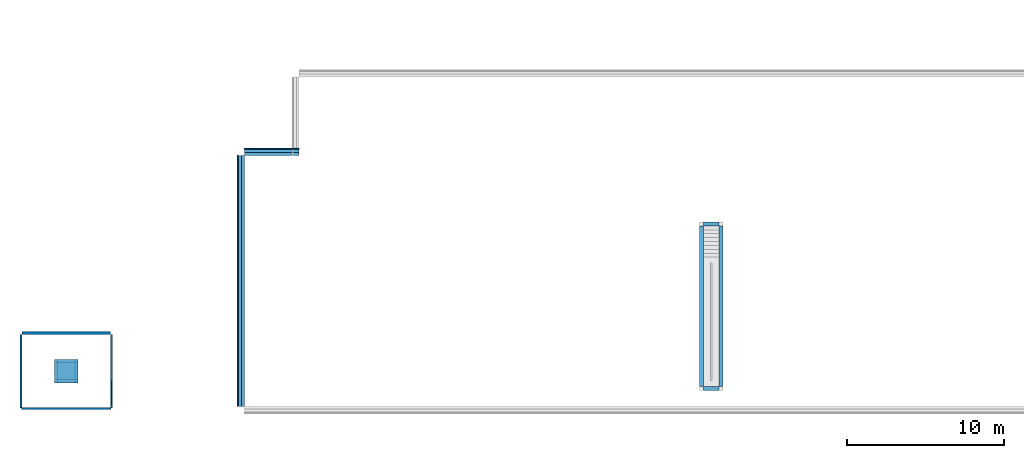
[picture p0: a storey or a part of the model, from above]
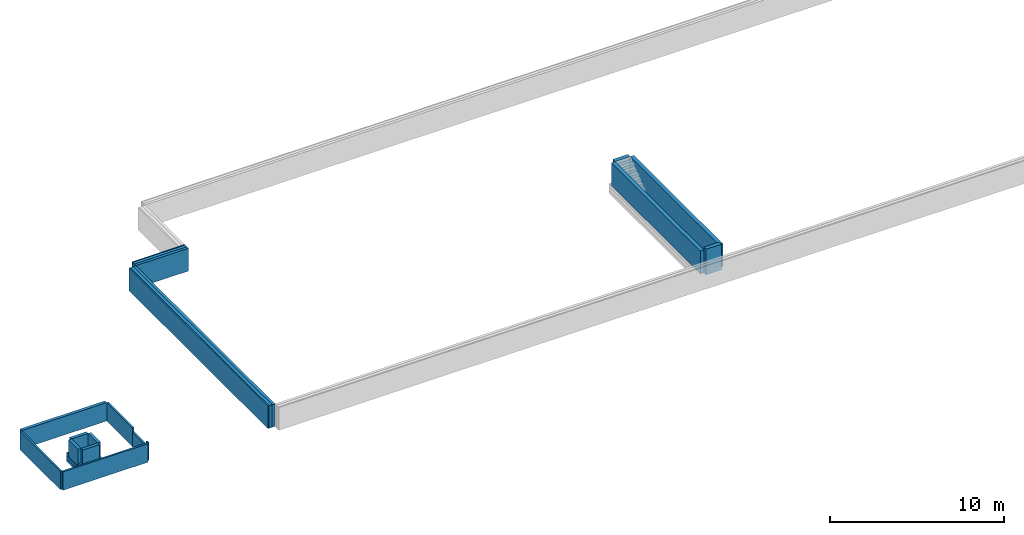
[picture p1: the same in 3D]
Properties of the parts of a building model (IFC2X3), part 1 of 4

# File
Description: ViewDefinition [CoordinationView_V2.0, SpaceBoundary2ndLevelAddOnView], Option [Drawing Scale: 100.000000], Option [Elements to export: Visible elements (on all stories)], Option [Partial Structure Display: Entire Model], Option [IFC Domain: All], Option [Structural Function: All Elements], Option [Convert Grid elements: On], Option [Convert IFC Annotations and ARCHICAD 2D elements: Off], Option [Convert 2D symbols of Doors and Windows: Off], Option [Export geometries that Participates in Collision Detection only: Off], Option [Split complex elements: On], Option [IFC Domain For Space Containment: Custom], Option [Elements in Solid Element Operations: Extruded/revolved], Option [Elements with junctions: Extruded/revolved without junctions], Option [Slabs with slanted edge(s): Extruded], Option [IFC Site Location: At Project Origin], Option [Curtain Wall export mode: Container Element], Option [Railing export mode: Container Element], Option [Stair export mode: Container Element], Option [Properties To Export: All properties], Option [Space containment: Off], Option [Bounding Box: Off], Option [Geometry to type objects: Off], Option [Element Properties: Visible Only], Option [Building Material Properties: Off], Option [Element Parameters: Off], Option [Component Parameters: Off], Option [IFC Base Quantities: Off], Option [Door Window Parameters: On], Option [IFC Space boundaries: On], Option [ARCHICAD Zone Categories as IFC Space classification data: Off], Option [Element Classifications: On]
File name: K:\09-Projektid\3_PÕHIPROJEKT\01-Arhitektuur\IFC\283_PP_ARH_IFC_19.05.2021.ifc
Time: 2021-05-19T14:48:47
Author: Kontakti Täisnimi
Organization: Building Designer Office
Written by: The EXPRESS Data Manager Version 5.02.0100.09 : 26 Sep 2013
Made in: IFC file generated by GRAPHISOFT ARCHICAD 23.0.0 INT FULL Windows version (IFC add-on version: 4006 INT FULL).
Authorization: Kontakti Täisnimi

# IfcSite, Politse- ja Piirivalveameti ning Päästeameti ühishoone
Description: Kinnistu Kirjeldus; RefLatitude: 59, 26, 0, 0; RefLongitude: 24, 45, 0, 0; RefElevation: 0 mm; Classification: 1.0.1 IfcSite (kinnistu) (RKAS BIM + ARCHICAD Classification 23 + v 2.0)
AR_Kinnistu - 020_Pindala: 15638 m2; 025_Max_kõrgus: 18000 mm; 015_Ehitatav_pindala: 5500 m2; 010_Katastritunnus: 32213:001:0035 ja 32213:001:0036

# IfcBuilding, Politse- ja Piirivalveameti ning Päästeameti ühishoone
Classification: 1.0.2 IfcBuilding (hoone) (RKAS BIM + ARCHICAD Classification 23 + v 2.0)
AR_Hoone - 035_Sprinkler: no; 030_Hoone_aadress: Kohtla-Järve Järveküla tee 40 ja 40c; 040_Kõrgus: 8800 mm; 050_Neto_pindala: 2293.7 m2; 055_Neto_ruumala: 13540.2 m3; ?: 1820.8 m2; 001_Nimetus: Politse- ja Piirivalveameti ning Päästeameti ühishoone

# IfcBuildingStorey (5)
In: Politse- ja Piirivalveameti ning Päästeameti ühishoone
Name | Elevation (mm) | 060_Korruse_nimi | 065_Korruse_number | 070_Maapealne | Classification
Vundament | -4000 | Vundament | -1 | no
Esimene korrus | 0 | Esimene korrus | 1 | yes | 1.0.3 IfcBuildingStorey (korrus) (RKAS BIM + ARCHICAD Classification 23 + v 2.0)
Teine korrus | 3800 | Teine korrus | 2 | no | 1.0.3 IfcBuildingStorey (korrus) (RKAS BIM + ARCHICAD Classification 23 + v 2.0)
Katusekorrus | 7600 | Katusekorrus | 3 | no | 1.0.3 IfcBuildingStorey (korrus) (RKAS BIM + ARCHICAD Classification 23 + v 2.0)
Korrus +9.900 | 10600 | 3. Korrus | 4 | no | 1.0.3 IfcBuildingStorey (korrus) (RKAS BIM + ARCHICAD Classification 23 + v 2.0)

# IfcSpace: Üldine (103)
InteriorOrExteriorSpace: INTERNAL; Classification: 1.21 IfcSpaceType (ruum) (RKAS BIM + ARCHICAD Classification)
Pset_SpaceCommon - Reference: Korruse avatud netopind; Category: Üldine
AR_Ruum - 115_Kategooria: Üldine; 110_Tüüp: Korruse avatud netopind; 125_Turvatsoon: Üldine
AC_Pset_RenovationAndPhasing - Renovation Status: New
Name | In | LongName = 100_Nimi | 105_Number | 120_Pindala (m2)
133 | Esimene korrus | ÕPPEKLASS | 133 | 58.961
132 | Esimene korrus | FUAJEE JA OOTEALA | 132 | 46.0777 | Group: TTS-1
108 | Esimene korrus | RIIDED | 108 | 13.8598 | Group: TTS-1
117 | Esimene korrus | KORIDOR | 117 | 7.098
115 | Esimene korrus | LADU | 115 | 30.6687 | Group: TTS-1
102 | Esimene korrus | KOERTE PESU | 102 | 9.3016
103 | Esimene korrus | KOERTE TOIT | 103 | 18.9231
104 | Esimene korrus | HOIDLA 1 | 104 | 34.5052 | Group: TTS-1
107 | Esimene korrus | LABOR | 107 | 14.6453 | Group: TTS-1
105 | Esimene korrus | PÄÄSTETEHNIKA AUTOKOHT JA TEENINDUSALA | 105 | 267.174 | Group: TTS-1
136 | Esimene korrus | WC | 136 | 2.40002
109 | Esimene korrus | VOOLIKUHOOLDUS, LADU, TEHNIK | 109 | 92.1634 | Group: TTS-1
110 | Esimene korrus | PESUBOKS AUTOKOHT | 110 | 77.138 | Group: TTS-1
111 | Esimene korrus | VARUSTUSE HOIDMISE PIND | 111 | 13.1274
112 | Esimene korrus | SOE KONTEINERI KOHT | 112 | 51.2681 | Group: TTS-1
113 | Esimene korrus | SOE KONTEINERI KOHT | 113 | 52.4803 | Group: TTS-1
114 | Esimene korrus | PÄÄSTETEHNIKA ASUKOHT JA TEENINDUSALA | 114 | 238.822 | Group: TTS-1
116 | Esimene korrus | HINGAMISAPARAATIDE JA KEEMIA PÄÄSTEVESTIDE HOIDLA | 116 | 24.4685
118 | Esimene korrus | PÄÄSTERIIETE PESURUUM | 118 | 14.2618
119 | Esimene korrus | PÄÄSTERIIETE HOIURUUM | 119 | 18.421
121 | Esimene korrus | PESURUUM | 121 | 3.6
123 | Esimene korrus | TEHNIKA HOOLDUSRUUM | 123 | 24.6298 | Group: TTS-1
124 | Esimene korrus | MUST LADU | 124 | 42.2885 | Group: TTS-1
126 | Esimene korrus | PUHAS LADU | 126 | 21.5999 | Group: TTS-1
125 | Esimene korrus | MAJAHOIDJA RUUM | 125 | 4.29533
128 | Esimene korrus | KEEMIAHAAGIS | 128 | 36.5666 | Group: TTS-1
129 | Esimene korrus | KEEMIAHAAGIS | 129 | 40.3322 | Group: TTS-1
130 | Esimene korrus | KORISTUSVAHENDID | 130 | 2.55041
134 | Esimene korrus | WC 1 | 134 | 2.12791
135 | Esimene korrus | WC 2 | 135 | 2.12791
137 | Esimene korrus | INVA WC | 137 | 5.72
127 | Esimene korrus | WC | 127 | 2.39959
120 | Esimene korrus | MUSTAD RIIDED | 120 | 4.32
122 | Esimene korrus | PUHTAD RIIDED | 122 | 8.28407
139 | Esimene korrus | HOIURUUM | 139 | 10.752
140 | Esimene korrus | ASITÕENDITE HOIUSTAMISE VAHERUUM | 140 | 4.23248
142 | Esimene korrus | ELEKTRIKILP | 142 | 12.0964 | Group: TTS-1
144 | Esimene korrus | VESTLUSRUUM 2 | 144 | 10.2251
145 | Esimene korrus | MENETLUSRUUM | 145 | 10.224
146 | Esimene korrus | OHVRIABI KABINET | 146 | 10.224
149 | Esimene korrus | TREPIKODA 1 | 149 | 41.1572
148 | Esimene korrus | KORIDOR 1 | 148 | 38.2959
150 | Esimene korrus | TREPIKODA 2 | 150 | 12.366 | Group: TTS-3; TTS-1
151 | Esimene korrus | VENTILATSIOONI SEADMED | 151 | 13.2061 | Group: TTS-1
138 | Esimene korrus | KORISTUSKESKUS + KORISTUSVAHENDID | 138 | 10.3862
147 | Esimene korrus | KLIENDITEENINDUSE HÕIVEKIOSK | 147 | 6.285
141 | Esimene korrus | SERVERIRUUM | 141 | 14.6416 | Group: TTS-1
143 | Esimene korrus | VESTLUSRUUM 1 | 143 | 10.224
131 | Esimene korrus | SOOJASÕLM + VEEMÕÕDUSÕLM + VEEPEHMENDI | 131 | 16.354
106 | Esimene korrus | KOERTE KENNEL 2 | 106 | 5.83342
191 | Esimene korrus | HARJUTUSTORN 1.korrus | 191 | 26.0051
171 | Esimene korrus | HOIURUUM | 171 | 18.2464
101 | Esimene korrus | KOERTE KENNEL 1 | 101 | 5.83342
153 | Esimene korrus | VOOLIKUKUIVATUS | 153 | 9.21462
152 | Esimene korrus | ÕHUVÕTUKAMBER | 152 | 1.25261
181 | Esimene korrus | GARAAZ TSOON 2 | 181 | 145.583
181 | Esimene korrus | GARAAZ TSOON 1 | 181 | 96.4934
225 | Teine korrus | KABINET 2 | 225 | 14.4483
224 | Teine korrus | KABINET 1 | 224 | 14.1122
222 | Teine korrus | ABIRUUM | 222 | 1.11662
221 | Teine korrus | WC N | 221 | 1.22917
201 | Teine korrus | MEESKONNARUUM | 201 | 44.9337
202 | Teine korrus | JUHATAJA | 202 | 14.021
203 | Teine korrus | TÖÖRUUM 1 | 203 | 10.2588
205 | Teine korrus | PUHKETUBA 1 | 205 | 9.32987
207 | Teine korrus | WC | 207 | 2.5376
209 | Teine korrus | HOIDLA ABIRUUM | 209 | 5.23749
208 | Teine korrus | HOIDLA 2 | 208 | 8.06223
211 | Teine korrus | TREPIKODA 1 | 211 | 23.2083 | Group: TTS-2; TTS-3
210 | Teine korrus | VENTILATSIOONI SEADMED | 210 | 82.9101 | Group: TTS-2
246 | Teine korrus | KORISTUS VAHENDID | 246 | 2.92963
212 | Teine korrus | JÕUSAAL | 212 | 50.5212
214 | Teine korrus | RIIETUSRUUM MEHED | 214 | 49.7801
215 | Teine korrus | SAUN M | 215 | 5.26619
216 | Teine korrus | PESURUUM M | 216 | 6.37
217 | Teine korrus | WC M | 217 | 1.28406
218 | Teine korrus | RIIETUSRUUM NAISED | 218 | 23.2138
219 | Teine korrus | SAUN N | 219 | 5.11412
220 | Teine korrus | PESURUUM N | 220 | 6.37999
223 | Teine korrus | TREPIKODA 2 | 223 | 17.1718 | Group: TTS-2; TTS-3
226 | Teine korrus | KABINET 3 | 226 | 14.4476
228 | Teine korrus | KABINET 5 | 228 | 11.076
227 | Teine korrus | KABINET 4 | 227 | 27.2631
230 | Teine korrus | KABINET 7 | 230 | 11.076
232 | Teine korrus | PUHKERUUM | 232 | 15.4464
231 | Teine korrus | KABINET 8 | 231 | 28.0912
235 | Teine korrus | WC | 235 | 1.65
243 | Teine korrus | WC | 243 | 1.62404
234 | Teine korrus | MEESKONNARUUM | 234 | 42.2256
233 | Teine korrus | WC | 233 | 1.75797
236 | Teine korrus | KOMANDOPEALIK | 236 | 12.1645
237 | Teine korrus | MEESKONNAVANEM JA INSPEKTOR | 237 | 16.5681
238 | Teine korrus | PUHKETUBA 1 | 238 | 11.772
239 | Teine korrus | PUHKETUBA 2 | 239 | 11.772
241 | Teine korrus | KORIDOR 1 | 241 | 29.4386
242 | Teine korrus | KORIDOR 2 | 242 | 57.6564
240 | Teine korrus | PUHKETUBA 3 | 240 | 11.772
229 | Teine korrus | KABINET 6 | 229 | 11.076
245 | Teine korrus | KÖÖK JA SÖÖGIRUUM | 245 | 14.7865
291 | Teine korrus | HARJUTUSTORN 2.korrus | 291 | 26.0051
206 | Teine korrus | PUHKETUBA 2 | 206 | 9.32987
204 | Teine korrus | TÖÖRUUM 2 | 204 | 10.2588
247 | Teine korrus | ÕHUVÕTUKAMBER | 247 | 6.41031

# IfcBeam: KON-00_GENEERILINE - KONSTRUKTSIOON 50 x 50 (8)
In: Katusekorrus
Type - PredefinedType: BEAM
Classification: 1.01 IfcBeamType (tala) (RKAS BIM + ARCHICAD Classification); Material: KON-00_GENEERILINE - KONSTRUKTSIOON
Pset_BeamCommon - Reference: KON-00; Slope: 0 deg
AR_001-002 - 002_Tüüp: KON-00
AC_Pset_RenovationAndPhasing - Renovation Status: Existing
Name | Span (mm)
4 x TALA | 690
2 x TALA | 801.788
2 x TALA | 800

# IfcBeam: KON-00_GENEERILINE - KONSTRUKTSIOON 70 x 70 (13)
In: Katusekorrus
Type - PredefinedType: BEAM
Classification: 1.01 IfcBeamType (tala) (RKAS BIM + ARCHICAD Classification); Material: KON-00_GENEERILINE - KONSTRUKTSIOON
Pset_BeamCommon - Reference: KON-00; Slope: 0 deg
AR_001-002 - 002_Tüüp: KON-00
AC_Pset_RenovationAndPhasing - Renovation Status: Existing
Name | Span (mm)
4 x TALA | 900
4 x TALA | 240
2 x TALA | 3100
3 x TALA | 1490

# IfcBeam: KON-00_GENEERILINE - KONSTRUKTSIOON 80 x 100 (38)
Type - PredefinedType: BEAM
Classification: 1.01 IfcBeamType (tala) (RKAS BIM + ARCHICAD Classification); Material: KON-00_GENEERILINE - KONSTRUKTSIOON
Pset_BeamCommon - Reference: KON-00; Span: 3000 mm; Slope: 0 deg; LoadBearing: no; IsExternal: no
AR_001-002 - 001_Nimetus: tõstukse siin; 002_Tüüp: KON-00
AC_Pset_RenovationAndPhasing - Renovation Status: New
Name | In
6 x tõstukse siin | Esimene korrus
32 x tõstukse siin | Teine korrus

# IfcBeam: KON-00_GENEERILINE - KONSTRUKTSIOON 90 x 90 (12)
In: Esimene korrus
Type - PredefinedType: BEAM
Classification: 1.01 IfcBeamType (tala) (RKAS BIM + ARCHICAD Classification); Material: KON-00_GENEERILINE - KONSTRUKTSIOON
Pset_BeamCommon - Reference: KON-00; LoadBearing: yes
AR_001-002 - 002_Tüüp: KON-00
AC_Pset_RenovationAndPhasing - Renovation Status: New
Name | Span (mm) | Slope (deg) | IsExternal
2 x TALA | 12155.1 | 5.7 | no
8 x TALA | 5125.34 | 5.7 | yes
2 x TALA | 19490.2 | 0 | yes

# IfcBeam: Top Chord Pitched-1Way 01 23 (4)
In: Teine korrus
Type - PredefinedType: BEAM
Classification: 1.01 IfcBeamType (tala) (RKAS BIM + ARCHICAD Classification); Material: ET-05_Teras
Pset_BeamCommon - Reference: Top Chord Pitched-1Way 01; LoadBearing: yes; IsExternal: no
AR_001-002 - 002_Tüüp: Top Chord Pitched-1Way 01
AC_Pset_RenovationAndPhasing - Renovation Status: New

# IfcBuildingElementPart (584)
Name | In | Material
2 x VKK-03_Kruus | Vundament | VKK-03_Kruus
SOJ-02_Soojustus - Fiiber Kõva | Vundament | SOJ-02_Soojustus - Fiiber Kõva
VKR-01_Betoon | Vundament | VKR-01_Betoon
24 x KON-04_Betoon - Konstuktsioon | Vundament | KON-04_Betoon - Konstuktsioon
12 x SOJ-06_Soojustus - Plastik Kõva | Vundament | SOJ-06_Soojustus - Plastik Kõva
2 x VKK-02_Liiv | Vundament | VKK-02_Liiv
SV-03_Plaat - Põrand | Vundament | SV-03_Plaat - Põrand
41 x KON-04_Betoon - Konstuktsioon | Esimene korrus | KON-04_Betoon - Konstuktsioon
23 x SOJ-06_Soojustus - Plastik Kõva | Esimene korrus | SOJ-06_Soojustus - Plastik Kõva
10 x Õhkvahe - Raam | Esimene korrus | Õhkvahe - Raam
14 x GENEERILINE - VÄLINE VOODER | Esimene korrus | GENEERILINE - VÄLINE VOODER
14 x SOJ-02_Soojustus - Fiiber Kõva | Esimene korrus | SOJ-02_Soojustus - Fiiber Kõva
KON-05_Betoon Plokk - Konstuktsioon | Esimene korrus | KON-05_Betoon Plokk - Konstuktsioon
34 x Õhkvahe | Esimene korrus | Õhkvahe
12 x Vineer | Esimene korrus | Vineer
13 x VKK-03_Kruus | Esimene korrus | VKK-03_Kruus
10 x VKR-01_Betoon | Esimene korrus | VKR-01_Betoon
4 x ET-06_Teras - Konstruktsioon | Esimene korrus | ET-06_Teras - Konstruktsioon
3 x SKR-05_Vineer | Esimene korrus | SKR-05_Vineer
7 x SKR-01_Õhkvahe - Raam | Esimene korrus | SKR-01_Õhkvahe - Raam
3 x SKR-04_Puitplaat | Esimene korrus | SKR-04_Puitplaat
3 x VKK-02_Liiv | Esimene korrus | VKK-02_Liiv
SV-03_Plaat - Põrand | Esimene korrus | SV-03_Plaat - Põrand
ET-05_Teras | Esimene korrus | ET-05_Teras
2 x ET-02_Raudbetoon - Toode | Esimene korrus | ET-02_Raudbetoon - Toode
7 x ET-05_Teras | Teine korrus | ET-05_Teras
17 x KON-05_Betoon Plokk - Konstuktsioon | Teine korrus | KON-05_Betoon Plokk - Konstuktsioon
39 x KON-04_Betoon - Konstuktsioon | Teine korrus | KON-04_Betoon - Konstuktsioon
18 x SOJ-06_Soojustus - Plastik Kõva | Teine korrus | SOJ-06_Soojustus - Plastik Kõva
11 x ET-01_Puit - Konstruktsioon | Teine korrus | ET-01_Puit - Konstruktsioon
20 x Õhkvahe - Raam | Teine korrus | Õhkvahe - Raam
13 x SOJ-04_Soojustus - Mineraal Kõva | Teine korrus | SOJ-04_Soojustus - Mineraal Kõva
Insulation - Mineral Soft+tala 50x150mm | Teine korrus | Insulation - Mineral Soft+tala 50x150mm
16 x SOJ-02_Soojustus - Fiiber Kõva | Teine korrus | SOJ-02_Soojustus - Fiiber Kõva
13 x KON-06_Raudbetoon - Konstruktsioon | Teine korrus | KON-06_Raudbetoon - Konstruktsioon
12 x VKR-01_Betoon | Teine korrus | VKR-01_Betoon
26 x SKR-02_Kipsplaat | Teine korrus | SKR-02_Kipsplaat
SOJ-03_Soojustus - Mineraal Pehme | Teine korrus | SOJ-03_Soojustus - Mineraal Pehme
9 x SKR-01_Õhkvahe - Raam | Teine korrus | SKR-01_Õhkvahe - Raam
4 x SKR-05_Vineer | Teine korrus | SKR-05_Vineer
SV-03_Plaat - Põrand | Teine korrus | SV-03_Plaat - Põrand
3 x SKR-04_Puitplaat | Teine korrus | SKR-04_Puitplaat
3 x ET-03_Raud | Teine korrus | ET-03_Raud
3 x Betoon | Teine korrus | Betoon
VV-00_GENEERILINE - VÄLINE VOODER | Teine korrus | VV-00_GENEERILINE - VÄLINE VOODER
9 x Õhkvahe | Teine korrus | Õhkvahe
2 x Puit - Konstruktsioon | Teine korrus | Puit - Konstruktsioon
Vineer | Teine korrus | Vineer
16 x KON-04_Betoon - Konstuktsioon | Katusekorrus | KON-04_Betoon - Konstuktsioon
8 x Betoon | Katusekorrus | Betoon
9 x SOJ-02_Soojustus - Fiiber Kõva | Katusekorrus | SOJ-02_Soojustus - Fiiber Kõva
ET-04_Alumiinium | Katusekorrus | ET-04_Alumiinium
11 x Õhkvahe - Raam | Katusekorrus | Õhkvahe - Raam
ET-06_Teras - Konstruktsioon | Katusekorrus | ET-06_Teras - Konstruktsioon
8 x SKR-05_Vineer | Katusekorrus | SKR-05_Vineer
7 x SKR-04_Puitplaat | Katusekorrus | SKR-04_Puitplaat
13 x SKR-01_Õhkvahe - Raam | Katusekorrus | SKR-01_Õhkvahe - Raam
4 x SOJ-06_Soojustus - Plastik Kõva | Katusekorrus | SOJ-06_Soojustus - Plastik Kõva
Vineer | Katusekorrus | Vineer
2 x ET-03_Raud | Katusekorrus | ET-03_Raud
KON-04_Betoon - Konstuktsioon | Korrus +9.900 | KON-04_Betoon - Konstuktsioon
Betoon | Korrus +9.900 | Betoon
SOJ-02_Soojustus - Fiiber Kõva | Korrus +9.900 | SOJ-02_Soojustus - Fiiber Kõva
10 x SKR-01_Õhkvahe - Raam | Korrus +9.900 | SKR-01_Õhkvahe - Raam
5 x SKR-05_Vineer | Korrus +9.900 | SKR-05_Vineer
8 x SKR-04_Puitplaat | Korrus +9.900 | SKR-04_Puitplaat
8 x Õhkvahe - Raam | Korrus +9.900 | Õhkvahe - Raam

# IfcBuildingElementProxy: CHS Hot-Finished Column 23 (2)
In: Katusekorrus
Material: ET-05_Teras
AR_Aken - 355_Pindala: 0 m2
AC_Pset_RenovationAndPhasing - Renovation Status: Existing

# IfcBuildingElementProxy: Caged Ladder 23, SISEREDEL 2
In: Teine korrus
AC_Pset_RenovationAndPhasing - Renovation Status: New

# IfcBuildingElementProxy: Cube 23 (3)
In: Esimene korrus
AR_Aken - 355_Pindala: 0 m2
AC_Pset_RenovationAndPhasing - Renovation Status: New
Name
2 x L-03
Survepesur

# IfcBuildingElementProxy: Cylinder Shell 23, PLAST TORU HARJUTUSTORNIS
In: Esimene korrus
AR_Aken - 355_Pindala: 0 m2
AC_Pset_RenovationAndPhasing - Renovation Status: Existing

# IfcBuildingElementProxy: Downspout 23 (4)
In: Esimene korrus
AR_Aken - 340_Soojusläbivus: 0; 355_Pindala: 0 m2
Name | Renovation Status
VIHMAVEETORU 2 | Existing
VIHMAVEETORU 1 | New
VIHMAVEETORU 4 | Existing
VIHMAVEETORU 3 | Existing

# IfcBuildingElementProxy: Elbow Tube 23 (4)
In: Esimene korrus
Classification: 1.02 IfcBuildingElementProxyType (objekt) (RKAS BIM + ARCHICAD Classification)
Pset_BuildingElementProxyCommon - Reference: Elbow Tube
AR_001-002 - 002_Tüüp: Elbow Tube
AC_Pset_RenovationAndPhasing - Renovation Status: New

# IfcBuildingElementProxy: Grid 23 (39)
AR_Aken - 355_Pindala: 0 m2
AC_Pset_RenovationAndPhasing - Renovation Status: New
Name | In
2 x Äravoolurenn (koertekennel) | Esimene korrus
Trapp (104) | Esimene korrus
2 x Äravoolurenn (109) | Esimene korrus
Trapp (109) | Esimene korrus
Äravoolurenn (110) | Esimene korrus
Trapp (107) | Esimene korrus
3 x Äravoolurenn (105) | Esimene korrus
Äravoolurenn (102) | Esimene korrus
Äravoolurenn (112) | Esimene korrus
Äravoolurenn (113) | Esimene korrus
4 x Äravoolurenn (114) | Esimene korrus
Trapp (120) | Esimene korrus
Trapp (123) | Esimene korrus
3 x Trapp (124) | Esimene korrus
Trapp (131) | Esimene korrus
2 x Trapp (126) | Esimene korrus
Äravoolurenn (128) | Esimene korrus
Äravoolurenn (129) | Esimene korrus
Trapp (151) | Esimene korrus
Trapp (138) | Esimene korrus
Trapp (152) | Esimene korrus
Trapp (137) | Esimene korrus
Trapp (125) | Esimene korrus
Äravoolurenn (220) | Teine korrus
Äravoolurenn (216) | Teine korrus
4 x Trapp (210) | Teine korrus

# IfcBuildingElementProxy: Gutter 23 (2)
In: Katusekorrus
AR_Aken - 340_Soojusläbivus: 0; 355_Pindala: 0 m2
AC_Pset_RenovationAndPhasing - Renovation Status: Existing
Name
VIHMAVEERENN 2
VIHMAVEERENN 1

# IfcBuildingElementProxy: IfcBuildingElementProxy (903)
Material: Teras - Konstruktsioon
Name | In | Classification | Renovation Status
6 x PIIRDE POST - 001 | Esimene korrus | 1.11 IfcRailing (piire) (_RKAS BIM + ARCHICAD Classification) | Existing
3 x Piirde Ülaosa - 001 | Esimene korrus | 1.11 IfcRailing (piire) (_RKAS BIM + ARCHICAD Classification) | New
47 x BALUSTER - 001 | Esimene korrus | 1.11 IfcRailing (piire) (_RKAS BIM + ARCHICAD Classification) | Existing
46 x PIIRDE POST - 001 | Teine korrus | 1.11 IfcRailing (piire) (_RKAS BIM + ARCHICAD Classification) | Existing
25 x Piirde Ülaosa - 001 | Teine korrus | 1.11 IfcRailing (piire) (_RKAS BIM + ARCHICAD Classification) | New
430 x BALUSTER - 001 | Teine korrus | 1.11 IfcRailing (piire) (_RKAS BIM + ARCHICAD Classification) | Existing
4 x Piirde ülemise osa ühendus - 001 | Teine korrus | 1.11 IfcRailing (piire) (_RKAS BIM + ARCHICAD Classification) | New
4 x HANDRAIL END - 001 | Teine korrus | Rail (ARCHICAD Classification) | New
HANDRAIL CONNECTION - 001 | Teine korrus | Rail (ARCHICAD Classification) | New
3 x KÄSIPUU - 001 | Teine korrus | 1.11 IfcRailing (piire) (_RKAS BIM + ARCHICAD Classification) | New
40 x PIIRDE POST - 001 | Katusekorrus | 1.11 IfcRailing (piire) (_RKAS BIM + ARCHICAD Classification) | Existing
20 x Piirde Ülaosa - 001 | Katusekorrus | 1.11 IfcRailing (piire) (_RKAS BIM + ARCHICAD Classification) | New
274 x BALUSTER - 001 | Katusekorrus | 1.11 IfcRailing (piire) (_RKAS BIM + ARCHICAD Classification) | Existing

# IfcBuildingElementProxy: Joists Beam 23 (3)
In: Katusekorrus
Material: ET-05_Teras
AR_Aken - 355_Pindala: 0 m2
AC_Pset_RenovationAndPhasing - Renovation Status: Existing

# IfcBuildingElementProxy: Pressurized Extinguisher 23 (20)
Name | In | 355_Pindala (m2) | Renovation Status
13 x Prügikast | Esimene korrus | 0 | Existing
Balloon Novec 1230 | Esimene korrus |  | New | Classification: 1.02 IfcBuildingElementProxyType (objekt) (RKAS BIM + ARCHICAD Classification); Pset_BuildingElementProxyCommon - Reference: Pressurized Extinguisher; AR_001-002 - 002_Tüüp: Pressurized Extinguisher
6 x Prügikast | Teine korrus | 0 | Existing

# IfcBuildingElementProxy: RHS Cold-Formed Beam 23 (2)
In: Teine korrus
Material: ET-05_Teras
AR_Aken - 355_Pindala: 0 m2
AC_Pset_RenovationAndPhasing - Renovation Status: Existing

# IfcBuildingElementProxy: SHS Cold-Formed Column 23 (1128)
Material: ET-05_Teras
AR_Aken - 355_Pindala: 0 m2
AC_Pset_RenovationAndPhasing - Renovation Status: Existing
Name | In
1088 x Fassaadiribid | Esimene korrus
40 x Fassaadiribid | Teine korrus

# IfcBuildingElementProxy: SHS Hot-Finished Column 23 (7)
In: Esimene korrus
Material: ET-05_Teras
AR_Aken - 355_Pindala: 0 m2
AC_Pset_RenovationAndPhasing - Renovation Status: Existing

# IfcBuildingElementProxy: Shower Door 23, Fassaadiribid
In: Esimene korrus
AR_Aken - 355_Pindala: 0 m2
AC_Pset_RenovationAndPhasing - Renovation Status: Existing

# IfcBuildingElementProxy: Skylight Flat Panel 23 (3)
AR_Aken - 355_Pindala: 0 m2
Name | In | Renovation Status
L-01 | Katusekorrus | Existing
L-01 | Katusekorrus | New
L-02 | Korrus +9.900 | Existing

# IfcBuildingElementProxy: Smoke and Heat Detector 23, Pihusti
In: Esimene korrus
Classification: 1.02 IfcBuildingElementProxyType (objekt) (RKAS BIM + ARCHICAD Classification)
Pset_BuildingElementProxyCommon - Reference: Smoke and Heat Detector
AR_001-002 - 002_Tüüp: Smoke and Heat Detector
AC_Pset_RenovationAndPhasing - Renovation Status: New

# IfcBuildingElementProxy: Tube 23 (4)
In: Esimene korrus
Classification: 1.02 IfcBuildingElementProxyType (objekt) (RKAS BIM + ARCHICAD Classification)
Pset_BuildingElementProxyCommon - Reference: Tube
AR_001-002 - 002_Tüüp: Tube
AC_Pset_RenovationAndPhasing - Renovation Status: New

# IfcBuildingElementProxy: Wall Mounted Tap 23, Veekraan
In: Esimene korrus
AR_Aken - 355_Pindala: 0 m2
AC_Pset_RenovationAndPhasing - Renovation Status: New

# IfcBuildingElementProxy: Waste Receptacle 23, Prügikast
In: Esimene korrus
AR_Aken - 355_Pindala: 0 m2
AC_Pset_RenovationAndPhasing - Renovation Status: Existing

# IfcColumn: ET-02_Raudbetoon - Toode 180 x 180, POST
In: Esimene korrus
Type - PredefinedType: COLUMN
Classification: 1.03 IfcColumnType (post) (RKAS BIM + ARCHICAD Classification); Material: ET-02_Raudbetoon - Toode
Pset_ColumnCommon - Reference: ET-02; Slope: 90 deg; LoadBearing: yes; IsExternal: no
AR_001-002 - 002_Tüüp: ET-02
AC_Pset_RenovationAndPhasing - Renovation Status: New

# IfcColumn: ET-02_Raudbetoon - Toode 350 x 350, POST
In: Esimene korrus
Type - PredefinedType: COLUMN
Classification: 1.03 IfcColumnType (post) (RKAS BIM + ARCHICAD Classification); Material: ET-02_Raudbetoon - Toode
Pset_ColumnCommon - Reference: ET-02; Slope: 90 deg; LoadBearing: yes; IsExternal: no
AR_001-002 - 002_Tüüp: ET-02
AC_Pset_RenovationAndPhasing - Renovation Status: New

# IfcColumn: ET-02_Raudbetoon - Toode 400 x 400 (2)
Type - PredefinedType: COLUMN
Classification: 1.03 IfcColumnType (post) (RKAS BIM + ARCHICAD Classification); Material: ET-02_Raudbetoon - Toode
Pset_ColumnCommon - Reference: ET-02; Slope: 90 deg; LoadBearing: yes; IsExternal: no
AR_001-002 - 002_Tüüp: ET-02
AC_Pset_RenovationAndPhasing - Renovation Status: New
Name | In
POST | Esimene korrus
POST | Teine korrus

# IfcColumn: ET-02_Raudbetoon - Toode 500 x 240, POST
In: Esimene korrus
Type - PredefinedType: COLUMN
Classification: 1.03 IfcColumnType (post) (RKAS BIM + ARCHICAD Classification); Material: ET-02_Raudbetoon - Toode
Pset_ColumnCommon - Reference: ET-02; Slope: 90 deg; LoadBearing: yes; IsExternal: no
AR_001-002 - 002_Tüüp: ET-02
AC_Pset_RenovationAndPhasing - Renovation Status: New

# IfcColumn: ET-05_Teras 180 x 180, POST
In: Teine korrus
Type - PredefinedType: COLUMN
Classification: 1.03 IfcColumnType (post) (RKAS BIM + ARCHICAD Classification)
Pset_ColumnCommon - Reference: ET-05; Slope: 90 deg; LoadBearing: yes; IsExternal: no
AR_001-002 - 002_Tüüp: ET-05
AC_Pset_RenovationAndPhasing - Renovation Status: New

# IfcColumn: ET-05_Teras D140 (2)
In: Esimene korrus
Type - PredefinedType: COLUMN
Classification: 1.03 IfcColumnType (post) (RKAS BIM + ARCHICAD Classification); Material: ET-05_Teras
Pset_ColumnCommon - Reference: Roostevaba teras; Slope: 90 deg; LoadBearing: yes; IsExternal: no
AR_001-002 - 002_Tüüp: Roostevaba teras
AC_Pset_RenovationAndPhasing - Renovation Status: New

# IfcColumn: KON-00_GENEERILINE - KONSTRUKTSIOON 100 x 100 (14)
In: Esimene korrus
Type - PredefinedType: COLUMN
Classification: 1.03 IfcColumnType (post) (RKAS BIM + ARCHICAD Classification); Material: KON-00_GENEERILINE - KONSTRUKTSIOON
Pset_ColumnCommon - Reference: KON-00; Slope: 90 deg; LoadBearing: yes; IsExternal: yes
AR_001-002 - 002_Tüüp: KON-00
AC_Pset_RenovationAndPhasing - Renovation Status: New

# IfcColumn: KON-00_GENEERILINE - KONSTRUKTSIOON 150 x 100 (6)
In: Esimene korrus
Type - PredefinedType: COLUMN
Classification: 1.03 IfcColumnType (post) (RKAS BIM + ARCHICAD Classification); Material: KON-00_GENEERILINE - KONSTRUKTSIOON
Pset_ColumnCommon - Reference: KON-00; Slope: 90 deg; LoadBearing: yes; IsExternal: yes
AR_001-002 - 002_Tüüp: KON-00
AC_Pset_RenovationAndPhasing - Renovation Status: New

# IfcColumn: KON-00_GENEERILINE - KONSTRUKTSIOON 150 x 150 (41)
Type - PredefinedType: COLUMN
Classification: 1.03 IfcColumnType (post) (RKAS BIM + ARCHICAD Classification); Material: KON-00_GENEERILINE - KONSTRUKTSIOON
Pset_ColumnCommon - Reference: KON-00; Slope: 90 deg; LoadBearing: yes; IsExternal: yes
AR_001-002 - 002_Tüüp: KON-00
AC_Pset_RenovationAndPhasing - Renovation Status: New
Name | In
12 x POST | Esimene korrus
12 x POST | Teine korrus
17 x POST | Katusekorrus

# IfcColumn: KON-00_GENEERILINE - KONSTRUKTSIOON 50 x 50 (10)
In: Katusekorrus
Type - PredefinedType: COLUMN
Classification: 1.03 IfcColumnType (post) (RKAS BIM + ARCHICAD Classification); Material: KON-00_GENEERILINE - KONSTRUKTSIOON
Pset_ColumnCommon - Reference: KON-00; Slope: 90 deg
AR_001-002 - 002_Tüüp: KON-00
Name | Renovation Status
2 x POST | New | Pset_ColumnCommon - LoadBearing: yes; IsExternal: yes
8 x POST | Existing

# IfcColumn: KON-00_GENEERILINE - KONSTRUKTSIOON 70 x 70 (14)
In: Katusekorrus
Type - PredefinedType: COLUMN
Classification: 1.03 IfcColumnType (post) (RKAS BIM + ARCHICAD Classification); Material: KON-00_GENEERILINE - KONSTRUKTSIOON
Pset_ColumnCommon - Reference: KON-00; Slope: 90 deg
AR_001-002 - 002_Tüüp: KON-00
AC_Pset_RenovationAndPhasing - Renovation Status: Existing

# IfcColumn: KON-00_GENEERILINE - KONSTRUKTSIOON 80 x 100 (40)
In: Esimene korrus
Type - PredefinedType: COLUMN
Classification: 1.03 IfcColumnType (post) (RKAS BIM + ARCHICAD Classification); Material: KON-00_GENEERILINE - KONSTRUKTSIOON
Pset_ColumnCommon - Reference: KON-00; Slope: 90 deg
AR_001-002 - 002_Tüüp: KON-00
AC_Pset_RenovationAndPhasing - Renovation Status: Existing

# IfcColumn: KON-00_GENEERILINE - KONSTRUKTSIOON 90 x 90 (8)
In: Esimene korrus
Type - PredefinedType: COLUMN
Classification: 1.03 IfcColumnType (post) (RKAS BIM + ARCHICAD Classification); Material: KON-00_GENEERILINE - KONSTRUKTSIOON
Pset_ColumnCommon - Reference: KON-00; Slope: 90 deg; LoadBearing: yes; IsExternal: yes
AR_001-002 - 002_Tüüp: KON-00
AC_Pset_RenovationAndPhasing - Renovation Status: New

# IfcColumn: KON-00_GENEERILINE - KONSTRUKTSIOON D150 (12)
In: Esimene korrus
Type - PredefinedType: COLUMN
Classification: 1.03 IfcColumnType (post) (RKAS BIM + ARCHICAD Classification); Material: KON-00_GENEERILINE - KONSTRUKTSIOON
Pset_ColumnCommon - Reference: KON-00; Slope: 90 deg; LoadBearing: yes; IsExternal: yes
AR_001-002 - 002_Tüüp: KON-00
AC_Pset_RenovationAndPhasing - Renovation Status: New

# IfcDiscreteAccessory: Aluminium 1510, Madalsurve suruõhukompressor
In: Esimene korrus
Classification: 1.09 IfcDiscreteAccessoryType (tarvik) (RKAS BIM + ARCHICAD Classification); Material: Aluminium
AR_001-002 - 002_Tüüp: Aluminium
Pset_QuantityTakeOff - Reference: Aluminium
AC_Pset_RenovationAndPhasing - Renovation Status: New

# IfcDiscreteAccessory: Aluminium 790, Kõrgsurvepesur
In: Esimene korrus
Classification: 1.09 IfcDiscreteAccessoryType (tarvik) (RKAS BIM + ARCHICAD Classification); Material: Aluminium
AR_001-002 - 002_Tüüp: Aluminium
Pset_QuantityTakeOff - Reference: Aluminium
AC_Pset_RenovationAndPhasing - Renovation Status: New

# IfcDiscreteAccessory: Aluminium 840, KOMP (Kõrgsurve surukompressor)
In: Esimene korrus
Classification: 1.09 IfcDiscreteAccessoryType (tarvik) (RKAS BIM + ARCHICAD Classification); Material: Aluminium
AR_001-002 - 002_Tüüp: Aluminium
Pset_QuantityTakeOff - Reference: Aluminium
AC_Pset_RenovationAndPhasing - Renovation Status: New

# IfcDiscreteAccessory: Architrave 01 23 (60)
Classification: 1.09 IfcDiscreteAccessoryType (tarvik) (RKAS BIM + ARCHICAD Classification); Material: SV-01_Krohv - Kips
AR_Aken - 355_Pindala: 0 m2
AR_001-002 - 002_Tüüp: Architrave 01
Pset_QuantityTakeOff - Reference: Architrave 01
AC_Pset_RenovationAndPhasing - Renovation Status: Existing
Name | In
18 x AKNARAAM 01 | Esimene korrus
42 x AKNARAAM 01 | Teine korrus

# IfcDiscreteAccessory: Caged Ladder 23, VÄLISREDEL
In: Esimene korrus
Classification: 1.09 IfcDiscreteAccessoryType (tarvik) (RKAS BIM + ARCHICAD Classification)
AR_001-002 - 002_Tüüp: Caged Ladder
Pset_QuantityTakeOff - Reference: Caged Ladder
AC_Pset_RenovationAndPhasing - Renovation Status: New

# IfcDiscreteAccessory: Solar Photovoltaic Panel 23 (130)
In: Katusekorrus
Classification: 1.09 IfcDiscreteAccessoryType (tarvik) (RKAS BIM + ARCHICAD Classification)
AR_Aken - 355_Pindala: 0 m2
AR_001-002 - 002_Tüüp: Solar Photovoltaic Panel
Pset_QuantityTakeOff - Reference: Solar Photovoltaic Panel
AC_Pset_RenovationAndPhasing - Renovation Status: New

# IfcDiscreteAccessory: Text 3D 23 (2)
In: Katusekorrus
Classification: 1.09 IfcDiscreteAccessoryType (tarvik) (RKAS BIM + ARCHICAD Classification)
AR_001-002 - 002_Tüüp: Text 3D
Pset_QuantityTakeOff - Reference: Text 3D
AC_Pset_RenovationAndPhasing - Renovation Status: New

# IfcDiscreteAccessory: Tube 23 (2)
In: Esimene korrus
Classification: 1.09 IfcDiscreteAccessoryType (tarvik) (RKAS BIM + ARCHICAD Classification)
AR_Aken - 355_Pindala: 0 m2
AR_001-002 - 002_Tüüp: Tube
Pset_QuantityTakeOff - Reference: Tube
AC_Pset_RenovationAndPhasing - Renovation Status: New

# IfcDiscreteAccessory: UAP Column 23 (575)
In: Teine korrus
Classification: 1.09 IfcDiscreteAccessoryType (tarvik) (RKAS BIM + ARCHICAD Classification); Material: ET-05_Teras
AR_Aken - 355_Pindala: 0 m2
AR_001-002 - 002_Tüüp: UAP Column
Pset_QuantityTakeOff - Reference: UAP Column
Name | Renovation Status
552 x Fassaadiribid | Existing
23 x Fassaadiribid | New

# IfcDiscreteAccessory: Vertical Ladder 23 (4)
Classification: 1.09 IfcDiscreteAccessoryType (tarvik) (RKAS BIM + ARCHICAD Classification)
AR_001-002 - 001_Nimetus: välisredel; 002_Tüüp: Vertical Ladder
Pset_QuantityTakeOff - Reference: Vertical Ladder
AC_Pset_RenovationAndPhasing - Renovation Status: New
Name | In
VÄLISREDEL 1 | Esimene korrus
VÄLISREDEL 4 | Esimene korrus
VÄLISREDEL 2 | Teine korrus
VÄLISREDEL 3 | Korrus +9.900

# IfcDoor: Door 23 (2)
Type - OperationType: SINGLE_SWING_LEFT; ParameterTakesPrecedence: no; Sizeable: no
Type - Door Lining Properties - LiningDepth: 115 mm; LiningThickness: 40 mm; ThresholdDepth: 75 mm; ThresholdThickness: 12 mm; LiningOffset: -25 mm; ThresholdOffset: -25 mm; CasingThickness: 50 mm; CasingDepth: 19 mm
Type - Door Panel Properties - Panel 1 - PanelDepth: 40 mm; PanelOperation: SWINGING; PanelWidth: 1; PanelPosition: MIDDLE
OverallHeight: 2100 mm; Classification: 1.10 IfcDoorStyle (uks) (RKAS BIM + ARCHICAD Classification)
Pset_DoorCommon - ThermalTransmittance: 0; IsExternal: no
AR_Uks - 310_Materjal: metall; 320_Klaas: ilma klaasita; 335_Välispiire: no; 340_Soojusläbivus: 0; 345_Päikesekiirgus_tegur: nõudeid ei esitata; 360_Ratastooliga: no; 365_Isesulguv: yes; 370_Evakuatsiooniväljapääs: yes; 375_Viimistlus_seest: MUDELIS: Metal - Steel; Metal - Steel; MÄRKUS:; 376_Viimistlus_väljast: MUDELIS: Metal - Steel; Metal - Steel; MÄRKUS:; 900_Tootja: Undefined; 905_Mudel: Undefined; 910_Tooteinfo: Undefined; 915_Kasutus-ja_hooldusjuhend: Undefined
AC_Pset_RenovationAndPhasing - Renovation Status: New
Name | In | OverallWidth (mm) | Reference = 300_Tüüp | 001_Nimetus | 305_Ava_mõõt | 315_Avanemine | 325_Helipidavus | 330_Tulekindlus | 350_Klaaspakett | 355_Pindala (m2) | 380_Lukustus
SU-01-5 | Esimene korrus | 800 | SU-01-5 | Siseuks | 800x2 100 | Pöördavanev - Parem ; ARCHICAD tüüp: Side Hung | Rw≥30dB | nõudeid ei esitata | nõudeid ei esitata | 1.68 | mehaaniline
TU-01-8 | Teine korrus | 1000 | TU-01-8 | tuletõkke siseuks | 1 000x2 100 | põõrdavanev - Parem ; ARCHICAD tüüp: Side Hung | 30dB | EI30 | ilma klaasita | 2.1 | elektriline

# IfcDoor: Door 23, TU-01-8
In: Esimene korrus
Type - OperationType: SINGLE_SWING_LEFT; ParameterTakesPrecedence: no; Sizeable: no
Type - Door Lining Properties - LiningDepth: 115 mm; LiningThickness: 40 mm; ThresholdDepth: 75 mm; ThresholdThickness: 12 mm; LiningOffset: -60 mm; ThresholdOffset: -20 mm; CasingThickness: 50 mm; CasingDepth: 19 mm
Type - Door Panel Properties - Panel 1 - PanelDepth: 40 mm; PanelOperation: SWINGING; PanelWidth: 1; PanelPosition: MIDDLE
OverallHeight: 2100 mm; OverallWidth: 1000 mm; Classification: 1.10 IfcDoorStyle (uks) (RKAS BIM + ARCHICAD Classification)
Pset_DoorCommon - Reference: TU-01-8; ThermalTransmittance: 0; IsExternal: no
AR_Uks - 001_Nimetus: tuletõkke siseuks; 300_Tüüp: TU-01-8; 305_Ava_mõõt: 1 000x2 100; 310_Materjal: metall; 315_Avanemine: Pöördavanev - Parem ; ARCHICAD tüüp: Side Hung; 320_Klaas: ilma klaasita; 325_Helipidavus: 30 dB; 330_Tulekindlus: EI30; 335_Välispiire: no; 340_Soojusläbivus: 0; 345_Päikesekiirgus_tegur: nõudeid ei esitata; 350_Klaaspakett: ilma klaasita; 355_Pindala: 2.1 m2; 360_Ratastooliga: no; 365_Isesulguv: yes; 370_Evakuatsiooniväljapääs: yes; 375_Viimistlus_seest: MUDELIS: Metal - Steel; Metal - Steel; MÄRKUS:; 376_Viimistlus_väljast: MUDELIS: Metal - Steel; Metal - Steel; MÄRKUS:; 380_Lukustus: elektriline; 900_Tootja: Undefined; 905_Mudel: Undefined; 910_Tooteinfo: Undefined; 915_Kasutus-ja_hooldusjuhend: Undefined
AC_Pset_RenovationAndPhasing - Renovation Status: New

# IfcDoor: Door 23 (12)
Type - OperationType: SINGLE_SWING_LEFT; ParameterTakesPrecedence: no; Sizeable: no
Type - Door Lining Properties - LiningDepth: 115 mm; LiningThickness: 40 mm; ThresholdDepth: 75 mm; ThresholdThickness: 12 mm; LiningOffset: 0 mm; ThresholdOffset: 40 mm; CasingThickness: 50 mm; CasingDepth: 19 mm
Type - Door Panel Properties - Panel 1 - PanelDepth: 40 mm; PanelOperation: SWINGING; PanelWidth: 1; PanelPosition: MIDDLE
Classification: 1.10 IfcDoorStyle (uks) (RKAS BIM + ARCHICAD Classification)
Pset_DoorCommon - ThermalTransmittance: 0
AR_Uks - 900_Tootja: Undefined; 905_Mudel: Undefined; 910_Tooteinfo: Undefined; 915_Kasutus-ja_hooldusjuhend: Undefined
AC_Pset_RenovationAndPhasing - Renovation Status: New
Name | In | OverallHeight (mm) | OverallWidth (mm) | Reference = 300_Tüüp | IsExternal = 335_Välispiire | 001_Nimetus | 305_Ava_mõõt | 310_Materjal | 315_Avanemine | 320_Klaas | 325_Helipidavus | 330_Tulekindlus | 340_Soojusläbivus | 345_Päikesekiirgus_tegur | 350_Klaaspakett | 355_Pindala (m2) | 360_Ratastooliga | 365_Isesulguv = 370_Evakuatsiooniväljapääs | 375_Viimistlus_seest = 376_Viimistlus_väljast | 380_Lukustus
TU-01-8 | Esimene korrus | 2100 | 1000 | TU-01-8 | no | tuletõkke siseuks | 1 000x2 100 | metall | Pöördavanev - Parem ; ARCHICAD tüüp: Side Hung | ilma klaasita | 30dB | EI30 | 0 | nõudeid ei esitata | ilma klaasita | 2.1 | no | no | MUDELIS: Metal - Steel; Metal - Steel; MÄRKUS: | elektriline
TU-01-7 | Esimene korrus | 2100 | 1000 | TU-01-7 | no | tuletõkke siseuks | 1 000x2 100 | metall | Pöördavanev - Parem ; ARCHICAD tüüp: Side Hung | tuletõkkeklaas EI30 | 30 dB | EI30 | 0 | nõudeid ei esitata | tuletõkkeklaas | 2.1 | yes | yes | MUDELIS: Wood - Pine Grained Horizontal; Wood - Pine Grained Horizontal; MÄRKUS: | elektriline | Pset_DoorCommon - GlazingAreaFraction: 1.31837
TU-01-8 | Esimene korrus | 2100 | 1000 | TU-01-8 | no | tuletõkke siseuks | 1 000x2 100 | metall | Pöördavanev - Parem ; ARCHICAD tüüp: Side Hung | ilma klaasita | 30 dB | EI30 | 0 | nõudeid ei esitata | ilma klaasita | 2.1 | no | yes | MUDELIS: Metal - Steel; Metal - Steel; MÄRKUS: | elektriline
2 x SU-02-1 | Esimene korrus | 2100 | 800 | SU-02-1 | no | Siseuks | 800x2 100 | puit | Pöördavanev - Parem ; ARCHICAD tüüp: Side Hung | ilma klaasita | Rw≥30dB | nõudeid ei esitata | 0 | nõudeid ei esitata | nõudeid ei esitata | 1.68 | no | no | MUDELIS: Wood - Pine Grained Horizontal; Wood - Pine Grained Horizontal; MÄRKUS: | mehaaniline
VU-10 | Teine korrus | 2100 | 900 | VU-10 | yes | Välisuks ühepoolne | 900x2 100 | metall | pöördavanev - Parem ; ARCHICAD tüüp: Side Hung | 3xklaaspakett | Rw≥35dB | nõudeid ei esitata | 1.1 | 0,4 | 3k (6+4+10) | 1.89 | no | yes | MUDELIS: Wood - Pine Grained Horizontal; Wood - Pine Grained Horizontal; MÄRKUS: | elektriline | Pset_DoorCommon - GlazingAreaFraction: 1.14117
SU-03-1 | Teine korrus | 2100 | 700 | SU-03-1 | no | siseuks | 700x2 100 | täisklaasuks | pöördavanev - Parem ; ARCHICAD tüüp: Side Hung | toonitud klaas | nõudeid ei esitata | nõudeid ei esitata | 0 | nõudeid ei esitata | 1xklaas | 1.47 | no | no | MUDELIS: Metal - Steel; Metal - Steel; MÄRKUS: | lukus puudub
SU-02-1 | Teine korrus | 2100 | 800 | SU-02-1 | no | siseuks | 800x2 100 | puit | pöördavanev - Parem ; ARCHICAD tüüp: Side Hung | ilma klaasita | Rw≥30dB | nõudeid ei esitata | 0 | nõudeid ei esitata | ilma klaasita | 1.68 | no | yes | MUDELIS: Wood - Pine Grained Horizontal; Wood - Pine Grained Horizontal; MÄRKUS: | mehaaniline
LU-21 | Teine korrus | 1850 | 1100 | LU-21 | yes | aknaluuk | 1 100x1 850 | vineer | pöördavanev - Parem ; ARCHICAD tüüp: Side Hung | ilma klaasita | nõudeid ei esitata | nõudeid ei esitata | 0 | nõudeid ei esitata | ilma klaasita | 2.035 | no | no | MUDELIS: Wood - Pine Grained Horizontal; Wood - Pine Grained Horizontal; MÄRKUS: | mehaaniline
VU-22 | Teine korrus | 2100 | 950 | VU-22 | yes | Välisuks ühepoolne | 950x2 100 | metall | pöördavanev - Parem ; ARCHICAD tüüp: Side Hung | 2xklaaspakett | nõudeid ei esitata | nõudeid ei esitata | 0 | nõudeid ei esitata | 2k 4+10 | 1.995 | no | no | MUDELIS: Wood - Pine Grained Horizontal; Wood - Pine Grained Horizontal; MÄRKUS: | mehaaniline | Pset_DoorCommon - GlazingAreaFraction: 1.22977
SU-01-5 | Teine korrus | 2100 | 800 | SU-01-5 | no | Siseuks | 800x2 100 | metall | põõrdavanev - Parem ; ARCHICAD tüüp: Side Hung | ilma klaasita | nõudeid ei esitata | nõudeid ei esitata | 0 | nõudeid ei esitata | ilma klaasita | 1.68 | no | yes | MUDELIS: Metal - Steel; Metal - Steel; MÄRKUS: | mehaaniline
LU-21 | Katusekorrus | 1850 | 1100 | LU-21 | yes | aknaluuk | 1 100x1 850 | vineer | pöördavanev - Parem ; ARCHICAD tüüp: Side Hung | ilma klaasita | nõudeid ei esitata | nõudeid ei esitata | 0 | nõudeid ei esitata | ilma klaasita | 2.035 | no | no | MUDELIS: Wood - Pine Grained Horizontal; Wood - Pine Grained Horizontal; MÄRKUS: | mehaaniline

# IfcDoor: Door 23 (10)
Type - OperationType: SINGLE_SWING_LEFT; ParameterTakesPrecedence: no; Sizeable: no
Type - Door Lining Properties - LiningDepth: 115 mm; LiningThickness: 40 mm; ThresholdDepth: 75 mm; ThresholdThickness: 12 mm; LiningOffset: 140 mm; ThresholdOffset: 180 mm; CasingThickness: 50 mm; CasingDepth: 19 mm
Type - Door Panel Properties - Panel 1 - PanelDepth: 40 mm; PanelOperation: SWINGING; PanelWidth: 1; PanelPosition: MIDDLE
OverallHeight: 2100 mm; Classification: 1.10 IfcDoorStyle (uks) (RKAS BIM + ARCHICAD Classification)
Pset_DoorCommon - ThermalTransmittance: 0; IsExternal: no
AR_Uks - 335_Välispiire: no; 340_Soojusläbivus: 0; 345_Päikesekiirgus_tegur: nõudeid ei esitata; 900_Tootja: Undefined; 905_Mudel: Undefined; 910_Tooteinfo: Undefined; 915_Kasutus-ja_hooldusjuhend: Undefined
AC_Pset_RenovationAndPhasing - Renovation Status: New
Name | In | OverallWidth (mm) | Reference = 300_Tüüp | 001_Nimetus | 305_Ava_mõõt | 310_Materjal | 315_Avanemine | 320_Klaas | 325_Helipidavus | 330_Tulekindlus | 350_Klaaspakett | 355_Pindala (m2) | 360_Ratastooliga | 365_Isesulguv | 370_Evakuatsiooniväljapääs | 375_Viimistlus_seest = 376_Viimistlus_väljast | 380_Lukustus
2 x SU-01-3 | Esimene korrus | 900 | SU-01-3 | Siseuks | 900x2 100 | metall | Pöördavanev - Parem ; ARCHICAD tüüp: Side Hung | ilma klaasita | nõudeid ei esitata | nõudeid ei esitata | nõudeid ei esitata | 1.89 | no | no | yes | MUDELIS: Wood - Pine Grained Horizontal; Wood - Pine Grained Horizontal; MÄRKUS: | mehaaniline | Pset_DoorCommon - GlazingAreaFraction: 1.46717
SU-02-4 | Esimene korrus | 1000 | SU-02-4 | siseuks | 1 000x2 100 | puit | Pöördavanev - Parem ; ARCHICAD tüüp: Side Hung | ilma klaasita | Rw≥30dB | nõudeid ei esitata | nõudeid ei esitata | 2.1 | no | no | yes | MUDELIS: Wood - Pine Grained Horizontal; Wood - Pine Grained Horizontal; MÄRKUS: | mehaaniline
SU-01-1 | Esimene korrus | 900 | SU-01-1 | Siseuks | 900x2 100 | metall | Pöördavanev - Parem ; ARCHICAD tüüp: Side Hung | ilma klaasita | Rw≥30dB | nõudeid ei esitata | nõudeid ei esitata | 1.89 | yes | yes | yes | MUDELIS: Metal - Steel; Metal - Steel; MÄRKUS: | elektriline
TU-01-7 | Esimene korrus | 1000 | TU-01-7 | tuletõkke siseuks | 1 000x2 100 | metall | Pöördavanev - Parem ; ARCHICAD tüüp: Side Hung | tuletõkkeklaas EI30 | 30 dB | EI30 | tuletõkkeklaas | 2.1 | yes | yes | yes | MUDELIS: Wood - Pine Grained Horizontal; Wood - Pine Grained Horizontal; MÄRKUS: | elektriline | Pset_DoorCommon - GlazingAreaFraction: 1.31837
SU-01-1 | Esimene korrus | 900 | SU-01-1 | Siseuks | 900x2 100 | metall | Pöördavanev - Parem ; ARCHICAD tüüp: Side Hung | ilma klaasita | Rw≥30dB | nõudeid ei esitata | nõudeid ei esitata | 1.89 | no | yes | yes | MUDELIS: Metal - Steel; Metal - Steel; MÄRKUS: | elektriline
SU-02-1 | Teine korrus | 800 | SU-02-1 | siseuks | 800x2 100 | puit | pöördavanev - Parem ; ARCHICAD tüüp: Side Hung | ilma klaasita | Rw≥30dB | nõudeid ei esitata | ilma klaasita | 1.68 | no | yes | yes | MUDELIS: Metal - Steel; Metal - Steel; MÄRKUS: | mehaaniline
SU-02-1 | Teine korrus | 800 | SU-02-1 | siseuks | 800x2 100 | puit | pöördavanev - Parem ; ARCHICAD tüüp: Side Hung | ilma klaasita | Rw≥30dB | nõudeid ei esitata | ilma klaasita | 1.68 | no | yes | yes | MUDELIS: Wood - Pine Grained Horizontal; Wood - Pine Grained Horizontal; MÄRKUS: | mehaaniline
SU-01-1 | Teine korrus | 900 | SU-01-1 | Siseuks | 900x2 100 | metall | pöördavanev - Parem ; ARCHICAD tüüp: Side Hung | ilma klaasita | Rw≥30dB | nõudeid ei esitata | ilma klaasita | 1.89 | no | no | no | MUDELIS: Metal - Steel; Metal - Steel; MÄRKUS: | elektriline
SU-01-2 | Teine korrus | 1000 | SU-01-2 | siseuks | 1 000x2 100 | metall | põõrdavanev - Parem ; ARCHICAD tüüp: Side Hung | ilma klaasita | Rw≥30dB | nõudeid ei esitata | ilma klaasita | 2.1 | no | no | no | MUDELIS: Wood - Pine Grained Horizontal; Wood - Pine Grained Horizontal; MÄRKUS: | elektriline

# IfcDoor: Door 23 (2)
In: Esimene korrus
Type - OperationType: SINGLE_SWING_LEFT; ParameterTakesPrecedence: no; Sizeable: no
Type - Door Lining Properties - LiningDepth: 115 mm; LiningThickness: 40 mm; ThresholdDepth: 75 mm; ThresholdThickness: 12 mm; LiningOffset: 190 mm; ThresholdOffset: 230 mm; CasingThickness: 50 mm; CasingDepth: 19 mm
Type - Door Panel Properties - Panel 1 - PanelDepth: 40 mm; PanelOperation: SWINGING; PanelWidth: 1; PanelPosition: MIDDLE
OverallHeight: 2100 mm; OverallWidth: 900 mm; Classification: 1.10 IfcDoorStyle (uks) (RKAS BIM + ARCHICAD Classification)
Pset_DoorCommon - Reference: TU-01-10; ThermalTransmittance: 0; IsExternal: no
AR_Uks - 001_Nimetus: tuletõkke siseuks; 300_Tüüp: TU-01-10; 305_Ava_mõõt: 900x2 100; 310_Materjal: metall; 315_Avanemine: Pöördavanev - Parem ; ARCHICAD tüüp: Side Hung; 320_Klaas: ilma klaasita; 325_Helipidavus: 30 dB; 330_Tulekindlus: EI30; 335_Välispiire: no; 340_Soojusläbivus: 0; 345_Päikesekiirgus_tegur: nõudeid ei esitata; 350_Klaaspakett: nõudeid ei esitata; 355_Pindala: 1.89 m2; 360_Ratastooliga: no; 365_Isesulguv: yes; 370_Evakuatsiooniväljapääs: no; 375_Viimistlus_seest: MUDELIS: Wood - Pine Grained Horizontal; Wood - Pine Grained Horizontal; MÄRKUS:; 376_Viimistlus_väljast: MUDELIS: Wood - Pine Grained Horizontal; Wood - Pine Grained Horizontal; MÄRKUS:; 380_Lukustus: elektriline; 900_Tootja: Undefined; 905_Mudel: Undefined; 910_Tooteinfo: Undefined; 915_Kasutus-ja_hooldusjuhend: Undefined
AC_Pset_RenovationAndPhasing - Renovation Status: New

# IfcDoor: Door 23, SU-01-4
In: Teine korrus
Type - OperationType: SINGLE_SWING_LEFT; ParameterTakesPrecedence: no; Sizeable: no
Type - Door Lining Properties - LiningDepth: 115 mm; LiningThickness: 40 mm; ThresholdDepth: 75 mm; ThresholdThickness: 12 mm; LiningOffset: 205 mm; ThresholdOffset: 245 mm; CasingThickness: 50 mm; CasingDepth: 19 mm
Type - Door Panel Properties - Panel 1 - PanelDepth: 40 mm; PanelOperation: SWINGING; PanelWidth: 1; PanelPosition: MIDDLE
OverallHeight: 2100 mm; OverallWidth: 900 mm; Classification: 1.10 IfcDoorStyle (uks) (RKAS BIM + ARCHICAD Classification)
Pset_DoorCommon - Reference: SU-01-4; ThermalTransmittance: 0; GlazingAreaFraction: 1.46717; IsExternal: no
AR_Uks - 001_Nimetus: Siseuks; 300_Tüüp: SU-01-4; 305_Ava_mõõt: 900x2 100; 310_Materjal: metall; 315_Avanemine: Pöördavanev - Parem ; ARCHICAD tüüp: Side Hung; 320_Klaas: ilma klaasita; 325_Helipidavus: nõudeid ei esitata; 330_Tulekindlus: nõudeid ei esitata; 335_Välispiire: no; 340_Soojusläbivus: 0; 345_Päikesekiirgus_tegur: nõudeid ei esitata; 350_Klaaspakett: nõudeid ei esitata; 355_Pindala: 1.89 m2; 360_Ratastooliga: no; 365_Isesulguv: yes; 370_Evakuatsiooniväljapääs: yes; 375_Viimistlus_seest: MUDELIS: Wood - Pine Grained Horizontal; Wood - Pine Grained Horizontal; MÄRKUS:; 376_Viimistlus_väljast: MUDELIS: Wood - Pine Grained Horizontal; Wood - Pine Grained Horizontal; MÄRKUS:; 380_Lukustus: elektriline; 900_Tootja: Undefined; 905_Mudel: Undefined; 910_Tooteinfo: Undefined; 915_Kasutus-ja_hooldusjuhend: Undefined
AC_Pset_RenovationAndPhasing - Renovation Status: New

# IfcDoor: Door 23 (2)
In: Esimene korrus
Type - OperationType: SINGLE_SWING_LEFT; ParameterTakesPrecedence: no; Sizeable: no
Type - Door Lining Properties - LiningDepth: 115 mm; LiningThickness: 40 mm; ThresholdDepth: 75 mm; ThresholdThickness: 12 mm; LiningOffset: 235 mm; ThresholdOffset: 235 mm; CasingThickness: 50 mm; CasingDepth: 19 mm
Type - Door Panel Properties - Panel 1 - PanelDepth: 40 mm; PanelOperation: SWINGING; PanelWidth: 1; PanelPosition: MIDDLE
OverallHeight: 2100 mm; OverallWidth: 800 mm; Classification: 1.10 IfcDoorStyle (uks) (RKAS BIM + ARCHICAD Classification)
Pset_DoorCommon - Reference: SU-01-6; ThermalTransmittance: 0; IsExternal: no
AR_Uks - 001_Nimetus: Siseuks; 300_Tüüp: SU-01-6; 305_Ava_mõõt: 800x2 100; 310_Materjal: metall; 315_Avanemine: Pöördavanev - Parem ; ARCHICAD tüüp: Side Hung; 320_Klaas: ilma klaasita; 325_Helipidavus: nõudeid ei esitata; 330_Tulekindlus: nõudeid ei esitata; 335_Välispiire: no; 340_Soojusläbivus: 0; 345_Päikesekiirgus_tegur: nõudeid ei esitata; 350_Klaaspakett: nõudeid ei esitata; 355_Pindala: 1.68 m2; 360_Ratastooliga: no; 365_Isesulguv: yes; 370_Evakuatsiooniväljapääs: yes; 375_Viimistlus_seest: MUDELIS: Metal - Steel; Metal - Steel; MÄRKUS:; 376_Viimistlus_väljast: MUDELIS: Metal - Steel; Metal - Steel; MÄRKUS:; 380_Lukustus: elektriline; 900_Tootja: Undefined; 905_Mudel: Undefined; 910_Tooteinfo: Undefined; 915_Kasutus-ja_hooldusjuhend: Undefined
AC_Pset_RenovationAndPhasing - Renovation Status: New

# IfcDoor: Door 23, SU-01-1
In: Esimene korrus
Type - OperationType: SINGLE_SWING_LEFT; ParameterTakesPrecedence: no; Sizeable: no
Type - Door Lining Properties - LiningDepth: 115 mm; LiningThickness: 40 mm; ThresholdDepth: 75 mm; ThresholdThickness: 12 mm; LiningOffset: 240 mm; ThresholdOffset: 280 mm; CasingThickness: 50 mm; CasingDepth: 19 mm
Type - Door Panel Properties - Panel 1 - PanelDepth: 40 mm; PanelOperation: SWINGING; PanelWidth: 1; PanelPosition: MIDDLE
OverallHeight: 2100 mm; OverallWidth: 900 mm; Classification: 1.10 IfcDoorStyle (uks) (RKAS BIM + ARCHICAD Classification)
Pset_DoorCommon - Reference: SU-01-1; ThermalTransmittance: 0; IsExternal: no
AR_Uks - 001_Nimetus: Siseuks; 300_Tüüp: SU-01-1; 305_Ava_mõõt: 900x2 100; 310_Materjal: metall; 315_Avanemine: Pöördavanev - Parem ; ARCHICAD tüüp: Side Hung; 320_Klaas: ilma klaasita; 325_Helipidavus: Rw≥30dB; 330_Tulekindlus: nõudeid ei esitata; 335_Välispiire: no; 340_Soojusläbivus: 0; 345_Päikesekiirgus_tegur: nõudeid ei esitata; 350_Klaaspakett: nõudeid ei esitata; 355_Pindala: 1.89 m2; 360_Ratastooliga: no; 365_Isesulguv: yes; 370_Evakuatsiooniväljapääs: yes; 375_Viimistlus_seest: MUDELIS: Metal - Steel; Metal - Steel; MÄRKUS:; 376_Viimistlus_väljast: MUDELIS: Metal - Steel; Metal - Steel; MÄRKUS:; 380_Lukustus: elektriline; 900_Tootja: Undefined; 905_Mudel: Undefined; 910_Tooteinfo: Undefined; 915_Kasutus-ja_hooldusjuhend: Undefined
AC_Pset_RenovationAndPhasing - Renovation Status: New

# IfcDoor: Door 23 (2)
In: Esimene korrus
Type - OperationType: SINGLE_SWING_LEFT; ParameterTakesPrecedence: no; Sizeable: no
Type - Door Lining Properties - LiningDepth: 115 mm; LiningThickness: 40 mm; ThresholdDepth: 75 mm; ThresholdThickness: 12 mm; LiningOffset: 50 mm; ThresholdOffset: 90 mm; CasingThickness: 50 mm; CasingDepth: 19 mm
Type - Door Panel Properties - Panel 1 - PanelDepth: 40 mm; PanelOperation: SWINGING; PanelWidth: 1; PanelPosition: MIDDLE
OverallHeight: 2100 mm; OverallWidth: 900 mm; Classification: 1.10 IfcDoorStyle (uks) (RKAS BIM + ARCHICAD Classification)
Pset_DoorCommon - Reference: VU-09; ThermalTransmittance: 0; GlazingAreaFraction: 1.46717; IsExternal: yes
AR_Uks - 001_Nimetus: välisuks ühepoolne; 300_Tüüp: VU-09; 305_Ava_mõõt: 900x2 100; 310_Materjal: metall; 315_Avanemine: põõrdavanev - Parem ; ARCHICAD tüüp: Side Hung; 320_Klaas: ilma klaasita, metallvõrk; 325_Helipidavus: nõudeid ei esitata; 330_Tulekindlus: nõudeid ei esitata; 335_Välispiire: yes; 340_Soojusläbivus: 0; 345_Päikesekiirgus_tegur: nõudeid ei esitata; 350_Klaaspakett: ilma klaasita; 355_Pindala: 1.89 m2; 360_Ratastooliga: no; 365_Isesulguv: no; 370_Evakuatsiooniväljapääs: no; 375_Viimistlus_seest: MUDELIS: Wood - Pine Grained Horizontal; Wood - Pine Grained Horizontal; MÄRKUS:; 376_Viimistlus_väljast: MUDELIS: Wood - Pine Grained Horizontal; Wood - Pine Grained Horizontal; MÄRKUS:; 380_Lukustus: mehaaniline; 900_Tootja: Undefined; 905_Mudel: Undefined; 910_Tooteinfo: Undefined; 915_Kasutus-ja_hooldusjuhend: Undefined
AC_Pset_RenovationAndPhasing - Renovation Status: New

# IfcDoor: Door 23, SU-01-7
In: Esimene korrus
Type - OperationType: SINGLE_SWING_LEFT; ParameterTakesPrecedence: no; Sizeable: no
Type - Door Lining Properties - LiningDepth: 115 mm; LiningThickness: 40 mm; ThresholdDepth: 75 mm; ThresholdThickness: 12 mm; LiningOffset: 80 mm; ThresholdOffset: 120 mm; CasingThickness: 50 mm; CasingDepth: 19 mm
Type - Door Panel Properties - Panel 1 - PanelDepth: 40 mm; PanelOperation: SWINGING; PanelWidth: 1; PanelPosition: MIDDLE
OverallHeight: 2100 mm; OverallWidth: 900 mm; Classification: 1.10 IfcDoorStyle (uks) (RKAS BIM + ARCHICAD Classification)
Pset_DoorCommon - Reference: SU-01-7; ThermalTransmittance: 0; IsExternal: no
AR_Uks - 001_Nimetus: Siseuks; 300_Tüüp: SU-01-7; 305_Ava_mõõt: 900x2 100; 310_Materjal: metall; 315_Avanemine: pöördavanev - Parem ; ARCHICAD tüüp: Side Hung; 320_Klaas: ilma klaasita; 325_Helipidavus: nõudeid ei esitata; 330_Tulekindlus: nõudeid ei esitata; 335_Välispiire: no; 340_Soojusläbivus: 1.1; 345_Päikesekiirgus_tegur: nõudeid ei esitata; 350_Klaaspakett: ilma klaasita; 355_Pindala: 1.89 m2; 360_Ratastooliga: no; 365_Isesulguv: no; 370_Evakuatsiooniväljapääs: yes; 375_Viimistlus_seest: MUDELIS: Metal - Steel; Metal - Steel; MÄRKUS:; 376_Viimistlus_väljast: MUDELIS: Metal - Steel; Metal - Steel; MÄRKUS:; 380_Lukustus: mehaaniline; 900_Tootja: Undefined; 905_Mudel: Undefined; 910_Tooteinfo: Undefined; 915_Kasutus-ja_hooldusjuhend: Undefined
AC_Pset_RenovationAndPhasing - Renovation Status: New

# IfcDoor: Door 23, VU-04
In: Esimene korrus
Type - OperationType: SINGLE_SWING_LEFT; ParameterTakesPrecedence: no; Sizeable: no
Type - Door Lining Properties - LiningDepth: 115 mm; LiningThickness: 40 mm; ThresholdDepth: 75 mm; ThresholdThickness: 12 mm; LiningOffset: 80 mm; ThresholdOffset: 120 mm
Type - Door Panel Properties - Panel 1 - PanelDepth: 40 mm; PanelOperation: SWINGING; PanelWidth: 1; PanelPosition: MIDDLE
OverallHeight: 2100 mm; OverallWidth: 900 mm; Classification: 1.10 IfcDoorStyle (uks) (RKAS BIM + ARCHICAD Classification)
Pset_DoorCommon - Reference: VU-04; ThermalTransmittance: 0; GlazingAreaFraction: 1.14117; IsExternal: yes
AR_Uks - 001_Nimetus: ühepoolne välisuks; 300_Tüüp: VU-04; 305_Ava_mõõt: 900x2 100; 310_Materjal: metall; 315_Avanemine: põõrdavanev - Parem ; ARCHICAD tüüp: Side Hung; 320_Klaas: ilma klaasita; 325_Helipidavus: nõudeid ei esitata; 330_Tulekindlus: nõudeid ei esitata; 335_Välispiire: yes; 340_Soojusläbivus: 0; 345_Päikesekiirgus_tegur: nõudeid ei esitata; 350_Klaaspakett: ilma klaasita; 355_Pindala: 1.89 m2; 360_Ratastooliga: no; 365_Isesulguv: yes; 370_Evakuatsiooniväljapääs: no; 375_Viimistlus_seest: MUDELIS: Wood - Pine Grained Horizontal; Wood - Pine Grained Horizontal; MÄRKUS:; 376_Viimistlus_väljast: MUDELIS: Wood - Pine Grained Horizontal; Wood - Pine Grained Horizontal; MÄRKUS:; 380_Lukustus: elektriline; 900_Tootja: Undefined; 905_Mudel: Undefined; 910_Tooteinfo: Undefined; 915_Kasutus-ja_hooldusjuhend: Undefined
AC_Pset_RenovationAndPhasing - Renovation Status: New

# IfcDoor: Door 23, VU-61 (kuulub hoidla komplekti)
In: Esimene korrus
Type - OperationType: SINGLE_SWING_RIGHT; ParameterTakesPrecedence: no; Sizeable: no
Type - Door Lining Properties - LiningDepth: 115 mm; LiningThickness: 40 mm; LiningOffset: 300 mm; CasingThickness: 50 mm; CasingDepth: 19 mm
Type - Door Panel Properties - Panel 1 - PanelDepth: 40 mm; PanelOperation: SWINGING; PanelWidth: 1; PanelPosition: MIDDLE
OverallHeight: 2000 mm; OverallWidth: 1300 mm; Classification: 1.10 IfcDoorStyle (uks) (RKAS BIM + ARCHICAD Classification)
Pset_DoorCommon - Reference: VU-61 (kuulub hoidla komplekti); ThermalTransmittance: 0; IsExternal: yes
AR_Uks - 001_Nimetus: Välisuks ühepoolne; 300_Tüüp: VU-61 (kuulub hoidla komplekti); 305_Ava_mõõt: 1 300x2 000; 310_Materjal: metall; 315_Avanemine: pöördavanev - Vasak ; ARCHICAD tüüp: Side Hung; 320_Klaas: ilma klaasita; 325_Helipidavus: nõudeid ei esitata; 330_Tulekindlus: nõudeid ei esitata; 335_Välispiire: yes; 340_Soojusläbivus: 0; 345_Päikesekiirgus_tegur: nõudeid ei esitata; 350_Klaaspakett: ilma klaasita; 355_Pindala: 2.6 m2; 360_Ratastooliga: no; 365_Isesulguv: no; 370_Evakuatsiooniväljapääs: no; 375_Viimistlus_seest: MUDELIS: Wood - Pine Grained Horizontal; Wood - Pine Grained Horizontal; MÄRKUS:; 376_Viimistlus_väljast: MUDELIS: Wood - Pine Grained Horizontal; Wood - Pine Grained Horizontal; MÄRKUS:; 380_Lukustus: elektriline; 900_Tootja: Undefined; 905_Mudel: Undefined; 910_Tooteinfo: Undefined; 915_Kasutus-ja_hooldusjuhend: Undefined
AC_Pset_RenovationAndPhasing - Renovation Status: New

# IfcDoor: Door 23, TU-01-11
In: Teine korrus
Type - OperationType: SINGLE_SWING_RIGHT; ParameterTakesPrecedence: no; Sizeable: no
Type - Door Lining Properties - LiningDepth: 115 mm; LiningThickness: 40 mm; ThresholdDepth: 75 mm; ThresholdThickness: 12 mm; LiningOffset: -1.38778e-14 mm; ThresholdOffset: -1.38778e-14 mm; CasingThickness: 50 mm; CasingDepth: 19 mm
Type - Door Panel Properties - Panel 1 - PanelDepth: 40 mm; PanelOperation: SWINGING; PanelWidth: 1; PanelPosition: MIDDLE
OverallHeight: 2100 mm; OverallWidth: 900 mm; Classification: 1.10 IfcDoorStyle (uks) (RKAS BIM + ARCHICAD Classification)
Pset_DoorCommon - Reference: TU-01-11; ThermalTransmittance: 0; IsExternal: no
AR_Uks - 001_Nimetus: tuletõkke siseuks; 300_Tüüp: TU-01-11; 305_Ava_mõõt: 900x2 100; 310_Materjal: metall; 315_Avanemine: pöördavanev - Vasak ; ARCHICAD tüüp: Side Hung; 320_Klaas: ilma klaasita; 325_Helipidavus: 30dB; 330_Tulekindlus: EI30; 335_Välispiire: no; 340_Soojusläbivus: 0; 345_Päikesekiirgus_tegur: nõueid ei esitata; 350_Klaaspakett: nõudeid ei esitata; 355_Pindala: 1.89 m2; 360_Ratastooliga: no; 365_Isesulguv: yes; 370_Evakuatsiooniväljapääs: yes; 375_Viimistlus_seest: MUDELIS: Metal - Steel; Metal - Steel; MÄRKUS:; 376_Viimistlus_väljast: MUDELIS: Metal - Steel; Metal - Steel; MÄRKUS:; 380_Lukustus: elektriline; 900_Tootja: Undefined; 905_Mudel: Undefined; 910_Tooteinfo: Undefined; 915_Kasutus-ja_hooldusjuhend: Undefined
AC_Pset_RenovationAndPhasing - Renovation Status: New

# IfcDoor: Door 23 (4)
Type - OperationType: SINGLE_SWING_RIGHT; ParameterTakesPrecedence: no; Sizeable: no
Type - Door Lining Properties - LiningDepth: 115 mm; LiningThickness: 40 mm; ThresholdDepth: 75 mm; ThresholdThickness: 12 mm; LiningOffset: -25 mm; ThresholdOffset: -25 mm; CasingThickness: 50 mm; CasingDepth: 19 mm
Type - Door Panel Properties - Panel 1 - PanelDepth: 40 mm; PanelOperation: SWINGING; PanelWidth: 1; PanelPosition: MIDDLE
OverallHeight: 2100 mm; Classification: 1.10 IfcDoorStyle (uks) (RKAS BIM + ARCHICAD Classification)
Pset_DoorCommon - ThermalTransmittance: 0; IsExternal: no
AR_Uks - 310_Materjal: metall; 320_Klaas: ilma klaasita; 335_Välispiire: no; 340_Soojusläbivus: 0; 345_Päikesekiirgus_tegur: nõudeid ei esitata; 360_Ratastooliga: no; 370_Evakuatsiooniväljapääs: yes; 380_Lukustus: elektriline; 900_Tootja: Undefined; 905_Mudel: Undefined; 910_Tooteinfo: Undefined; 915_Kasutus-ja_hooldusjuhend: Undefined
AC_Pset_RenovationAndPhasing - Renovation Status: New
Name | In | OverallWidth (mm) | Reference = 300_Tüüp | 001_Nimetus | 305_Ava_mõõt | 315_Avanemine | 325_Helipidavus | 330_Tulekindlus | 350_Klaaspakett | 355_Pindala (m2) | 365_Isesulguv | 375_Viimistlus_seest = 376_Viimistlus_väljast
SU-01-1 | Esimene korrus | 900 | SU-01-1 | Siseuks | 900x2 100 | Pöördavanev - Vasak ; ARCHICAD tüüp: Side Hung | Rw≥30dB | nõudeid ei esitata | nõudeid ei esitata | 1.89 | yes | MUDELIS: Wood - Pine Grained Horizontal; Wood - Pine Grained Horizontal; MÄRKUS:
2 x TU-01-10 | Teine korrus | 900 | TU-01-10 | tuletõkke siseuks | 900x2 100 | pöördavanev - Vasak ; ARCHICAD tüüp: Side Hung | 30dB | EI30 | ilma klaasita | 1.89 | yes | MUDELIS: Metal - Steel; Metal - Steel; MÄRKUS:
SU-01-2 | Teine korrus | 1000 | SU-01-2 | Siseuks | 1 000x2 100 | pöördavanev - Vasak ; ARCHICAD tüüp: Side Hung | Rw≥30dB | nõudeid ei esitata | ilma klaasita | 2.1 | no | MUDELIS: Metal - Steel; Metal - Steel; MÄRKUS:

# IfcDoor: Door 23 (8)
Type - OperationType: SINGLE_SWING_RIGHT; ParameterTakesPrecedence: no; Sizeable: no
Type - Door Lining Properties - LiningDepth: 115 mm; LiningThickness: 40 mm; ThresholdDepth: 75 mm; ThresholdThickness: 12 mm; LiningOffset: 0 mm; ThresholdOffset: 40 mm; CasingThickness: 50 mm; CasingDepth: 19 mm
Type - Door Panel Properties - Panel 1 - PanelDepth: 40 mm; PanelOperation: SWINGING; PanelWidth: 1; PanelPosition: MIDDLE
Classification: 1.10 IfcDoorStyle (uks) (RKAS BIM + ARCHICAD Classification)
Pset_DoorCommon - ThermalTransmittance: 0; IsExternal: no
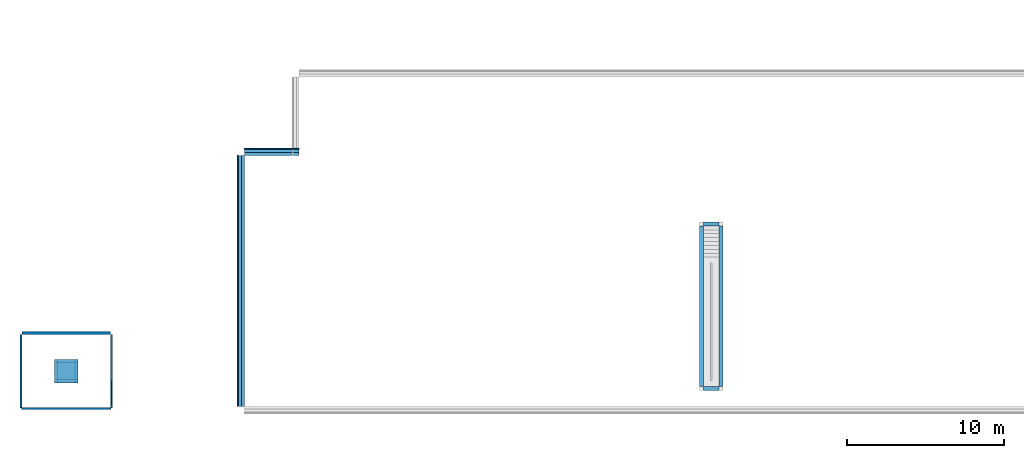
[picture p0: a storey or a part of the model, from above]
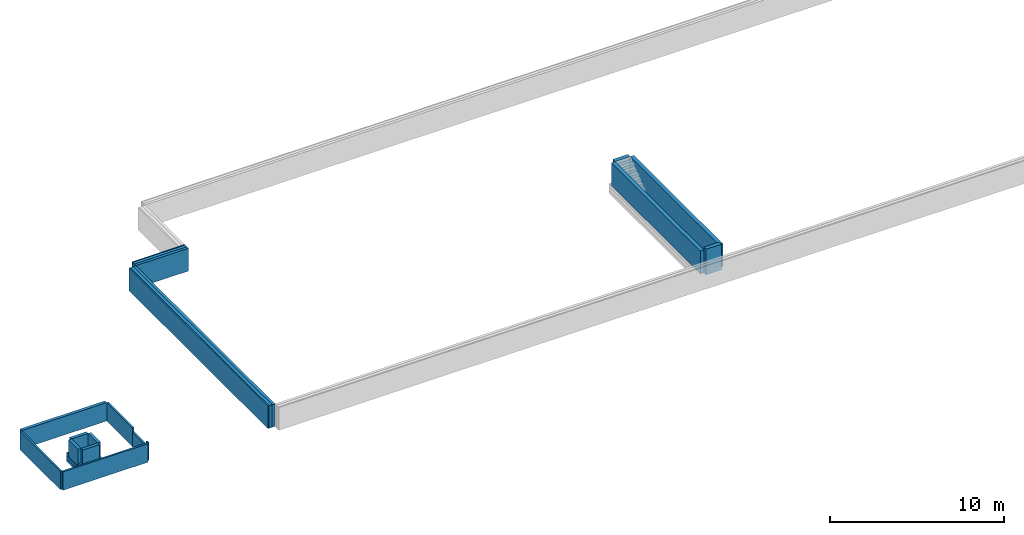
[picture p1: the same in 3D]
Properties of the parts of a building model (IFC2X3), part 2 of 4

# IfcDoor: Door 23 (8)
AR_Uks - 335_Välispiire: no; 340_Soojusläbivus: 0; 345_Päikesekiirgus_tegur: nõudeid ei esitata; 360_Ratastooliga: no; 900_Tootja: Undefined; 905_Mudel: Undefined; 910_Tooteinfo: Undefined; 915_Kasutus-ja_hooldusjuhend: Undefined
AC_Pset_RenovationAndPhasing - Renovation Status: New
Name | In | OverallHeight (mm) | OverallWidth (mm) | Reference = 300_Tüüp | 001_Nimetus | 305_Ava_mõõt | 310_Materjal | 315_Avanemine | 320_Klaas | 325_Helipidavus | 330_Tulekindlus | 350_Klaaspakett | 355_Pindala (m2) | 365_Isesulguv = 370_Evakuatsiooniväljapääs | 375_Viimistlus_seest = 376_Viimistlus_väljast | 380_Lukustus
TU-01-3 | Esimene korrus | 1650 | 1000 | TU-01-3 | tuletõkke siseuks | 1 000x1 650 | metall | Pöördavanev - Vasak ; ARCHICAD tüüp: Side Hung | ilma klaasita | 30 dB | EI60 | nõudeid ei esitata | 1.65 | yes | MUDELIS: Metal - Steel; Metal - Steel; MÄRKUS: | elektriline
SU-01-2 | Esimene korrus | 2100 | 1000 | SU-01-2 | Siseuks | 1 000x2 100 | metall | Pöördavanev - Vasak ; ARCHICAD tüüp: Side Hung | ilma klaasita | Rw≥30dB | nõudeid ei esitata | nõudeid ei esitata | 2.1 | yes | MUDELIS: Metal - Steel; Metal - Steel; MÄRKUS: | elektriline
2 x TU-01-7 | Esimene korrus | 2100 | 1000 | TU-01-7 | tuletõkke siseuks | 1 000x2 100 | metall | Pöördavanev - Vasak ; ARCHICAD tüüp: Side Hung | tuletõkkeklaas EI30 | 30 dB | EI30 | tuletõkkeklaas EI30 | 2.1 | yes | MUDELIS: Wood - Pine Grained Horizontal; Wood - Pine Grained Horizontal; MÄRKUS: | elektriline | Pset_DoorCommon - GlazingAreaFraction: 1.31837
SU-03-1 | Teine korrus | 2100 | 700 | SU-03-1 | siseuks | 700x2 100 | täisklaasuks | pöördavanev - Vasak ; ARCHICAD tüüp: Side Hung | toonitud klaas | nõudeid ei esitata | nõudeid ei esitata | 1xklaas | 1.47 | no | MUDELIS: Metal - Steel; Metal - Steel; MÄRKUS: | lukustus puudub
SU-02-1 | Teine korrus | 2100 | 800 | SU-02-1 | siseuks | 800x2 100 | puit | pöördavanev - Vasak ; ARCHICAD tüüp: Side Hung | ilma klaasita | Rw≥30dB | nõudeid ei esitata | ilma klaasita | 1.68 | yes | MUDELIS: Wood - Pine Grained Horizontal; Wood - Pine Grained Horizontal; MÄRKUS: | mehaaniline
SU-02-3 | Teine korrus | 2100 | 1000 | SU-02-3 | Siseuks | 1 000x2 100 | puit | pööravanev - Vasak ; ARCHICAD tüüp: Side Hung | ilma klaasita | Rw≥30dB | nõudeid ei esitata | ilma klaasita | 2.1 | yes | MUDELIS: Metal - Steel; Metal - Steel; MÄRKUS: | elektriline
SU-02-1 | Teine korrus | 2100 | 800 | SU-02-1 | siseuks | 800x2 100 | puit | pöördavanev - Vasak ; ARCHICAD tüüp: Side Hung | ilma klaasita | Rw≥30dB | nõudeid ei esitata | ilma klaasita | 1.68 | yes | MUDELIS: Metal - Steel; Metal - Steel; MÄRKUS: | mehaaniline

# IfcDoor: Door 23 (7)
Type - OperationType: SINGLE_SWING_RIGHT; ParameterTakesPrecedence: no; Sizeable: no
Type - Door Lining Properties - LiningDepth: 115 mm; LiningThickness: 40 mm; ThresholdDepth: 75 mm; ThresholdThickness: 12 mm; LiningOffset: 115 mm; ThresholdOffset: 115 mm; CasingThickness: 50 mm; CasingDepth: 19 mm
Type - Door Panel Properties - Panel 1 - PanelDepth: 40 mm; PanelOperation: SWINGING; PanelWidth: 1; PanelPosition: MIDDLE
OverallHeight: 2100 mm; Classification: 1.10 IfcDoorStyle (uks) (RKAS BIM + ARCHICAD Classification)
Pset_DoorCommon - ThermalTransmittance: 0; IsExternal: no
AR_Uks - 320_Klaas: ilma klaasita; 330_Tulekindlus: nõudeid ei esitata; 335_Välispiire: no; 340_Soojusläbivus: 0; 345_Päikesekiirgus_tegur: nõudeid ei esitata; 365_Isesulguv: yes; 370_Evakuatsiooniväljapääs: yes; 900_Tootja: Undefined; 905_Mudel: Undefined; 910_Tooteinfo: Undefined; 915_Kasutus-ja_hooldusjuhend: Undefined
AC_Pset_RenovationAndPhasing - Renovation Status: New
Name | In | OverallWidth (mm) | Reference = 300_Tüüp | 001_Nimetus | 305_Ava_mõõt | 310_Materjal | 315_Avanemine | 325_Helipidavus | 350_Klaaspakett | 355_Pindala (m2) | 360_Ratastooliga | 375_Viimistlus_seest = 376_Viimistlus_väljast | 380_Lukustus
SU-01-1 | Esimene korrus | 900 | SU-01-1 | Siseuks | 900x2 100 | metall | Pöördavanev - Vasak ; ARCHICAD tüüp: Side Hung | Rw≥30dB | nõudeid ei esitata | 1.89 | yes | MUDELIS: Metal - Steel; Metal - Steel; MÄRKUS: | elektriline
SU-01-2 | Esimene korrus | 1000 | SU-01-2 | Siseuks | 1 000x2 100 | metall | Pöördavanev - Vasak ; ARCHICAD tüüp: Side Hung | Rw≥30dB | nõudeid ei esitata | 2.1 | no | MUDELIS: Metal - Steel; Metal - Steel; MÄRKUS: | elektriline
SU-02-1 | Teine korrus | 800 | SU-02-1 | siseuks | 800x2 100 |  | pöördavanev - Vasak ; ARCHICAD tüüp: Side Hung | Rw≥30dB | ilma klaasita | 1.68 | no | MUDELIS: Wood - Pine Grained Horizontal; Wood - Pine Grained Horizontal; MÄRKUS: | mehaaniline
4 x SU-02-2 | Teine korrus | 900 | SU-02-2 | Siseuks | 900x2 100 | puit | põõrdavanev - Vasak ; ARCHICAD tüüp: Side Hung | Rw≥35dB | ilma klaasita | 1.89 | no | MUDELIS: Metal - Steel; Metal - Steel; MÄRKUS: | mehaaniline

# IfcDoor: Door 23 (3)
Type - OperationType: SINGLE_SWING_RIGHT; ParameterTakesPrecedence: no; Sizeable: no
Type - Door Lining Properties - LiningDepth: 115 mm; LiningThickness: 40 mm; ThresholdDepth: 75 mm; ThresholdThickness: 12 mm; LiningOffset: 140 mm; ThresholdOffset: 180 mm; CasingThickness: 50 mm; CasingDepth: 19 mm
Type - Door Panel Properties - Panel 1 - PanelDepth: 40 mm; PanelOperation: SWINGING; PanelWidth: 1; PanelPosition: MIDDLE
OverallHeight: 2100 mm; Classification: 1.10 IfcDoorStyle (uks) (RKAS BIM + ARCHICAD Classification)
Pset_DoorCommon - ThermalTransmittance: 0; IsExternal: no
AR_Uks - 001_Nimetus: Siseuks; 320_Klaas: ilma klaasita; 330_Tulekindlus: nõudeid ei esitata; 335_Välispiire: no; 340_Soojusläbivus: 0; 345_Päikesekiirgus_tegur: nõudeid ei esitata; 360_Ratastooliga: no; 365_Isesulguv: yes; 370_Evakuatsiooniväljapääs: yes; 375_Viimistlus_seest: MUDELIS: Metal - Steel; Metal - Steel; MÄRKUS:; 376_Viimistlus_väljast: MUDELIS: Metal - Steel; Metal - Steel; MÄRKUS:; 380_Lukustus: mehaaniline; 900_Tootja: Undefined; 905_Mudel: Undefined; 910_Tooteinfo: Undefined; 915_Kasutus-ja_hooldusjuhend: Undefined
AC_Pset_RenovationAndPhasing - Renovation Status: New
Name | In | OverallWidth (mm) | Reference = 300_Tüüp | 305_Ava_mõõt | 310_Materjal | 315_Avanemine | 325_Helipidavus | 350_Klaaspakett | 355_Pindala (m2)
SU-01-5 | Esimene korrus | 800 | SU-01-5 | 800x2 100 | metall | Pöördavanev - Vasak ; ARCHICAD tüüp: Side Hung | Rw≥30dB | nõudeid ei esitata | 1.68
SU-01-5 | Teine korrus | 800 | SU-01-5 | 800x2 100 | metall | põõrdavanev - Vasak ; ARCHICAD tüüp: Side Hung | nõudeid ei esitata | ilma klaasita | 1.68
SU-02-2 | Teine korrus | 900 | SU-02-2 | 900x2 100 | puit | põõrdavanev - Vasak ; ARCHICAD tüüp: Side Hung | Rw≥35dB | ilma klaasita | 1.89

# IfcDoor: Door 23 (2)
Type - OperationType: SINGLE_SWING_RIGHT; ParameterTakesPrecedence: no; Sizeable: no
Type - Door Lining Properties - LiningDepth: 115 mm; LiningThickness: 40 mm; ThresholdDepth: 75 mm; ThresholdThickness: 12 mm; LiningOffset: 190 mm; ThresholdOffset: 230 mm; CasingThickness: 50 mm; CasingDepth: 19 mm
Type - Door Panel Properties - Panel 1 - PanelDepth: 40 mm; PanelOperation: SWINGING; PanelWidth: 1; PanelPosition: MIDDLE
OverallHeight: 2100 mm; Classification: 1.10 IfcDoorStyle (uks) (RKAS BIM + ARCHICAD Classification)
Pset_DoorCommon - ThermalTransmittance: 0; IsExternal: no
AR_Uks - 001_Nimetus: Siseuks; 310_Materjal: metall; 320_Klaas: ilma klaasita; 330_Tulekindlus: nõudeid ei esitata; 335_Välispiire: no; 340_Soojusläbivus: 0; 345_Päikesekiirgus_tegur: nõudeid ei esitata; 360_Ratastooliga: no; 375_Viimistlus_seest: MUDELIS: Metal - Steel; Metal - Steel; MÄRKUS:; 376_Viimistlus_väljast: MUDELIS: Metal - Steel; Metal - Steel; MÄRKUS:; 380_Lukustus: elektriline; 900_Tootja: Undefined; 905_Mudel: Undefined; 910_Tooteinfo: Undefined; 915_Kasutus-ja_hooldusjuhend: Undefined
AC_Pset_RenovationAndPhasing - Renovation Status: New
Name | In | OverallWidth (mm) | Reference = 300_Tüüp | 305_Ava_mõõt | 315_Avanemine | 325_Helipidavus | 350_Klaaspakett | 355_Pindala (m2) | 365_Isesulguv = 370_Evakuatsiooniväljapääs
SU-01-6 | Esimene korrus | 800 | SU-01-6 | 800x2 100 | Pöördavanev - Vasak ; ARCHICAD tüüp: Side Hung | nõudeid ei esitata | nõudeid ei esitata | 1.68 | yes
SU-01-1 | Teine korrus | 900 | SU-01-1 | 900x2 100 | põõrdavanev - Vasak ; ARCHICAD tüüp: Side Hung | Rw≥30dB | ilma klaasita | 1.89 | no

# IfcDoor: Door 23 (4)
In: Esimene korrus
Type - OperationType: SINGLE_SWING_RIGHT; ParameterTakesPrecedence: no; Sizeable: no
Type - Door Lining Properties - LiningDepth: 115 mm; LiningThickness: 40 mm; ThresholdDepth: 75 mm; ThresholdThickness: 12 mm; LiningOffset: 235 mm; ThresholdOffset: 235 mm; CasingThickness: 50 mm; CasingDepth: 19 mm
Type - Door Panel Properties - Panel 1 - PanelDepth: 40 mm; PanelOperation: SWINGING; PanelWidth: 1; PanelPosition: MIDDLE
OverallHeight: 2100 mm; OverallWidth: 900 mm; Classification: 1.10 IfcDoorStyle (uks) (RKAS BIM + ARCHICAD Classification)
Pset_DoorCommon - Reference: SU-01-1; ThermalTransmittance: 0; IsExternal: no
AR_Uks - 001_Nimetus: Siseuks; 300_Tüüp: SU-01-1; 305_Ava_mõõt: 900x2 100; 310_Materjal: metall; 315_Avanemine: Pöördavanev - Vasak ; ARCHICAD tüüp: Side Hung; 320_Klaas: ilma klaasita; 325_Helipidavus: Rw≥30dB; 330_Tulekindlus: nõudeid ei esitata; 335_Välispiire: no; 340_Soojusläbivus: 0; 345_Päikesekiirgus_tegur: nõudeid ei esitata; 350_Klaaspakett: nõudeid ei esitata; 355_Pindala: 1.89 m2; 360_Ratastooliga: no; 365_Isesulguv: yes; 370_Evakuatsiooniväljapääs: yes; 375_Viimistlus_seest: MUDELIS: Metal - Steel; Metal - Steel; MÄRKUS:; 376_Viimistlus_väljast: MUDELIS: Metal - Steel; Metal - Steel; MÄRKUS:; 380_Lukustus: elektriline; 900_Tootja: Undefined; 905_Mudel: Undefined; 910_Tooteinfo: Undefined; 915_Kasutus-ja_hooldusjuhend: Undefined
AC_Pset_RenovationAndPhasing - Renovation Status: New

# IfcDoor: Door 23, TU-01-12
In: Esimene korrus
Type - OperationType: SINGLE_SWING_RIGHT; ParameterTakesPrecedence: no; Sizeable: no
Type - Door Lining Properties - LiningDepth: 115 mm; LiningThickness: 40 mm; ThresholdDepth: 75 mm; ThresholdThickness: 12 mm; LiningOffset: 240 mm; ThresholdOffset: 280 mm; CasingThickness: 50 mm; CasingDepth: 19 mm
Type - Door Panel Properties - Panel 1 - PanelDepth: 40 mm; PanelOperation: SWINGING; PanelWidth: 1; PanelPosition: MIDDLE
OverallHeight: 2500 mm; OverallWidth: 1000 mm; Classification: 1.10 IfcDoorStyle (uks) (RKAS BIM + ARCHICAD Classification)
Pset_DoorCommon - Reference: TU-01-12; ThermalTransmittance: 0; IsExternal: no
AR_Uks - 001_Nimetus: tuletõkke siseuks; 300_Tüüp: TU-01-12; 305_Ava_mõõt: 1 000x2 500; 310_Materjal: metall; 315_Avanemine: Pöördavanev - Vasak ; ARCHICAD tüüp: Side Hung; 320_Klaas: ilma klaasita; 325_Helipidavus: 30 dB; 330_Tulekindlus: EI60; 335_Välispiire: no; 340_Soojusläbivus: 0; 345_Päikesekiirgus_tegur: nõudeid ei esitata; 350_Klaaspakett: nõudeid ei esitata; 355_Pindala: 2.5 m2; 360_Ratastooliga: no; 365_Isesulguv: yes; 370_Evakuatsiooniväljapääs: yes; 375_Viimistlus_seest: MUDELIS: Metal - Steel; Metal - Steel; MÄRKUS:; 376_Viimistlus_väljast: MUDELIS: Metal - Steel; Metal - Steel; MÄRKUS:; 380_Lukustus: elektriline; 900_Tootja: Undefined; 905_Mudel: Undefined; 910_Tooteinfo: Undefined; 915_Kasutus-ja_hooldusjuhend: Undefined
AC_Pset_RenovationAndPhasing - Renovation Status: New

# IfcDoor: Door 23, SU-01-7
In: Teine korrus
Type - OperationType: SINGLE_SWING_RIGHT; ParameterTakesPrecedence: no; Sizeable: no
Type - Door Lining Properties - LiningDepth: 115 mm; LiningThickness: 40 mm; ThresholdDepth: 75 mm; ThresholdThickness: 12 mm; LiningOffset: 80 mm; ThresholdOffset: 120 mm; CasingThickness: 50 mm; CasingDepth: 19 mm
Type - Door Panel Properties - Panel 1 - PanelDepth: 40 mm; PanelOperation: SWINGING; PanelWidth: 1; PanelPosition: MIDDLE
OverallHeight: 2100 mm; OverallWidth: 900 mm; Classification: 1.10 IfcDoorStyle (uks) (RKAS BIM + ARCHICAD Classification)
AR_Uks - 340_Soojusläbivus: 0; 001_Nimetus: Siseuks; 300_Tüüp: SU-01-7; 305_Ava_mõõt: 900x2 100; 310_Materjal: metall; 315_Avanemine: pöördavanev - Vasak ; ARCHICAD tüüp: Side Hung; 320_Klaas: ilma klaasita; 325_Helipidavus: Rw≥30dB; 330_Tulekindlus: nõudeid ei esitata; 335_Välispiire: no; 345_Päikesekiirgus_tegur: nõudeid ei esitata; 350_Klaaspakett: ilma klaasita; 355_Pindala: 1.89 m2; 360_Ratastooliga: no; 365_Isesulguv: no; 370_Evakuatsiooniväljapääs: no; 375_Viimistlus_seest: MUDELIS: Metal - Steel; Metal - Steel; MÄRKUS:; 376_Viimistlus_väljast: MUDELIS: Metal - Steel; Metal - Steel; MÄRKUS:; 380_Lukustus: mehaaniline; 900_Tootja: Undefined; 905_Mudel: Undefined; 910_Tooteinfo: Undefined; 915_Kasutus-ja_hooldusjuhend: Undefined
Pset_DoorCommon - Reference: SU-01-7; ThermalTransmittance: 0; IsExternal: no
AC_Pset_RenovationAndPhasing - Renovation Status: New

# IfcDoor: Door with Sidelight on Side 2 23 (13)
In: Teine korrus
Type - ParameterTakesPrecedence: no; Sizeable: no
Type - Door Panel Properties - Panel 1 - PanelDepth: 40 mm; PanelOperation: SWINGING; PanelWidth: 1; PanelPosition: MIDDLE
OverallHeight: 2100 mm; OverallWidth: 1500 mm; Classification: 1.10 IfcDoorStyle (uks) (RKAS BIM + ARCHICAD Classification)
AR_Uks - 340_Soojusläbivus: 0; 001_Nimetus: Siseuks külgaknaga; 300_Tüüp: SU-02-5; 305_Ava_mõõt: 1 500x2 100; 310_Materjal: puit; 320_Klaas: külgaken 2xklaas; 325_Helipidavus: Rw≥30dB; 330_Tulekindlus: nõudeid ei esitata; 335_Välispiire: no; 345_Päikesekiirgus_tegur: nõudeid ei esitata; 350_Klaaspakett: 2k 6+6; 355_Pindala: 3.15 m2; 360_Ratastooliga: no; 365_Isesulguv: yes; 370_Evakuatsiooniväljapääs: yes; 375_Viimistlus_seest: MUDELIS: Wood - Pine Grained Horizontal; Wood - Pine Grained Horizontal; MÄRKUS:; 376_Viimistlus_väljast: MUDELIS: Wood - Pine Grained Horizontal; Wood - Pine Grained Horizontal; MÄRKUS:; 380_Lukustus: elektriline; 900_Tootja: Undefined; 905_Mudel: Undefined; 910_Tooteinfo: Undefined; 915_Kasutus-ja_hooldusjuhend: Undefined
Pset_DoorCommon - Reference: SU-02-5; ThermalTransmittance: 0; GlazingAreaFraction: 1.0504; IsExternal: no
AC_Pset_RenovationAndPhasing - Renovation Status: New
Name | 315_Avanemine
4 x SU-02-5 | põõrdavanev - Vasak ; ARCHICAD tüüp: Side Hung
9 x SU-02-5 | põõrdavanev - Parem ; ARCHICAD tüüp: Side Hung

# IfcDoor: Door with Transom 23, VU-07
In: Esimene korrus
Type - OperationType: SINGLE_SWING_LEFT; ParameterTakesPrecedence: no; Sizeable: no
Type - Door Lining Properties - LiningDepth: 115 mm; LiningThickness: 40 mm; ThresholdDepth: 75 mm; ThresholdThickness: 12 mm; TransomThickness: 40 mm; TransomOffset: 2100 mm; LiningOffset: -70 mm; ThresholdOffset: -30 mm
Type - Door Panel Properties - Panel 1 - PanelDepth: 40 mm; PanelOperation: SWINGING; PanelWidth: 1; PanelPosition: MIDDLE
OverallHeight: 2600 mm; OverallWidth: 1000 mm; Classification: 1.10 IfcDoorStyle (uks) (RKAS BIM + ARCHICAD Classification)
Pset_DoorCommon - Reference: VU-07; ThermalTransmittance: 0; GlazingAreaFraction: 1.73453; IsExternal: yes
AR_Uks - 001_Nimetus: ühepoolne välisuks + aken; 300_Tüüp: VU-07; 305_Ava_mõõt: 1 000x2 600; 310_Materjal: metall; 315_Avanemine: pöördavanev - Parem ; ARCHICAD tüüp: Side Hung; 320_Klaas: 3xklaaspakett; 325_Helipidavus: Rw≥35dB; 330_Tulekindlus: nõudeid ei esitata; 335_Välispiire: yes; 340_Soojusläbivus: 1.1; 345_Päikesekiirgus_tegur: 0,4; 350_Klaaspakett: 3k (6+4+10); 355_Pindala: 2.6 m2; 360_Ratastooliga: yes; 365_Isesulguv: yes; 370_Evakuatsiooniväljapääs: yes; 375_Viimistlus_seest: MUDELIS: Metal - Stainless Steel; Metal - Stainless Steel; MÄRKUS:; 376_Viimistlus_väljast: MUDELIS: Metal - Stainless Steel; Metal - Stainless Steel; MÄRKUS:; 380_Lukustus: elektriline; 900_Tootja: Undefined; 905_Mudel: Undefined; 910_Tooteinfo: Undefined; 915_Kasutus-ja_hooldusjuhend: Undefined
AC_Pset_RenovationAndPhasing - Renovation Status: New

# IfcDoor: Door with Transom 23, VU-06
In: Esimene korrus
Type - OperationType: SINGLE_SWING_LEFT; ParameterTakesPrecedence: no; Sizeable: no
Type - Door Lining Properties - LiningDepth: 115 mm; LiningThickness: 40 mm; ThresholdDepth: 75 mm; ThresholdThickness: 12 mm; TransomThickness: 40 mm; TransomOffset: 2100 mm; LiningOffset: -80 mm; ThresholdOffset: -40 mm
Type - Door Panel Properties - Panel 1 - PanelDepth: 40 mm; PanelOperation: SWINGING; PanelWidth: 1; PanelPosition: MIDDLE
OverallHeight: 2600 mm; OverallWidth: 1000 mm; Classification: 1.10 IfcDoorStyle (uks) (RKAS BIM + ARCHICAD Classification)
Pset_DoorCommon - Reference: VU-06; ThermalTransmittance: 0; GlazingAreaFraction: 0.3864; IsExternal: yes
AR_Uks - 001_Nimetus: Ühepoolne välisuks + aken; 300_Tüüp: VU-06; 305_Ava_mõõt: 1 000x2 600; 310_Materjal: metall; 315_Avanemine: pöördavanev - Parem ; ARCHICAD tüüp: Side Hung; 320_Klaas: uks ilma klaasita + aken 3xklaaspakett; 325_Helipidavus: Rw≥35dB; 330_Tulekindlus: nõudeid ei esitata; 335_Välispiire: yes; 340_Soojusläbivus: 1.1; 345_Päikesekiirgus_tegur: 0,4; 350_Klaaspakett: 3k (6+4+10); 355_Pindala: 2.6 m2; 360_Ratastooliga: no; 365_Isesulguv: yes; 370_Evakuatsiooniväljapääs: yes; 375_Viimistlus_seest: MUDELIS: Mtl-Aluminium; Mtl-Aluminium; MÄRKUS:; 376_Viimistlus_väljast: MUDELIS: Mtl-Aluminium; Mtl-Aluminium; MÄRKUS:; 380_Lukustus: elektriline; 900_Tootja: Undefined; 905_Mudel: Undefined; 910_Tooteinfo: Undefined; 915_Kasutus-ja_hooldusjuhend: Undefined
AC_Pset_RenovationAndPhasing - Renovation Status: New

# IfcDoor: Door with Transom 23 (2)
In: Esimene korrus
Type - OperationType: SINGLE_SWING_RIGHT; ParameterTakesPrecedence: no; Sizeable: no
Type - Door Lining Properties - LiningDepth: 115 mm; LiningThickness: 40 mm; ThresholdDepth: 75 mm; ThresholdThickness: 12 mm; TransomThickness: 40 mm; TransomOffset: 2100 mm; LiningOffset: -80 mm; ThresholdOffset: -40 mm; CasingThickness: 50 mm; CasingDepth: 19 mm
Type - Door Panel Properties - Panel 1 - PanelDepth: 40 mm; PanelOperation: SWINGING; PanelWidth: 1; PanelPosition: MIDDLE
OverallHeight: 2600 mm; OverallWidth: 900 mm; Classification: 1.10 IfcDoorStyle (uks) (RKAS BIM + ARCHICAD Classification)
Pset_DoorCommon - Reference: VU-05; ThermalTransmittance: 0; GlazingAreaFraction: 0.3444; IsExternal: yes
AR_Uks - 001_Nimetus: ühepoolne välisuks + aken; 300_Tüüp: VU-05; 305_Ava_mõõt: 900x2 600; 310_Materjal: metall; 315_Avanemine: põõrdavanev - Vasak ; ARCHICAD tüüp: Side Hung; 320_Klaas: uks ilma klaasita + aken 3xklaaspakett; 325_Helipidavus: Rw≥35dB; 330_Tulekindlus: nõudeid ei esitata; 335_Välispiire: yes; 340_Soojusläbivus: 1.1; 345_Päikesekiirgus_tegur: 0,4; 350_Klaaspakett: 3k (6+4+10); 355_Pindala: 2.34 m2; 360_Ratastooliga: no; 365_Isesulguv: yes; 370_Evakuatsiooniväljapääs: yes; 375_Viimistlus_seest: MUDELIS: Paint - Glossy White; Paint - Glossy White; MÄRKUS:; 376_Viimistlus_väljast: MUDELIS: Paint - Glossy White; Paint - Glossy White; MÄRKUS:; 380_Lukustus: elektriline; 900_Tootja: Undefined; 905_Mudel: Undefined; 910_Tooteinfo: Undefined; 915_Kasutus-ja_hooldusjuhend: Undefined
AC_Pset_RenovationAndPhasing - Renovation Status: New

# IfcDoor: Double Door 23, TU-01-13
In: Esimene korrus
Type - OperationType: DOUBLE_DOOR_SINGLE_SWING; ParameterTakesPrecedence: no; Sizeable: no
Type - Door Lining Properties - LiningDepth: 115 mm; LiningThickness: 40 mm; ThresholdDepth: 75 mm; ThresholdThickness: 12 mm; LiningOffset: 0 mm; ThresholdOffset: 40 mm; CasingThickness: 50 mm; CasingDepth: 19 mm
Type - Door Panel Properties - Panel 1 - PanelDepth: 40 mm; PanelOperation: SWINGING; PanelWidth: 0.506977; PanelPosition: RIGHT
Type - Door Panel Properties - Panel 2 - PanelDepth: 40 mm; PanelOperation: SWINGING; PanelWidth: 0.506977; PanelPosition: LEFT
OverallHeight: 2400 mm; OverallWidth: 1800 mm; Classification: 1.10 IfcDoorStyle (uks) (RKAS BIM + ARCHICAD Classification)
Pset_DoorCommon - Reference: TU-01-13; ThermalTransmittance: 0; IsExternal: no
AR_Uks - 001_Nimetus: tuletõkke siseuks kahepoolne; 300_Tüüp: TU-01-13; 305_Ava_mõõt: 1 800x2 400; 310_Materjal: metall; 315_Avanemine: Pöördavanev ; ARCHICAD tüüp: Side Hung; 320_Klaas: ilma klaasita; 325_Helipidavus: 30 dB; 330_Tulekindlus: EI60; 335_Välispiire: no; 340_Soojusläbivus: 0; 345_Päikesekiirgus_tegur: nõudeid ei esitata; 350_Klaaspakett: ilma klaasita; 355_Pindala: 4.32 m2; 360_Ratastooliga: yes; 365_Isesulguv: yes; 370_Evakuatsiooniväljapääs: no; 375_Viimistlus_seest: MUDELIS: Wood - Pine Grained Horizontal; Wood - Pine Grained Horizontal; MÄRKUS:; 376_Viimistlus_väljast: MUDELIS: Wood - Pine Grained Horizontal; Wood - Pine Grained Horizontal; MÄRKUS:; 380_Lukustus: elektriline; 900_Tootja: Undefined; 905_Mudel: Undefined; 910_Tooteinfo: Undefined; 915_Kasutus-ja_hooldusjuhend: Undefined
AC_Pset_RenovationAndPhasing - Renovation Status: New

# IfcDoor: Double Door 23, TU-01-13
In: Esimene korrus
Type - OperationType: DOUBLE_DOOR_SINGLE_SWING; ParameterTakesPrecedence: no; Sizeable: no
Type - Door Lining Properties - LiningDepth: 115 mm; LiningThickness: 40 mm; ThresholdDepth: 75 mm; ThresholdThickness: 12 mm; LiningOffset: 115 mm; ThresholdOffset: 115 mm; CasingThickness: 50 mm; CasingDepth: 19 mm
Type - Door Panel Properties - Panel 1 - PanelDepth: 40 mm; PanelOperation: SWINGING; PanelWidth: 0.506977; PanelPosition: RIGHT
Type - Door Panel Properties - Panel 2 - PanelDepth: 40 mm; PanelOperation: SWINGING; PanelWidth: 0.506977; PanelPosition: LEFT
OverallHeight: 2400 mm; OverallWidth: 1800 mm; Classification: 1.10 IfcDoorStyle (uks) (RKAS BIM + ARCHICAD Classification)
Pset_DoorCommon - Reference: TU-01-13; ThermalTransmittance: 0; IsExternal: no
AR_Uks - 001_Nimetus: tuletõkke siseuks kahepoolne; 300_Tüüp: TU-01-13; 305_Ava_mõõt: 1 800x2 400; 310_Materjal: metall; 315_Avanemine: Pöördavanev; ARCHICAD tüüp: Side Hung; 320_Klaas: ilma klaasita; 325_Helipidavus: 30 dB; 330_Tulekindlus: EI60; 335_Välispiire: no; 340_Soojusläbivus: 0; 345_Päikesekiirgus_tegur: nõudeid ei esitata; 350_Klaaspakett: ilma klaasita; 355_Pindala: 4.32 m2; 360_Ratastooliga: no; 365_Isesulguv: yes; 370_Evakuatsiooniväljapääs: yes; 375_Viimistlus_seest: MUDELIS: Wood - Pine Grained Horizontal; Wood - Pine Grained Horizontal; MÄRKUS:; 376_Viimistlus_väljast: MUDELIS: Wood - Pine Grained Horizontal; Wood - Pine Grained Horizontal; MÄRKUS:; 380_Lukustus: elektriline; 900_Tootja: Undefined; 905_Mudel: Undefined; 910_Tooteinfo: Undefined; 915_Kasutus-ja_hooldusjuhend: Undefined
AC_Pset_RenovationAndPhasing - Renovation Status: New

# IfcDoor: Double Door Asymmetric 23, VU-21
In: Esimene korrus
Type - OperationType: DOUBLE_DOOR_SINGLE_SWING; ParameterTakesPrecedence: no; Sizeable: no
Type - Door Lining Properties - LiningDepth: 115 mm; LiningThickness: 40 mm; LiningOffset: 0 mm; CasingThickness: 50 mm; CasingDepth: 19 mm
Type - Door Panel Properties - Panel 1 - PanelDepth: 40 mm; PanelOperation: SWINGING; PanelWidth: 0.608163; PanelPosition: LEFT
Type - Door Panel Properties - Panel 2 - PanelDepth: 40 mm; PanelOperation: SWINGING; PanelWidth: 0.408163; PanelPosition: RIGHT
OverallHeight: 2100 mm; OverallWidth: 1550 mm; Classification: 1.10 IfcDoorStyle (uks) (RKAS BIM + ARCHICAD Classification)
Pset_DoorCommon - Reference: VU-21; ThermalTransmittance: 0; GlazingAreaFraction: 1.93857; IsExternal: yes
AR_Uks - 001_Nimetus: Välisuks kahepoolne; 300_Tüüp: VU-21; 305_Ava_mõõt: 1 550x2 100; 310_Materjal: metall; 315_Avanemine: pöördavanev; ARCHICAD tüüp: Side Hung; 320_Klaas: 2xklaaspakett; 325_Helipidavus: nõudeid ei esitata; 330_Tulekindlus: nõudeid ei esitata; 335_Välispiire: yes; 340_Soojusläbivus: 0; 345_Päikesekiirgus_tegur: nõudeid ei esitata; 350_Klaaspakett: 2k 4+10; 355_Pindala: 3.255 m2; 360_Ratastooliga: no; 365_Isesulguv: yes; 370_Evakuatsiooniväljapääs: no; 375_Viimistlus_seest: MUDELIS: Wood - Pine Grained Horizontal; Wood - Pine Grained Horizontal; MÄRKUS:; 376_Viimistlus_väljast: MUDELIS: Wood - Pine Grained Horizontal; Wood - Pine Grained Horizontal; MÄRKUS:; 380_Lukustus: elektriline; 900_Tootja: Undefined; 905_Mudel: Undefined; 910_Tooteinfo: Undefined; 915_Kasutus-ja_hooldusjuhend: Undefined
AC_Pset_RenovationAndPhasing - Renovation Status: New

# IfcDoor: Double Door Asymmetric 23, SU-02-6
In: Teine korrus
Type - OperationType: DOUBLE_DOOR_SINGLE_SWING; ParameterTakesPrecedence: no; Sizeable: no
Type - Door Lining Properties - LiningDepth: 115 mm; LiningThickness: 40 mm; ThresholdDepth: 75 mm; ThresholdThickness: 12 mm; LiningOffset: -25 mm; ThresholdOffset: -25 mm; CasingThickness: 50 mm; CasingDepth: 19 mm
Type - Door Panel Properties - Panel 1 - PanelDepth: 40 mm; PanelOperation: SWINGING; PanelWidth: 0.753571; PanelPosition: RIGHT
Type - Door Panel Properties - Panel 2 - PanelDepth: 40 mm; PanelOperation: SWINGING; PanelWidth: 0.267857; PanelPosition: LEFT
OverallHeight: 2100 mm; OverallWidth: 1200 mm; Classification: 1.10 IfcDoorStyle (uks) (RKAS BIM + ARCHICAD Classification)
Pset_DoorCommon - Reference: SU-02-6; ThermalTransmittance: 0; GlazingAreaFraction: 1.31837; IsExternal: no
AR_Uks - 001_Nimetus: kahepoolne siseuks; 300_Tüüp: SU-02-6; 305_Ava_mõõt: 1 200x2 100; 310_Materjal: puit; 315_Avanemine: pöördavanev - Parem ; ARCHICAD tüüp: Side Hung; 320_Klaas: külgaken 2xklaas; 325_Helipidavus: Rw≥30dB; 330_Tulekindlus: nõudeid ei esitata; 335_Välispiire: no; 340_Soojusläbivus: 0; 345_Päikesekiirgus_tegur: nõudeid ei esitata; 350_Klaaspakett: 2xklaas; 355_Pindala: 2.52 m2; 360_Ratastooliga: no; 365_Isesulguv: yes; 370_Evakuatsiooniväljapääs: yes; 375_Viimistlus_seest: MUDELIS: Wood - Pine Grained Horizontal; Wood - Pine Grained Horizontal; MÄRKUS:; 376_Viimistlus_väljast: MUDELIS: Wood - Pine Grained Horizontal; Wood - Pine Grained Horizontal; MÄRKUS:; 380_Lukustus: elektriline; 900_Tootja: Undefined; 905_Mudel: Undefined; 910_Tooteinfo: Undefined; 915_Kasutus-ja_hooldusjuhend: Undefined
AC_Pset_RenovationAndPhasing - Renovation Status: New

# IfcDoor: Double Door Asymmetric 23 (2)
Type - OperationType: DOUBLE_DOOR_SINGLE_SWING; ParameterTakesPrecedence: no; Sizeable: no
Type - Door Lining Properties - LiningDepth: 115 mm; LiningThickness: 40 mm; ThresholdDepth: 75 mm; ThresholdThickness: 12 mm; LiningOffset: -75 mm; ThresholdOffset: -75 mm; CasingThickness: 50 mm; CasingDepth: 19 mm
Type - Door Panel Properties - Panel 1 - PanelDepth: 40 mm; PanelOperation: SWINGING; PanelWidth: 0.753571; PanelPosition: LEFT
Type - Door Panel Properties - Panel 2 - PanelDepth: 40 mm; PanelOperation: SWINGING; PanelWidth: 0.267857; PanelPosition: RIGHT
OverallHeight: 2100 mm; OverallWidth: 1200 mm; Classification: 1.10 IfcDoorStyle (uks) (RKAS BIM + ARCHICAD Classification)
Pset_DoorCommon - ThermalTransmittance: 0; IsExternal: no
AR_Uks - 305_Ava_mõõt: 1 200x2 100; 310_Materjal: metall; 335_Välispiire: no; 340_Soojusläbivus: 0; 345_Päikesekiirgus_tegur: nõudeid ei esitata; 355_Pindala: 2.52 m2; 360_Ratastooliga: no; 365_Isesulguv: yes; 370_Evakuatsiooniväljapääs: yes; 375_Viimistlus_seest: MUDELIS: Wood - Pine Grained Horizontal; Wood - Pine Grained Horizontal; MÄRKUS:; 376_Viimistlus_väljast: MUDELIS: Wood - Pine Grained Horizontal; Wood - Pine Grained Horizontal; MÄRKUS:; 380_Lukustus: elektriline; 900_Tootja: Undefined; 905_Mudel: Undefined; 910_Tooteinfo: Undefined; 915_Kasutus-ja_hooldusjuhend: Undefined
AC_Pset_RenovationAndPhasing - Renovation Status: New
Name | In | Reference = 300_Tüüp | 001_Nimetus | 315_Avanemine | 320_Klaas | 325_Helipidavus | 330_Tulekindlus | 350_Klaaspakett
TU-01-1 | Esimene korrus | TU-01-1 | tuletõkke siseuks kahepoolne | Pöördavanev - Vasak ; ARCHICAD tüüp: Side Hung | tuletõkkeklaas EI30 | 30 dB | EI60 | EI30 | Pset_DoorCommon - GlazingAreaFraction: 1.31837
TU-01-5 | Teine korrus | TU-01-5 | tuletõkke siseuks | kahepoolne pöördavanev ; ARCHICAD tüüp: Side Hung | ilma klaasita | 30dB | EI30 | ilma klaasita

# IfcDoor: Double Door Asymmetric 23, TU-01-2
In: Esimene korrus
Type - OperationType: DOUBLE_DOOR_SINGLE_SWING; ParameterTakesPrecedence: no; Sizeable: no
Type - Door Lining Properties - LiningDepth: 115 mm; LiningThickness: 40 mm; ThresholdDepth: 75 mm; ThresholdThickness: 12 mm; LiningOffset: -75 mm; ThresholdOffset: -75 mm; CasingThickness: 50 mm; CasingDepth: 19 mm
Type - Door Panel Properties - Panel 1 - PanelDepth: 40 mm; PanelOperation: SWINGING; PanelWidth: 0.753571; PanelPosition: RIGHT
Type - Door Panel Properties - Panel 2 - PanelDepth: 40 mm; PanelOperation: SWINGING; PanelWidth: 0.267857; PanelPosition: LEFT
OverallHeight: 2100 mm; OverallWidth: 1200 mm; Classification: 1.10 IfcDoorStyle (uks) (RKAS BIM + ARCHICAD Classification)
Pset_DoorCommon - Reference: TU-01-2; ThermalTransmittance: 0; IsExternal: no
AR_Uks - 001_Nimetus: tuletõkke siseuks kahepoolne; 300_Tüüp: TU-01-2; 305_Ava_mõõt: 1 200x2 100; 310_Materjal: metall; 315_Avanemine: Pöördavanev - Parem ; ARCHICAD tüüp: Side Hung; 320_Klaas: ilma klaasita; 325_Helipidavus: 30 dB; 330_Tulekindlus: EI60; 335_Välispiire: no; 340_Soojusläbivus: 0; 345_Päikesekiirgus_tegur: nõudeid ei esitata; 350_Klaaspakett: nõudeid ei esitata; 355_Pindala: 2.52 m2; 360_Ratastooliga: no; 365_Isesulguv: yes; 370_Evakuatsiooniväljapääs: yes; 375_Viimistlus_seest: MUDELIS: Wood - Pine Grained Horizontal; Wood - Pine Grained Horizontal; MÄRKUS:; 376_Viimistlus_väljast: MUDELIS: Wood - Pine Grained Horizontal; Wood - Pine Grained Horizontal; MÄRKUS:; 380_Lukustus: elektriline; 900_Tootja: Undefined; 905_Mudel: Undefined; 910_Tooteinfo: Undefined; 915_Kasutus-ja_hooldusjuhend: Undefined
AC_Pset_RenovationAndPhasing - Renovation Status: New

# IfcDoor: Double Door Asymmetric 23, TU-01-9
In: Teine korrus
Type - OperationType: DOUBLE_DOOR_SINGLE_SWING; ParameterTakesPrecedence: no; Sizeable: no
Type - Door Lining Properties - LiningDepth: 115 mm; LiningThickness: 40 mm; ThresholdDepth: 75 mm; ThresholdThickness: 12 mm; LiningOffset: 0 mm; ThresholdOffset: 40 mm; CasingThickness: 50 mm; CasingDepth: 19 mm
Type - Door Panel Properties - Panel 1 - PanelDepth: 40 mm; PanelOperation: SWINGING; PanelWidth: 0.513043; PanelPosition: LEFT
Type - Door Panel Properties - Panel 2 - PanelDepth: 40 mm; PanelOperation: SWINGING; PanelWidth: 0.513043; PanelPosition: RIGHT
OverallHeight: 2100 mm; OverallWidth: 1000 mm; Classification: 1.10 IfcDoorStyle (uks) (RKAS BIM + ARCHICAD Classification)
Pset_DoorCommon - Reference: TU-01-9; ThermalTransmittance: 0; IsExternal: no
AR_Uks - 001_Nimetus: tuletõkke siseuks kahepoolne; 300_Tüüp: TU-01-9; 305_Ava_mõõt: 1 000x2 100; 310_Materjal: metall; 315_Avanemine: põõrdavanev ; ARCHICAD tüüp: Side Hung; 320_Klaas: ilma klaasita; 325_Helipidavus: 30dB; 330_Tulekindlus: EI30; 335_Välispiire: no; 340_Soojusläbivus: 0; 345_Päikesekiirgus_tegur: nõudeid ei esitata; 350_Klaaspakett: ilma klaasita; 355_Pindala: 2.1 m2; 360_Ratastooliga: no; 365_Isesulguv: yes; 370_Evakuatsiooniväljapääs: no; 375_Viimistlus_seest: MUDELIS: Wood - Pine Grained Horizontal; Wood - Pine Grained Horizontal; MÄRKUS:; 376_Viimistlus_väljast: MUDELIS: Wood - Pine Grained Horizontal; Wood - Pine Grained Horizontal; MÄRKUS:; 380_Lukustus: mehaaniline; 900_Tootja: Undefined; 905_Mudel: Undefined; 910_Tooteinfo: Undefined; 915_Kasutus-ja_hooldusjuhend: Undefined
AC_Pset_RenovationAndPhasing - Renovation Status: New

# IfcDoor: Double Door Asymmetric 23, TU-01-9
In: Teine korrus
Type - OperationType: DOUBLE_DOOR_SINGLE_SWING; ParameterTakesPrecedence: no; Sizeable: no
Type - Door Lining Properties - LiningDepth: 115 mm; LiningThickness: 40 mm; ThresholdDepth: 75 mm; ThresholdThickness: 12 mm; LiningOffset: 0 mm; ThresholdOffset: 40 mm; CasingThickness: 50 mm; CasingDepth: 19 mm
Type - Door Panel Properties - Panel 1 - PanelDepth: 40 mm; PanelOperation: SWINGING; PanelWidth: 0.513043; PanelPosition: RIGHT
Type - Door Panel Properties - Panel 2 - PanelDepth: 40 mm; PanelOperation: SWINGING; PanelWidth: 0.513043; PanelPosition: LEFT
OverallHeight: 2100 mm; OverallWidth: 1000 mm; Classification: 1.10 IfcDoorStyle (uks) (RKAS BIM + ARCHICAD Classification)
Pset_DoorCommon - Reference: TU-01-9; ThermalTransmittance: 0; IsExternal: no
AR_Uks - 001_Nimetus: tuletõkke siseuks kahepoolne; 300_Tüüp: TU-01-9; 305_Ava_mõõt: 1 000x2 100; 310_Materjal: metall; 315_Avanemine: põõrdavanev ; ARCHICAD tüüp: Side Hung; 320_Klaas: ilma klaasita; 325_Helipidavus: 30dB; 330_Tulekindlus: EI30; 335_Välispiire: no; 340_Soojusläbivus: 0; 345_Päikesekiirgus_tegur: nõudeid ei esitata; 350_Klaaspakett: ilma klaasita; 355_Pindala: 2.1 m2; 360_Ratastooliga: no; 365_Isesulguv: yes; 370_Evakuatsiooniväljapääs: no; 375_Viimistlus_seest: MUDELIS: Wood - Pine Grained Horizontal; Wood - Pine Grained Horizontal; MÄRKUS:; 376_Viimistlus_väljast: MUDELIS: Wood - Pine Grained Horizontal; Wood - Pine Grained Horizontal; MÄRKUS:; 380_Lukustus: mehaaniline; 900_Tootja: Undefined; 905_Mudel: Undefined; 910_Tooteinfo: Undefined; 915_Kasutus-ja_hooldusjuhend: Undefined
AC_Pset_RenovationAndPhasing - Renovation Status: New

# IfcDoor: Double Door Asymmetric 23, TU-01-6
In: Esimene korrus
Type - OperationType: DOUBLE_DOOR_SINGLE_SWING; ParameterTakesPrecedence: no; Sizeable: no
Type - Door Lining Properties - LiningDepth: 115 mm; LiningThickness: 40 mm; ThresholdDepth: 75 mm; ThresholdThickness: 12 mm; LiningOffset: 0 mm; ThresholdOffset: 40 mm; CasingThickness: 50 mm; CasingDepth: 19 mm
Type - Door Panel Properties - Panel 1 - PanelDepth: 40 mm; PanelOperation: SWINGING; PanelWidth: 0.64507; PanelPosition: RIGHT
Type - Door Panel Properties - Panel 2 - PanelDepth: 40 mm; PanelOperation: SWINGING; PanelWidth: 0.371831; PanelPosition: LEFT
OverallHeight: 2100 mm; OverallWidth: 1500 mm; Classification: 1.10 IfcDoorStyle (uks) (RKAS BIM + ARCHICAD Classification)
Pset_DoorCommon - Reference: TU-01-6; ThermalTransmittance: 0; GlazingAreaFraction: 1.84997; IsExternal: no
AR_Uks - 001_Nimetus: tuletõkke siseuks kahepoolne; 300_Tüüp: TU-01-6; 305_Ava_mõõt: 1 500x2 100; 310_Materjal: metall; 315_Avanemine: pöördavanev - Parem ; ARCHICAD tüüp: Side Hung; 320_Klaas: tuletõkkeklaas EI30; 325_Helipidavus: 30 dB; 330_Tulekindlus: EI30; 335_Välispiire: no; 340_Soojusläbivus: 0; 345_Päikesekiirgus_tegur: nõudeid ei esitata; 350_Klaaspakett: EI30; 355_Pindala: 3.15 m2; 360_Ratastooliga: no; 365_Isesulguv: yes; 370_Evakuatsiooniväljapääs: yes; 375_Viimistlus_seest: MUDELIS: Wood - Pine Grained Horizontal; Wood - Pine Grained Horizontal; MÄRKUS:; 376_Viimistlus_väljast: MUDELIS: Wood - Pine Grained Horizontal; Wood - Pine Grained Horizontal; MÄRKUS:; 380_Lukustus: elektriline; 900_Tootja: Undefined; 905_Mudel: Undefined; 910_Tooteinfo: Undefined; 915_Kasutus-ja_hooldusjuhend: Undefined
AC_Pset_RenovationAndPhasing - Renovation Status: New

# IfcDoor: Double Door Asymmetric 23, SU-01-9
In: Teine korrus
Type - OperationType: DOUBLE_DOOR_SINGLE_SWING; ParameterTakesPrecedence: no; Sizeable: no
Type - Door Lining Properties - LiningDepth: 115 mm; LiningThickness: 40 mm; ThresholdDepth: 75 mm; ThresholdThickness: 12 mm; LiningOffset: 0 mm; ThresholdOffset: 40 mm; CasingThickness: 50 mm; CasingDepth: 19 mm
Type - Door Panel Properties - Panel 1 - PanelDepth: 40 mm; PanelOperation: SWINGING; PanelWidth: 0.664789; PanelPosition: LEFT
Type - Door Panel Properties - Panel 2 - PanelDepth: 40 mm; PanelOperation: SWINGING; PanelWidth: 0.352113; PanelPosition: RIGHT
OverallHeight: 2100 mm; OverallWidth: 1500 mm; Classification: 1.10 IfcDoorStyle (uks) (RKAS BIM + ARCHICAD Classification)
Pset_DoorCommon - Reference: SU-01-9; ThermalTransmittance: 0; GlazingAreaFraction: 1.84997; IsExternal: no
AR_Uks - 001_Nimetus: siseuks kahepoolne; 300_Tüüp: SU-01-9; 305_Ava_mõõt: 1 500x2 100; 310_Materjal: metall; 315_Avanemine: pöördavanev; ARCHICAD tüüp: Side Hung; 320_Klaas: kirgas; 325_Helipidavus: Rw≥30dB; 330_Tulekindlus: nõudeid ei esitata; 335_Välispiire: no; 340_Soojusläbivus: 0; 345_Päikesekiirgus_tegur: erinõudeid ei esitata; 350_Klaaspakett: 1xklaas; 355_Pindala: 3.15 m2; 360_Ratastooliga: no; 365_Isesulguv: yes; 370_Evakuatsiooniväljapääs: yes; 375_Viimistlus_seest: MUDELIS: Wood - Pine Grained Horizontal; Wood - Pine Grained Horizontal; MÄRKUS:; 376_Viimistlus_väljast: MUDELIS: Wood - Pine Grained Horizontal; Wood - Pine Grained Horizontal; MÄRKUS:; 380_Lukustus: elektriline; 900_Tootja: Undefined; 905_Mudel: Undefined; 910_Tooteinfo: Undefined; 915_Kasutus-ja_hooldusjuhend: Undefined
AC_Pset_RenovationAndPhasing - Renovation Status: New

# IfcDoor: Double Door Asymmetric 23 (2)
In: Esimene korrus
Type - OperationType: DOUBLE_DOOR_SINGLE_SWING; ParameterTakesPrecedence: no; Sizeable: no
Type - Door Lining Properties - LiningDepth: 115 mm; LiningThickness: 40 mm; ThresholdDepth: 75 mm; ThresholdThickness: 12 mm; LiningOffset: 0 mm; ThresholdOffset: 40 mm; CasingThickness: 50 mm; CasingDepth: 19 mm
Type - Door Panel Properties - Panel 1 - PanelDepth: 40 mm; PanelOperation: SWINGING; PanelWidth: 0.753571; PanelPosition: LEFT
Type - Door Panel Properties - Panel 2 - PanelDepth: 40 mm; PanelOperation: SWINGING; PanelWidth: 0.267857; PanelPosition: RIGHT
OverallHeight: 2100 mm; OverallWidth: 1200 mm; Classification: 1.10 IfcDoorStyle (uks) (RKAS BIM + ARCHICAD Classification)
Pset_DoorCommon - ThermalTransmittance: 0; IsExternal: no
AR_Uks - 001_Nimetus: tuletõkke siseuks kahepoolne; 305_Ava_mõõt: 1 200x2 100; 310_Materjal: metall; 335_Välispiire: no; 340_Soojusläbivus: 0; 355_Pindala: 2.52 m2; 365_Isesulguv: yes; 370_Evakuatsiooniväljapääs: yes; 375_Viimistlus_seest: MUDELIS: Wood - Pine Grained Horizontal; Wood - Pine Grained Horizontal; MÄRKUS:; 376_Viimistlus_väljast: MUDELIS: Wood - Pine Grained Horizontal; Wood - Pine Grained Horizontal; MÄRKUS:; 380_Lukustus: elektriline; 900_Tootja: Undefined; 905_Mudel: Undefined; 910_Tooteinfo: Undefined; 915_Kasutus-ja_hooldusjuhend: Undefined
AC_Pset_RenovationAndPhasing - Renovation Status: New
Name | Reference = 300_Tüüp | 315_Avanemine | 320_Klaas | 325_Helipidavus | 330_Tulekindlus | 345_Päikesekiirgus_tegur | 350_Klaaspakett | 360_Ratastooliga
TU-01-2 | TU-01-2 | Pöördavanev - Vasak ; ARCHICAD tüüp: Side Hung | ilma klaasita | 30 dB | EI60 | nõudeid ei esitata | nõudeid ei esitata | no
TU-01-4 | TU-01-4 | pöördavanev - Vasak ; ARCHICAD tüüp: Side Hung | tuletõkke klaas EI30 | 30dB | EI30 | erinõudeid ei esitata | tuletõkkeklaas EI30 | yes | Pset_DoorCommon - GlazingAreaFraction: 1.31837

# IfcDoor: Double Door Asymmetric 23, TU-01-1
In: Esimene korrus
Type - OperationType: DOUBLE_DOOR_SINGLE_SWING; ParameterTakesPrecedence: no; Sizeable: no
Type - Door Lining Properties - LiningDepth: 115 mm; LiningThickness: 40 mm; ThresholdDepth: 75 mm; ThresholdThickness: 12 mm; LiningOffset: 0 mm; ThresholdOffset: 40 mm; CasingThickness: 50 mm; CasingDepth: 19 mm
Type - Door Panel Properties - Panel 1 - PanelDepth: 40 mm; PanelOperation: SWINGING; PanelWidth: 0.753571; PanelPosition: RIGHT
Type - Door Panel Properties - Panel 2 - PanelDepth: 40 mm; PanelOperation: SWINGING; PanelWidth: 0.267857; PanelPosition: LEFT
OverallHeight: 2100 mm; OverallWidth: 1200 mm; Classification: 1.10 IfcDoorStyle (uks) (RKAS BIM + ARCHICAD Classification)
Pset_DoorCommon - Reference: TU-01-1; ThermalTransmittance: 0; GlazingAreaFraction: 1.31837; IsExternal: no
AR_Uks - 001_Nimetus: tuletõkke siseuks kahepoolne; 300_Tüüp: TU-01-1; 305_Ava_mõõt: 1 200x2 100; 310_Materjal: metall; 315_Avanemine: Pöördavanev - Parem ; ARCHICAD tüüp: Side Hung; 320_Klaas: tuletõkkeklaas EI30; 325_Helipidavus: 30 dB; 330_Tulekindlus: EI60; 335_Välispiire: no; 340_Soojusläbivus: 0; 345_Päikesekiirgus_tegur: nõudeid ei esitata; 350_Klaaspakett: EI30; 355_Pindala: 2.52 m2; 360_Ratastooliga: no; 365_Isesulguv: yes; 370_Evakuatsiooniväljapääs: yes; 375_Viimistlus_seest: MUDELIS: Wood - Pine Grained Horizontal; Wood - Pine Grained Horizontal; MÄRKUS:; 376_Viimistlus_väljast: MUDELIS: Wood - Pine Grained Horizontal; Wood - Pine Grained Horizontal; MÄRKUS:; 380_Lukustus: elektriline; 900_Tootja: Undefined; 905_Mudel: Undefined; 910_Tooteinfo: Undefined; 915_Kasutus-ja_hooldusjuhend: Undefined
AC_Pset_RenovationAndPhasing - Renovation Status: New

# IfcDoor: Double Door Asymmetric 23, SU-01-8
In: Esimene korrus
Type - OperationType: DOUBLE_DOOR_SINGLE_SWING; ParameterTakesPrecedence: no; Sizeable: no
Type - Door Lining Properties - LiningDepth: 115 mm; LiningThickness: 40 mm; ThresholdDepth: 75 mm; ThresholdThickness: 12 mm; LiningOffset: 115 mm; ThresholdOffset: 115 mm; CasingThickness: 50 mm; CasingDepth: 19 mm
Type - Door Panel Properties - Panel 1 - PanelDepth: 40 mm; PanelOperation: SWINGING; PanelWidth: 0.753571; PanelPosition: LEFT
Type - Door Panel Properties - Panel 2 - PanelDepth: 40 mm; PanelOperation: SWINGING; PanelWidth: 0.267857; PanelPosition: RIGHT
OverallHeight: 2100 mm; OverallWidth: 1200 mm; Classification: 1.10 IfcDoorStyle (uks) (RKAS BIM + ARCHICAD Classification)
Pset_DoorCommon - Reference: SU-01-8; ThermalTransmittance: 0; IsExternal: no
AR_Uks - 001_Nimetus: kahepoolne iseuks; 300_Tüüp: SU-01-8; 305_Ava_mõõt: 1 200x2 100; 310_Materjal: metall; 315_Avanemine: Pöördavanev - Vasak ; ARCHICAD tüüp: Side Hung; 320_Klaas: ilma klaasita; 325_Helipidavus: Rw≥30dB; 330_Tulekindlus: nõudeid ei esitata; 335_Välispiire: no; 340_Soojusläbivus: 0; 345_Päikesekiirgus_tegur: nõudeid ei esitata; 350_Klaaspakett: nõudeid ei esitata; 355_Pindala: 2.52 m2; 360_Ratastooliga: no; 365_Isesulguv: yes; 370_Evakuatsiooniväljapääs: no; 375_Viimistlus_seest: MUDELIS: Wood - Pine Grained Horizontal; Wood - Pine Grained Horizontal; MÄRKUS:; 376_Viimistlus_väljast: MUDELIS: Wood - Pine Grained Horizontal; Wood - Pine Grained Horizontal; MÄRKUS:; 380_Lukustus: elektriline; 900_Tootja: Undefined; 905_Mudel: Undefined; 910_Tooteinfo: Undefined; 915_Kasutus-ja_hooldusjuhend: Undefined
AC_Pset_RenovationAndPhasing - Renovation Status: New

# IfcDoor: Double Door Asymmetric 23, TU-01-2
In: Esimene korrus
Type - OperationType: DOUBLE_DOOR_SINGLE_SWING; ParameterTakesPrecedence: no; Sizeable: no
Type - Door Lining Properties - LiningDepth: 115 mm; LiningThickness: 40 mm; ThresholdDepth: 75 mm; ThresholdThickness: 12 mm; LiningOffset: 115 mm; ThresholdOffset: 115 mm; CasingThickness: 50 mm; CasingDepth: 19 mm
Type - Door Panel Properties - Panel 1 - PanelDepth: 40 mm; PanelOperation: SWINGING; PanelWidth: 0.753571; PanelPosition: RIGHT
Type - Door Panel Properties - Panel 2 - PanelDepth: 40 mm; PanelOperation: SWINGING; PanelWidth: 0.267857; PanelPosition: LEFT
OverallHeight: 2100 mm; OverallWidth: 1200 mm; Classification: 1.10 IfcDoorStyle (uks) (RKAS BIM + ARCHICAD Classification)
Pset_DoorCommon - Reference: TU-01-2; ThermalTransmittance: 0; IsExternal: no
AR_Uks - 001_Nimetus: tuletõkke siseuks kahepoolne; 300_Tüüp: TU-01-2; 305_Ava_mõõt: 1 200x2 100; 310_Materjal: metall; 315_Avanemine: Pöördavanev - Parem ; ARCHICAD tüüp: Side Hung; 320_Klaas: ilma klaasita; 325_Helipidavus: 30 dB; 330_Tulekindlus: EI60; 335_Välispiire: no; 340_Soojusläbivus: 0; 345_Päikesekiirgus_tegur: nõudeid ei esitata; 350_Klaaspakett: nõudeid ei esitata; 355_Pindala: 2.52 m2; 360_Ratastooliga: no; 365_Isesulguv: yes; 370_Evakuatsiooniväljapääs: yes; 375_Viimistlus_seest: MUDELIS: Wood - Pine Grained Horizontal; Wood - Pine Grained Horizontal; MÄRKUS:; 376_Viimistlus_väljast: MUDELIS: Wood - Pine Grained Horizontal; Wood - Pine Grained Horizontal; MÄRKUS:; 380_Lukustus: elektriline; 900_Tootja: Undefined; 905_Mudel: Undefined; 910_Tooteinfo: Undefined; 915_Kasutus-ja_hooldusjuhend: Undefined
AC_Pset_RenovationAndPhasing - Renovation Status: New

# IfcDoor: Double Door Asymmetric 23, TU-01-6
In: Teine korrus
Type - OperationType: DOUBLE_DOOR_SINGLE_SWING; ParameterTakesPrecedence: no; Sizeable: no
Type - Door Lining Properties - LiningDepth: 115 mm; LiningThickness: 40 mm; ThresholdDepth: 75 mm; ThresholdThickness: 12 mm; LiningOffset: 115 mm; ThresholdOffset: 115 mm
Type - Door Panel Properties - Panel 1 - PanelDepth: 40 mm; PanelOperation: SWINGING; PanelWidth: 0.664789; PanelPosition: RIGHT
Type - Door Panel Properties - Panel 2 - PanelDepth: 40 mm; PanelOperation: SWINGING; PanelWidth: 0.352113; PanelPosition: LEFT
OverallHeight: 2100 mm; OverallWidth: 1500 mm; Classification: 1.10 IfcDoorStyle (uks) (RKAS BIM + ARCHICAD Classification)
Pset_DoorCommon - Reference: TU-01-6; ThermalTransmittance: 0; GlazingAreaFraction: 1.84997; IsExternal: no
AR_Uks - 001_Nimetus: tuletõkke siseuks kahepoolne; 300_Tüüp: TU-01-6; 305_Ava_mõõt: 1 500x2 100; 310_Materjal: metall; 315_Avanemine: pöördavanev - Parem ; ARCHICAD tüüp: Side Hung; 320_Klaas: tuletõkkeklaas EI30; 325_Helipidavus: 30dB; 330_Tulekindlus: EI30; 335_Välispiire: no; 340_Soojusläbivus: 0; 345_Päikesekiirgus_tegur: nõudeid ei esitata; 350_Klaaspakett: 1xtuletõkkeklaas; 355_Pindala: 3.15 m2; 360_Ratastooliga: no; 365_Isesulguv: yes; 370_Evakuatsiooniväljapääs: yes; 375_Viimistlus_seest: MUDELIS: Wood - Pine Grained Horizontal; Wood - Pine Grained Horizontal; MÄRKUS:; 376_Viimistlus_väljast: MUDELIS: Wood - Pine Grained Horizontal; Wood - Pine Grained Horizontal; MÄRKUS:; 380_Lukustus: elektriline; 900_Tootja: Undefined; 905_Mudel: Undefined; 910_Tooteinfo: Undefined; 915_Kasutus-ja_hooldusjuhend: Undefined
AC_Pset_RenovationAndPhasing - Renovation Status: New

# IfcDoor: Double Door Asymmetric 23, TU-01-2
In: Esimene korrus
Type - OperationType: DOUBLE_DOOR_SINGLE_SWING; ParameterTakesPrecedence: no; Sizeable: no
Type - Door Lining Properties - LiningDepth: 115 mm; LiningThickness: 40 mm; ThresholdDepth: 75 mm; ThresholdThickness: 12 mm; LiningOffset: 140 mm; ThresholdOffset: 180 mm; CasingThickness: 50 mm; CasingDepth: 19 mm
Type - Door Panel Properties - Panel 1 - PanelDepth: 40 mm; PanelOperation: SWINGING; PanelWidth: 0.753571; PanelPosition: LEFT
Type - Door Panel Properties - Panel 2 - PanelDepth: 40 mm; PanelOperation: SWINGING; PanelWidth: 0.267857; PanelPosition: RIGHT
OverallHeight: 2100 mm; OverallWidth: 1200 mm; Classification: 1.10 IfcDoorStyle (uks) (RKAS BIM + ARCHICAD Classification)
Pset_DoorCommon - Reference: TU-01-2; ThermalTransmittance: 0; IsExternal: no
AR_Uks - 001_Nimetus: tuletõkke siseuks kahepoolne; 300_Tüüp: TU-01-2; 305_Ava_mõõt: 1 200x2 100; 310_Materjal: metall; 315_Avanemine: Pöördavanev - Vasak ; ARCHICAD tüüp: Side Hung; 320_Klaas: ilma klaasita; 325_Helipidavus: 30 dB; 330_Tulekindlus: EI60; 335_Välispiire: no; 340_Soojusläbivus: 0; 345_Päikesekiirgus_tegur: nõudeid ei esitata; 350_Klaaspakett: nõudeid ei esitata; 355_Pindala: 2.52 m2; 360_Ratastooliga: no; 365_Isesulguv: yes; 370_Evakuatsiooniväljapääs: yes; 375_Viimistlus_seest: MUDELIS: Wood - Pine Grained Horizontal; Wood - Pine Grained Horizontal; MÄRKUS:; 376_Viimistlus_väljast: MUDELIS: Wood - Pine Grained Horizontal; Wood - Pine Grained Horizontal; MÄRKUS:; 380_Lukustus: elektriline; 900_Tootja: Undefined; 905_Mudel: Undefined; 910_Tooteinfo: Undefined; 915_Kasutus-ja_hooldusjuhend: Undefined
AC_Pset_RenovationAndPhasing - Renovation Status: New

# IfcDoor: Double Door Asymmetric 23, TU-01-2
In: Esimene korrus
Type - OperationType: DOUBLE_DOOR_SINGLE_SWING; ParameterTakesPrecedence: no; Sizeable: no
Type - Door Lining Properties - LiningDepth: 115 mm; LiningThickness: 40 mm; ThresholdDepth: 75 mm; ThresholdThickness: 12 mm; LiningOffset: 140 mm; ThresholdOffset: 180 mm; CasingThickness: 50 mm; CasingDepth: 19 mm
Type - Door Panel Properties - Panel 1 - PanelDepth: 40 mm; PanelOperation: SWINGING; PanelWidth: 0.753571; PanelPosition: RIGHT
Type - Door Panel Properties - Panel 2 - PanelDepth: 40 mm; PanelOperation: SWINGING; PanelWidth: 0.267857; PanelPosition: LEFT
OverallHeight: 2100 mm; OverallWidth: 1200 mm; Classification: 1.10 IfcDoorStyle (uks) (RKAS BIM + ARCHICAD Classification)
Pset_DoorCommon - Reference: TU-01-2; ThermalTransmittance: 0; IsExternal: no
AR_Uks - 001_Nimetus: tuletõkke siseuks kahepoolne; 300_Tüüp: TU-01-2; 305_Ava_mõõt: 1 200x2 100; 310_Materjal: metall; 315_Avanemine: Pöördavanev - Parem ; ARCHICAD tüüp: Side Hung; 320_Klaas: ilma klaasita; 325_Helipidavus: 30 dB; 330_Tulekindlus: EI60; 335_Välispiire: no; 340_Soojusläbivus: 0; 345_Päikesekiirgus_tegur: nõudeid ei esitata; 350_Klaaspakett: nõudeid ei esitata; 355_Pindala: 2.52 m2; 360_Ratastooliga: no; 365_Isesulguv: yes; 370_Evakuatsiooniväljapääs: yes; 375_Viimistlus_seest: MUDELIS: Wood - Pine Grained Horizontal; Wood - Pine Grained Horizontal; MÄRKUS:; 376_Viimistlus_väljast: MUDELIS: Wood - Pine Grained Horizontal; Wood - Pine Grained Horizontal; MÄRKUS:; 380_Lukustus: elektriline; 900_Tootja: Undefined; 905_Mudel: Undefined; 910_Tooteinfo: Undefined; 915_Kasutus-ja_hooldusjuhend: Undefined
AC_Pset_RenovationAndPhasing - Renovation Status: New

# IfcDoor: Double Door Asymmetric 23, TU-01-4
In: Esimene korrus
Type - OperationType: DOUBLE_DOOR_SINGLE_SWING; ParameterTakesPrecedence: no; Sizeable: no
Type - Door Lining Properties - LiningDepth: 115 mm; LiningThickness: 40 mm; ThresholdDepth: 75 mm; ThresholdThickness: 12 mm; LiningOffset: 190 mm; ThresholdOffset: 230 mm; CasingThickness: 50 mm; CasingDepth: 19 mm
Type - Door Panel Properties - Panel 1 - PanelDepth: 40 mm; PanelOperation: SWINGING; PanelWidth: 0.753571; PanelPosition: LEFT
Type - Door Panel Properties - Panel 2 - PanelDepth: 40 mm; PanelOperation: SWINGING; PanelWidth: 0.267857; PanelPosition: RIGHT
OverallHeight: 2100 mm; OverallWidth: 1200 mm; Classification: 1.10 IfcDoorStyle (uks) (RKAS BIM + ARCHICAD Classification)
Pset_DoorCommon - Reference: TU-01-4; ThermalTransmittance: 0; GlazingAreaFraction: 1.31837; IsExternal: no
AR_Uks - 001_Nimetus: tuletõkke siseuks kahepoolne; 300_Tüüp: TU-01-4; 305_Ava_mõõt: 1 200x2 100; 310_Materjal: metall; 315_Avanemine: pöördavanev - Vasak ; ARCHICAD tüüp: Side Hung; 320_Klaas: tuletõkke klaas EI30; 325_Helipidavus: 30dB; 330_Tulekindlus: EI30; 335_Välispiire: no; 340_Soojusläbivus: 0; 345_Päikesekiirgus_tegur: erinõudeid ei esitata; 350_Klaaspakett: tuletõkkeklaas EI30; 355_Pindala: 2.52 m2; 360_Ratastooliga: yes; 365_Isesulguv: yes; 370_Evakuatsiooniväljapääs: yes; 375_Viimistlus_seest: MUDELIS: Wood - Pine Grained Horizontal; Wood - Pine Grained Horizontal; MÄRKUS:; 376_Viimistlus_väljast: MUDELIS: Wood - Pine Grained Horizontal; Wood - Pine Grained Horizontal; MÄRKUS:; 380_Lukustus: elektriline; 900_Tootja: Undefined; 905_Mudel: Undefined; 910_Tooteinfo: Undefined; 915_Kasutus-ja_hooldusjuhend: Undefined
AC_Pset_RenovationAndPhasing - Renovation Status: New

# IfcDoor: Double Door Asymmetric 23 (2)
Type - OperationType: DOUBLE_DOOR_SINGLE_SWING; ParameterTakesPrecedence: no; Sizeable: no
Type - Door Lining Properties - LiningDepth: 115 mm; LiningThickness: 40 mm; ThresholdDepth: 75 mm; ThresholdThickness: 12 mm; LiningOffset: 190 mm; ThresholdOffset: 230 mm; CasingThickness: 50 mm; CasingDepth: 19 mm
Type - Door Panel Properties - Panel 1 - PanelDepth: 40 mm; PanelOperation: SWINGING; PanelWidth: 0.753571; PanelPosition: RIGHT
Type - Door Panel Properties - Panel 2 - PanelDepth: 40 mm; PanelOperation: SWINGING; PanelWidth: 0.267857; PanelPosition: LEFT
OverallHeight: 2100 mm; OverallWidth: 1200 mm; Classification: 1.10 IfcDoorStyle (uks) (RKAS BIM + ARCHICAD Classification)
Pset_DoorCommon - ThermalTransmittance: 0; IsExternal: no
AR_Uks - 305_Ava_mõõt: 1 200x2 100; 310_Materjal: metall; 335_Välispiire: no; 340_Soojusläbivus: 0; 355_Pindala: 2.52 m2; 360_Ratastooliga: no; 365_Isesulguv: yes; 370_Evakuatsiooniväljapääs: yes; 375_Viimistlus_seest: MUDELIS: Wood - Pine Grained Horizontal; Wood - Pine Grained Horizontal; MÄRKUS:; 376_Viimistlus_väljast: MUDELIS: Wood - Pine Grained Horizontal; Wood - Pine Grained Horizontal; MÄRKUS:; 380_Lukustus: elektriline; 900_Tootja: Undefined; 905_Mudel: Undefined; 910_Tooteinfo: Undefined; 915_Kasutus-ja_hooldusjuhend: Undefined
AC_Pset_RenovationAndPhasing - Renovation Status: New
Name | In | Reference = 300_Tüüp | 001_Nimetus | 315_Avanemine | 320_Klaas | 325_Helipidavus | 330_Tulekindlus | 345_Päikesekiirgus_tegur | 350_Klaaspakett
TU-01-2 | Esimene korrus | TU-01-2 | tuletõkke siseuks kahepoolne | Pöördavanev - Parem ; ARCHICAD tüüp: Side Hung | ilma klaasita | 30 dB | EI60 | nõudeid ei esitata | nõudeid ei esitata
TU-01-4 | Teine korrus | TU-01-4 | tuletõkke siseuks | pöördavanev - Parem ; ARCHICAD tüüp: Side Hung | tuletõkke klaas | 30dB | EI30 | erinõudeid ei esitata | tuletõkkeklaas | Pset_DoorCommon - GlazingAreaFraction: 1.31837

# IfcDoor: Double Door Asymmetric 23, TU-01-2
In: Esimene korrus
Type - OperationType: DOUBLE_DOOR_SINGLE_SWING; ParameterTakesPrecedence: no; Sizeable: no
Type - Door Lining Properties - LiningDepth: 115 mm; LiningThickness: 40 mm; ThresholdDepth: 75 mm; ThresholdThickness: 12 mm; LiningOffset: 235 mm; ThresholdOffset: 235 mm; CasingThickness: 50 mm; CasingDepth: 19 mm
Type - Door Panel Properties - Panel 1 - PanelDepth: 40 mm; PanelOperation: SWINGING; PanelWidth: 0.753571; PanelPosition: RIGHT
Type - Door Panel Properties - Panel 2 - PanelDepth: 40 mm; PanelOperation: SWINGING; PanelWidth: 0.267857; PanelPosition: LEFT
OverallHeight: 2100 mm; OverallWidth: 1200 mm; Classification: 1.10 IfcDoorStyle (uks) (RKAS BIM + ARCHICAD Classification)
Pset_DoorCommon - Reference: TU-01-2; ThermalTransmittance: 0; IsExternal: no
AR_Uks - 001_Nimetus: tuletõkke siseuks kahepoolne; 300_Tüüp: TU-01-2; 305_Ava_mõõt: 1 200x2 100; 310_Materjal: metall; 315_Avanemine: Pöördavanev - Parem ; ARCHICAD tüüp: Side Hung; 320_Klaas: ilma klaasita; 325_Helipidavus: 30 dB; 330_Tulekindlus: EI60; 335_Välispiire: no; 340_Soojusläbivus: 0; 345_Päikesekiirgus_tegur: nõudeid ei esitata; 350_Klaaspakett: nõudeid ei esitata; 355_Pindala: 2.52 m2; 360_Ratastooliga: no; 365_Isesulguv: yes; 370_Evakuatsiooniväljapääs: yes; 375_Viimistlus_seest: MUDELIS: Wood - Pine Grained Horizontal; Wood - Pine Grained Horizontal; MÄRKUS:; 376_Viimistlus_väljast: MUDELIS: Wood - Pine Grained Horizontal; Wood - Pine Grained Horizontal; MÄRKUS:; 380_Lukustus: elektriline; 900_Tootja: Undefined; 905_Mudel: Undefined; 910_Tooteinfo: Undefined; 915_Kasutus-ja_hooldusjuhend: Undefined
AC_Pset_RenovationAndPhasing - Renovation Status: New

# IfcDoor: Double Door Asymmetric 23, TU-01-2
In: Esimene korrus
Type - OperationType: DOUBLE_DOOR_SINGLE_SWING; ParameterTakesPrecedence: no; Sizeable: no
Type - Door Lining Properties - LiningDepth: 115 mm; LiningThickness: 40 mm; ThresholdDepth: 75 mm; ThresholdThickness: 12 mm; LiningOffset: 240 mm; ThresholdOffset: 280 mm; CasingThickness: 50 mm; CasingDepth: 19 mm
Type - Door Panel Properties - Panel 1 - PanelDepth: 40 mm; PanelOperation: SWINGING; PanelWidth: 0.753571; PanelPosition: LEFT
Type - Door Panel Properties - Panel 2 - PanelDepth: 40 mm; PanelOperation: SWINGING; PanelWidth: 0.267857; PanelPosition: RIGHT
OverallHeight: 2100 mm; OverallWidth: 1200 mm; Classification: 1.10 IfcDoorStyle (uks) (RKAS BIM + ARCHICAD Classification)
Pset_DoorCommon - Reference: TU-01-2; ThermalTransmittance: 0; IsExternal: no
AR_Uks - 001_Nimetus: tuletõkke siseuks kahepoolne; 300_Tüüp: TU-01-2; 305_Ava_mõõt: 1 200x2 100; 310_Materjal: metall; 315_Avanemine: Pöördavanev - Vasak ; ARCHICAD tüüp: Side Hung; 320_Klaas: ilma klaasita; 325_Helipidavus: 30 dB; 330_Tulekindlus: EI60; 335_Välispiire: no; 340_Soojusläbivus: 0; 345_Päikesekiirgus_tegur: nõudeid ei esitata; 350_Klaaspakett: nõudeid ei esitata; 355_Pindala: 2.52 m2; 360_Ratastooliga: no; 365_Isesulguv: yes; 370_Evakuatsiooniväljapääs: yes; 375_Viimistlus_seest: MUDELIS: Wood - Pine Grained Horizontal; Wood - Pine Grained Horizontal; MÄRKUS:; 376_Viimistlus_väljast: MUDELIS: Wood - Pine Grained Horizontal; Wood - Pine Grained Horizontal; MÄRKUS:; 380_Lukustus: elektriline; 900_Tootja: Undefined; 905_Mudel: Undefined; 910_Tooteinfo: Undefined; 915_Kasutus-ja_hooldusjuhend: Undefined
AC_Pset_RenovationAndPhasing - Renovation Status: New

# IfcDoor: Double Door Asymmetric 23 (2)
In: Esimene korrus
Type - OperationType: DOUBLE_DOOR_SINGLE_SWING; ParameterTakesPrecedence: no; Sizeable: no
Type - Door Lining Properties - LiningDepth: 115 mm; LiningThickness: 40 mm; ThresholdDepth: 75 mm; ThresholdThickness: 12 mm; LiningOffset: 240 mm; ThresholdOffset: 280 mm; CasingThickness: 50 mm; CasingDepth: 19 mm
Type - Door Panel Properties - Panel 1 - PanelDepth: 40 mm; PanelOperation: SWINGING; PanelWidth: 0.753571; PanelPosition: RIGHT
Type - Door Panel Properties - Panel 2 - PanelDepth: 40 mm; PanelOperation: SWINGING; PanelWidth: 0.267857; PanelPosition: LEFT
OverallHeight: 2100 mm; OverallWidth: 1200 mm; Classification: 1.10 IfcDoorStyle (uks) (RKAS BIM + ARCHICAD Classification)
Pset_DoorCommon - ThermalTransmittance: 0; IsExternal: no
AR_Uks - 305_Ava_mõõt: 1 200x2 100; 310_Materjal: metall; 315_Avanemine: Pöördavanev - Parem ; ARCHICAD tüüp: Side Hung; 320_Klaas: ilma klaasita; 325_Helipidavus: 30 dB; 335_Välispiire: no; 340_Soojusläbivus: 0; 345_Päikesekiirgus_tegur: nõudeid ei esitata; 350_Klaaspakett: nõudeid ei esitata; 355_Pindala: 2.52 m2; 360_Ratastooliga: no; 365_Isesulguv: yes; 370_Evakuatsiooniväljapääs: yes; 375_Viimistlus_seest: MUDELIS: Wood - Pine Grained Horizontal; Wood - Pine Grained Horizontal; MÄRKUS:; 376_Viimistlus_väljast: MUDELIS: Wood - Pine Grained Horizontal; Wood - Pine Grained Horizontal; MÄRKUS:; 380_Lukustus: elektriline; 900_Tootja: Undefined; 905_Mudel: Undefined; 910_Tooteinfo: Undefined; 915_Kasutus-ja_hooldusjuhend: Undefined
AC_Pset_RenovationAndPhasing - Renovation Status: New
Name | Reference = 300_Tüüp | 001_Nimetus | 330_Tulekindlus
TU-01-2 | TU-01-2 | tuletõkke siseuks kahepoolne | EI60
TU-01-5 | TU-01-5 | Tuletõkke siseuks kahepoolne | EI30

# IfcDoor: Double Door with 2 Sidelights, Transom 23, VU-03
In: Esimene korrus
Type - OperationType: USERDEFINED; ParameterTakesPrecedence: no; Sizeable: no
OverallHeight: 2600 mm; OverallWidth: 3200 mm; Classification: 1.10 IfcDoorStyle (uks) (RKAS BIM + ARCHICAD Classification)
Pset_DoorCommon - Reference: VU-03; ThermalTransmittance: 0; GlazingAreaFraction: 6.40349; IsExternal: yes
AR_Uks - 001_Nimetus: kahepoolne välisuks + aken; 300_Tüüp: VU-03; 305_Ava_mõõt: 3 200x2 600; 310_Materjal: metall; 315_Avanemine: põõrdavanev; ARCHICAD tüüp: Side Hung; 320_Klaas: 3xklaaspakett; 325_Helipidavus: Rw≥35dB; 330_Tulekindlus: nõudeid ei esitata; 335_Välispiire: yes; 340_Soojusläbivus: 1.1; 345_Päikesekiirgus_tegur: 0,4; 350_Klaaspakett: 3k (6+4+10); 355_Pindala: 8.32 m2; 360_Ratastooliga: yes; 365_Isesulguv: yes; 370_Evakuatsiooniväljapääs: yes; 375_Viimistlus_seest: MUDELIS: Wood - Pine Grained Horizontal; Wood - Pine Grained Horizontal; MÄRKUS:; 376_Viimistlus_väljast: MUDELIS: Wood - Pine Grained Horizontal; Wood - Pine Grained Horizontal; MÄRKUS:; 380_Lukustus: elektriline; 900_Tootja: Undefined; 905_Mudel: Undefined; 910_Tooteinfo: Undefined; 915_Kasutus-ja_hooldusjuhend: Undefined
AC_Pset_RenovationAndPhasing - Renovation Status: New

# IfcDoor: Double Door with Transom 23, VU-08
In: Esimene korrus
Type - OperationType: DOUBLE_DOOR_SINGLE_SWING; ParameterTakesPrecedence: no; Sizeable: no
Type - Door Lining Properties - LiningDepth: 115 mm; LiningThickness: 40 mm; ThresholdDepth: 75 mm; ThresholdThickness: 12 mm; TransomThickness: 40 mm; TransomOffset: 2100 mm; LiningOffset: -80 mm; ThresholdOffset: -40 mm; CasingThickness: 50 mm; CasingDepth: 19 mm
Type - Door Panel Properties - Panel 1 - PanelDepth: 40 mm; PanelOperation: SWINGING; PanelWidth: 0.614085; PanelPosition: RIGHT
Type - Door Panel Properties - Panel 2 - PanelDepth: 40 mm; PanelOperation: SWINGING; PanelWidth: 0.402817; PanelPosition: LEFT
OverallHeight: 2600 mm; OverallWidth: 1500 mm; Classification: 1.10 IfcDoorStyle (uks) (RKAS BIM + ARCHICAD Classification)
Pset_DoorCommon - Reference: VU-08; ThermalTransmittance: 0; GlazingAreaFraction: 2.48813; IsExternal: yes
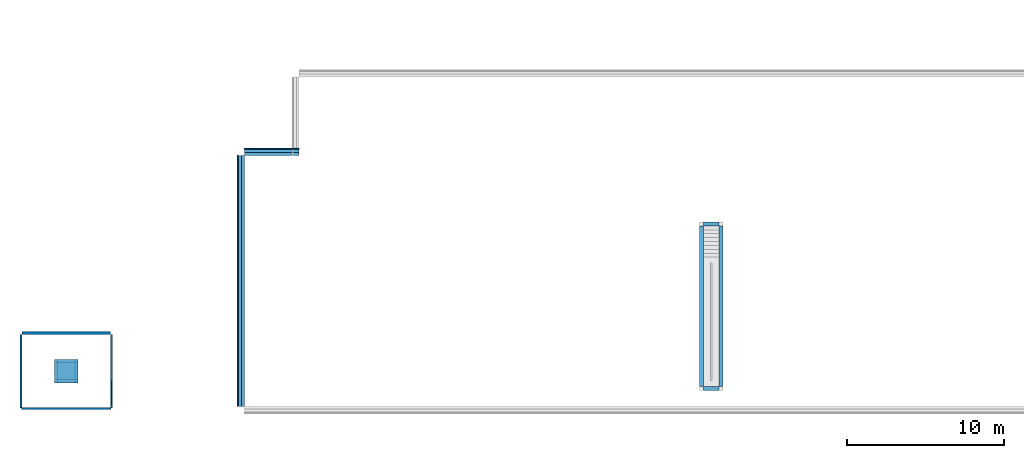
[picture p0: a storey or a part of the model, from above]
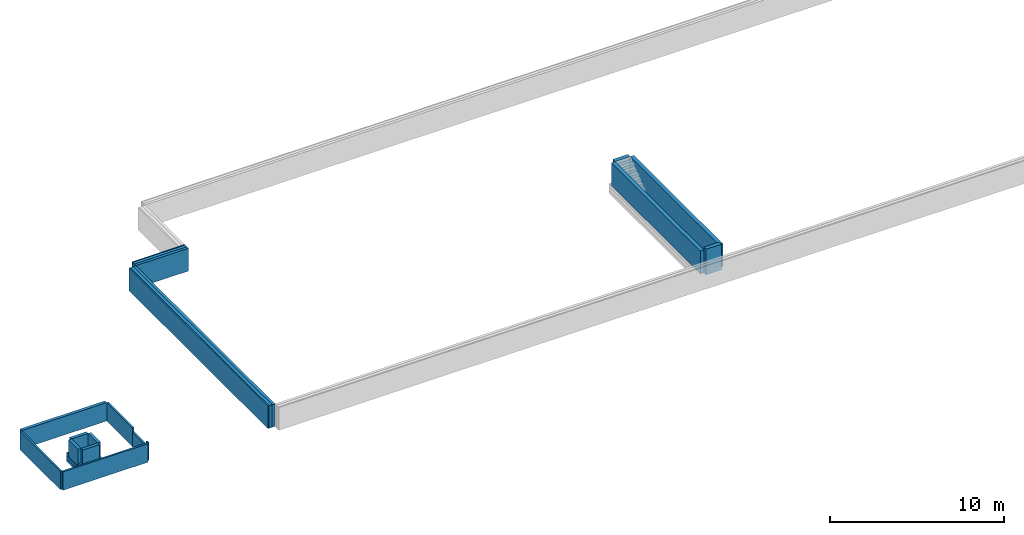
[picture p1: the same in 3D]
Properties of the parts of a building model (IFC2X3), part 3 of 4

# IfcDoor: Double Door with Transom 23, VU-08
AR_Uks - 001_Nimetus: kahepoolne kahepoolne välisuks + aken; 300_Tüüp: VU-08; 305_Ava_mõõt: 1 500x2 600; 310_Materjal: metall; 315_Avanemine: pöördavanev; ARCHICAD tüüp: Side Hung; 320_Klaas: 3xklaaspakett; 325_Helipidavus: Rw≥35dB; 330_Tulekindlus: nõudeid ei esitata; 335_Välispiire: yes; 340_Soojusläbivus: 1.1; 345_Päikesekiirgus_tegur: 0,4; 350_Klaaspakett: 3k (6+4+10); 355_Pindala: 3.9 m2; 360_Ratastooliga: no; 365_Isesulguv: yes; 370_Evakuatsiooniväljapääs: yes; 375_Viimistlus_seest: MUDELIS: Paint - Glossy White; Paint - Glossy White; MÄRKUS:; 376_Viimistlus_väljast: MUDELIS: Paint - Glossy White; Paint - Glossy White; MÄRKUS:; 380_Lukustus: elektriline; 900_Tootja: Undefined; 905_Mudel: Undefined; 910_Tooteinfo: Undefined; 915_Kasutus-ja_hooldusjuhend: Undefined
AC_Pset_RenovationAndPhasing - Renovation Status: New

# IfcDoor: Double Door with Transom 23, VU-01
In: Esimene korrus
Type - OperationType: DOUBLE_DOOR_SINGLE_SWING; ParameterTakesPrecedence: no; Sizeable: no
Type - Door Lining Properties - LiningDepth: 115 mm; LiningThickness: 40 mm; ThresholdDepth: 75 mm; ThresholdThickness: 12 mm; TransomThickness: 40 mm; TransomOffset: 2100 mm; LiningOffset: -80 mm; ThresholdOffset: -40 mm
Type - Door Panel Properties - Panel 1 - PanelDepth: 40 mm; PanelOperation: SWINGING; PanelWidth: 0.614085; PanelPosition: LEFT
Type - Door Panel Properties - Panel 2 - PanelDepth: 40 mm; PanelOperation: SWINGING; PanelWidth: 0.402817; PanelPosition: RIGHT
OverallHeight: 2600 mm; OverallWidth: 1500 mm; Classification: 1.10 IfcDoorStyle (uks) (RKAS BIM + ARCHICAD Classification)
Pset_DoorCommon - Reference: VU-01; ThermalTransmittance: 0; GlazingAreaFraction: 0.5964; IsExternal: yes
AR_Uks - 001_Nimetus: kahepoolne välisuks + aken; 300_Tüüp: VU-01; 305_Ava_mõõt: 1 500x2 600; 310_Materjal: metall; 315_Avanemine: pöördavanev; ARCHICAD tüüp: Side Hung; 320_Klaas: uks ilma klaasita + aken 3xklaaspakett; 325_Helipidavus: Rw≥35dB; 330_Tulekindlus: nõudeid ei esitata; 335_Välispiire: yes; 340_Soojusläbivus: 1.1; 345_Päikesekiirgus_tegur: 0,4; 350_Klaaspakett: 3k (6+4+10); 355_Pindala: 3.9 m2; 360_Ratastooliga: no; 365_Isesulguv: yes; 370_Evakuatsiooniväljapääs: yes; 375_Viimistlus_seest: MUDELIS: Mtl-Aluminium; Mtl-Aluminium; MÄRKUS:; 376_Viimistlus_väljast: MUDELIS: Mtl-Aluminium; Mtl-Aluminium; MÄRKUS:; 380_Lukustus: elektriline; 900_Tootja: Undefined; 905_Mudel: Undefined; 910_Tooteinfo: Undefined; 915_Kasutus-ja_hooldusjuhend: Undefined
AC_Pset_RenovationAndPhasing - Renovation Status: New

# IfcDoor: Double Door with Transom 23, VU-02
In: Esimene korrus
Type - OperationType: DOUBLE_DOOR_SINGLE_SWING; ParameterTakesPrecedence: no; Sizeable: no
Type - Door Lining Properties - LiningDepth: 115 mm; LiningThickness: 40 mm; ThresholdDepth: 75 mm; ThresholdThickness: 12 mm; TransomThickness: 40 mm; TransomOffset: 2100 mm; LiningOffset: 0 mm; ThresholdOffset: 40 mm
Type - Door Panel Properties - Panel 1 - PanelDepth: 40 mm; PanelOperation: SWINGING; PanelWidth: 0.50625; PanelPosition: LEFT
Type - Door Panel Properties - Panel 2 - PanelDepth: 40 mm; PanelOperation: SWINGING; PanelWidth: 0.50625; PanelPosition: RIGHT
OverallHeight: 2600 mm; OverallWidth: 2000 mm; Classification: 1.10 IfcDoorStyle (uks) (RKAS BIM + ARCHICAD Classification)
Pset_DoorCommon - Reference: VU-02; ThermalTransmittance: 0; GlazingAreaFraction: 3.60413; IsExternal: yes
AR_Uks - 001_Nimetus: kahepoolne välisuks; 300_Tüüp: VU-02; 305_Ava_mõõt: 2 000x2 600; 310_Materjal: metall; 315_Avanemine: pöördavanev ; ARCHICAD tüüp: Side Hung; 320_Klaas: 3xklaaspakett; 325_Helipidavus: Rw≥35dB; 330_Tulekindlus: nõudeid ei esitata; 335_Välispiire: yes; 340_Soojusläbivus: 1.1; 345_Päikesekiirgus_tegur: 0,4; 350_Klaaspakett: 3k (6+4+10); 355_Pindala: 5.2 m2; 360_Ratastooliga: yes; 365_Isesulguv: yes; 370_Evakuatsiooniväljapääs: yes; 375_Viimistlus_seest: MUDELIS: Metal - Stainless Steel; Metal - Stainless Steel; MÄRKUS:; 376_Viimistlus_väljast: MUDELIS: Metal - Stainless Steel; Metal - Stainless Steel; MÄRKUS:; 380_Lukustus: elektriline; 900_Tootja: Undefined; 905_Mudel: Undefined; 910_Tooteinfo: Undefined; 915_Kasutus-ja_hooldusjuhend: Undefined
AC_Pset_RenovationAndPhasing - Renovation Status: New

# IfcDoor: Exterior Double Sliding Door 23, LU-01
In: Teine korrus
Type - OperationType: DOUBLE_DOOR_SLIDING; ParameterTakesPrecedence: no; Sizeable: no
Type - Door Lining Properties - ThresholdDepth: 75 mm; ThresholdThickness: 12 mm; ThresholdOffset: 180 mm
Type - Door Panel Properties - Panel 1 - PanelDepth: 40 mm; PanelOperation: SLIDING; PanelWidth: 0.5; PanelPosition: RIGHT
Type - Door Panel Properties - Panel 2 - PanelDepth: 40 mm; PanelOperation: SLIDING; PanelWidth: 0.5; PanelPosition: LEFT
OverallHeight: 2100 mm; OverallWidth: 1800 mm; Classification: 1.10 IfcDoorStyle (uks) (RKAS BIM + ARCHICAD Classification)
Pset_DoorCommon - Reference: LU-01; ThermalTransmittance: 0; IsExternal: no
AR_Uks - 001_Nimetus: lükanduks; 300_Tüüp: LU-01; 305_Ava_mõõt: 1 800x2 100; 310_Materjal: puit-alumiinium; 315_Avanemine: lükanduks; ARCHICAD tüüp: External 2 Sliding; 320_Klaas: ilma klaasita; 325_Helipidavus: 30dB; 330_Tulekindlus: nõudeid ei esitata; 335_Välispiire: no; 340_Soojusläbivus: 0; 345_Päikesekiirgus_tegur: nõudeid ei esitata; 350_Klaaspakett: ilma klaasita; 355_Pindala: 3.78 m2; 360_Ratastooliga: no; 365_Isesulguv: no; 370_Evakuatsiooniväljapääs: no; 375_Viimistlus_seest: MUDELIS: Wood - Pine Grained Horizontal; Wood - Pine Grained Horizontal; MÄRKUS:; 376_Viimistlus_väljast: MUDELIS: Wood - Pine Grained Horizontal; Wood - Pine Grained Horizontal; MÄRKUS:; 380_Lukustus: mehaaniline; 900_Tootja: Undefined; 905_Mudel: Undefined; 910_Tooteinfo: Undefined; 915_Kasutus-ja_hooldusjuhend: Undefined
AC_Pset_RenovationAndPhasing - Renovation Status: New

# IfcDoor: Sliding Folding Multipanel Door 23, VOU-01
In: Esimene korrus
Type - OperationType: FOLDING_TO_RIGHT; ParameterTakesPrecedence: no; Sizeable: no
Type - Door Lining Properties - LiningDepth: 115 mm; LiningThickness: 40 mm; ThresholdDepth: 75 mm; ThresholdThickness: 12 mm; LiningOffset: -25 mm; ThresholdOffset: -100 mm
Type - Door Panel Properties - Panel 1 - PanelDepth: 50 mm; PanelOperation: FOLDING; PanelWidth: 0.108503; PanelPosition: LEFT
Type - Door Panel Properties - Panel 2 - PanelDepth: 50 mm; PanelOperation: FOLDING; PanelWidth: 0.108503; PanelPosition: LEFT
Type - Door Panel Properties - Panel 3 - PanelDepth: 50 mm; PanelOperation: FOLDING; PanelWidth: 0.108503; PanelPosition: LEFT
Type - Door Panel Properties - Panel 4 - PanelDepth: 50 mm; PanelOperation: FOLDING; PanelWidth: 0.108503; PanelPosition: LEFT
Type - Door Panel Properties - Panel 5 - PanelDepth: 50 mm; PanelOperation: FOLDING; PanelWidth: 0.108503; PanelPosition: LEFT
Type - Door Panel Properties - Panel 6 - PanelDepth: 50 mm; PanelOperation: FOLDING; PanelWidth: 0.108503; PanelPosition: LEFT
Type - Door Panel Properties - Panel 7 - PanelDepth: 50 mm; PanelOperation: FOLDING; PanelWidth: 0.108503; PanelPosition: LEFT
Type - Door Panel Properties - Panel 8 - PanelDepth: 50 mm; PanelOperation: FOLDING; PanelWidth: 0.108503; PanelPosition: LEFT
Type - Door Panel Properties - Panel 9 - PanelDepth: 50 mm; PanelOperation: FOLDING; PanelWidth: 0.108503; PanelPosition: LEFT
Type - Door Panel Properties - Panel 10 - PanelDepth: 50 mm; PanelOperation: FOLDING; PanelWidth: 0.108503; PanelPosition: LEFT
OverallHeight: 2600 mm; OverallWidth: 6460.01 mm; Classification: 1.10 IfcDoorStyle (uks) (RKAS BIM + ARCHICAD Classification)
Pset_DoorCommon - Reference: VOU-01; ThermalTransmittance: 0; IsExternal: no
AR_Uks - 001_Nimetus: voldikuks; 300_Tüüp: VOU-01; 305_Ava_mõõt: 6 460x2 600; 310_Materjal: puit-alumiinium; 315_Avanemine: voldikuks; ARCHICAD tüüp: Sliding Folding Multi-panel; 320_Klaas: ilma klaasita; 325_Helipidavus: Rw≥40 dB; 330_Tulekindlus: nõudeid ei esitata; 335_Välispiire: no; 340_Soojusläbivus: 0; 345_Päikesekiirgus_tegur: nõudeid ei esitata; 350_Klaaspakett: nõudeid ei esitata; 355_Pindala: 16.796 m2; 360_Ratastooliga: no; 365_Isesulguv: no; 370_Evakuatsiooniväljapääs: no; 375_Viimistlus_seest: MUDELIS: Wood - Pine Grained Horizontal; Wood - Pine Grained Horizontal; MÄRKUS:; 376_Viimistlus_väljast: MUDELIS: Wood - Pine Grained Horizontal; Wood - Pine Grained Horizontal; MÄRKUS:; 380_Lukustus: mehaaniline; 900_Tootja: Undefined; 905_Mudel: Undefined; 910_Tooteinfo: Undefined; 915_Kasutus-ja_hooldusjuhend: Undefined
AC_Pset_RenovationAndPhasing - Renovation Status: New

# IfcDoor: Vertical Sliding Garage Door 23, TV-41
In: Esimene korrus
Type - OperationType: ROLLINGUP; ParameterTakesPrecedence: no; Sizeable: no
Type - Door Lining Properties - LiningDepth: 100 mm; LiningThickness: 50 mm; LiningOffset: -125 mm
Type - Door Panel Properties - Panel 1 - PanelDepth: 40 mm; PanelOperation: ROLLINGUP; PanelWidth: 1; PanelPosition: MIDDLE
OverallHeight: 2700 mm; OverallWidth: 2400 mm; Classification: 1.10 IfcDoorStyle (uks) (RKAS BIM + ARCHICAD Classification)
AR_Uks - 340_Soojusläbivus: 0; 001_Nimetus: tõstvärav; 300_Tüüp: TV-41; 305_Ava_mõõt: 2 400x2 700; 310_Materjal: Alumiinium; 315_Avanemine: tõstvärav; 320_Klaas: ilma klaasita; 325_Helipidavus: nõudeid ei esitata; 330_Tulekindlus: nõudeid ei esitata; 335_Välispiire: yes; 345_Päikesekiirgus_tegur: nõudeid ei esitata; 350_Klaaspakett: ilma klaasita; 355_Pindala: 6.48 m2; 360_Ratastooliga: no; 365_Isesulguv: yes; 370_Evakuatsiooniväljapääs: yes; 375_Viimistlus_seest: MUDELIS: Plastic - Laminate; Glass - Clear Fast; MÄRKUS:; 376_Viimistlus_väljast: MUDELIS: Plastic - Laminate; Glass - Clear Fast; MÄRKUS:; 380_Lukustus: elektriline; 900_Tootja: Undefined; 905_Mudel: Undefined; 910_Tooteinfo: Undefined; 915_Kasutus-ja_hooldusjuhend: Undefined
Pset_DoorCommon - Reference: TV-41; ThermalTransmittance: 0; IsExternal: yes
AC_Pset_RenovationAndPhasing - Renovation Status: New

# IfcDoor: Vertical Sliding Garage Door 23, TV-42
In: Esimene korrus
Type - OperationType: ROLLINGUP; ParameterTakesPrecedence: no; Sizeable: no
Type - Door Lining Properties - LiningDepth: 100 mm; LiningThickness: 50 mm; LiningOffset: 100 mm
Type - Door Panel Properties - Panel 1 - PanelDepth: 40 mm; PanelOperation: ROLLINGUP; PanelWidth: 1; PanelPosition: MIDDLE
OverallHeight: 2700 mm; OverallWidth: 2000 mm; Classification: 1.10 IfcDoorStyle (uks) (RKAS BIM + ARCHICAD Classification)
AR_Uks - 340_Soojusläbivus: 0; 001_Nimetus: rullvärav; 300_Tüüp: TV-42; 305_Ava_mõõt: 2 000x2 700; 310_Materjal: Alumiinium; 315_Avanemine: tõstvärav; 320_Klaas: ilma klaasita; 325_Helipidavus: nõudeid ei esitata; 330_Tulekindlus: nõudeid ei esitata; 335_Välispiire: yes; 345_Päikesekiirgus_tegur: nõudeid ei esitata; 350_Klaaspakett: ilma klaasita; 355_Pindala: 5.4 m2; 360_Ratastooliga: no; 365_Isesulguv: no; 370_Evakuatsiooniväljapääs: yes; 375_Viimistlus_seest: MUDELIS: Plastic - Laminate; Glass - Clear Fast; MÄRKUS:; 376_Viimistlus_väljast: MUDELIS: Plastic - Laminate; Glass - Clear Fast; MÄRKUS:; 380_Lukustus: mehaaniline; 900_Tootja: Undefined; 905_Mudel: Undefined; 910_Tooteinfo: Undefined; 915_Kasutus-ja_hooldusjuhend: Undefined
Pset_DoorCommon - Reference: TV-42; ThermalTransmittance: 0; IsExternal: yes
AC_Pset_RenovationAndPhasing - Renovation Status: New

# IfcDoor: Vertical Sliding Garage Door 23, TV-06
In: Esimene korrus
Type - OperationType: ROLLINGUP; ParameterTakesPrecedence: no; Sizeable: no
Type - Door Lining Properties - LiningDepth: 100 mm; LiningThickness: 50 mm; ThresholdDepth: 75 mm; ThresholdThickness: 12 mm; LiningOffset: -200 mm; ThresholdOffset: -160 mm
Type - Door Panel Properties - Panel 1 - PanelDepth: 40 mm; PanelOperation: ROLLINGUP; PanelWidth: 1; PanelPosition: MIDDLE
OverallHeight: 2400 mm; OverallWidth: 1800 mm; Classification: 1.10 IfcDoorStyle (uks) (RKAS BIM + ARCHICAD Classification)
AR_Uks - 340_Soojusläbivus: 0; 001_Nimetus: tõstvärav; 300_Tüüp: TV-06; 305_Ava_mõõt: 1 800x2 400; 310_Materjal: Alumiinium; 315_Avanemine: tõstvärav; 320_Klaas: ilma klaasita; 325_Helipidavus: nõudeid ei esitata; 330_Tulekindlus: nõudeid ei esitata; 335_Välispiire: no; 345_Päikesekiirgus_tegur: nõudeid ei esitata; 350_Klaaspakett: ilma klaasita; 355_Pindala: 4.32 m2; 360_Ratastooliga: no; 365_Isesulguv: yes; 370_Evakuatsiooniväljapääs: yes; 375_Viimistlus_seest: MUDELIS: Plastic - Laminate; Glass - Clear Fast; MÄRKUS:; 376_Viimistlus_väljast: MUDELIS: Plastic - Laminate; Glass - Clear Fast; MÄRKUS:; 380_Lukustus: mehaaniline; 900_Tootja: Undefined; 905_Mudel: Undefined; 910_Tooteinfo: Undefined; 915_Kasutus-ja_hooldusjuhend: Undefined
Pset_DoorCommon - Reference: TV-06; ThermalTransmittance: 0; IsExternal: no
AC_Pset_RenovationAndPhasing - Renovation Status: New

# IfcDoor: Vertical Sliding Garage Door 23 (5)
In: Esimene korrus
Type - OperationType: ROLLINGUP; ParameterTakesPrecedence: no; Sizeable: no
Type - Door Lining Properties - LiningDepth: 100 mm; LiningThickness: 50 mm; ThresholdDepth: 75 mm; ThresholdThickness: 12 mm; LiningOffset: -275 mm; ThresholdOffset: -235 mm
Type - Door Panel Properties - Panel 1 - PanelDepth: 40 mm; PanelOperation: ROLLINGUP; PanelWidth: 1; PanelPosition: MIDDLE
OverallHeight: 4200 mm; OverallWidth: 3500 mm; Classification: 1.10 IfcDoorStyle (uks) (RKAS BIM + ARCHICAD Classification)
AR_Uks - 340_Soojusläbivus: 0; 001_Nimetus: tõstvärav; 300_Tüüp: TV-21; 305_Ava_mõõt: 3 500x4 200; 315_Avanemine: tõstvärav; 320_Klaas: 3xakrüülklaas; 325_Helipidavus: nõudeid ei esitata; 330_Tulekindlus: nõudeid ei esitata; 335_Välispiire: yes; 345_Päikesekiirgus_tegur: nõudeid ei esitata; 350_Klaaspakett: 3xakrüülklaas; 355_Pindala: 14.7 m2; 360_Ratastooliga: no; 365_Isesulguv: yes; 370_Evakuatsiooniväljapääs: yes; 375_Viimistlus_seest: MUDELIS: Plastic - Laminate; Glass - Clear Fast; MÄRKUS:; 376_Viimistlus_väljast: MUDELIS: Plastic - Laminate; Glass - Clear Fast; MÄRKUS:; 380_Lukustus: elektriline; 900_Tootja: Undefined; 905_Mudel: Undefined; 910_Tooteinfo: Undefined; 915_Kasutus-ja_hooldusjuhend: Undefined
Pset_DoorCommon - Reference: TV-21; ThermalTransmittance: 0; IsExternal: yes
AC_Pset_RenovationAndPhasing - Renovation Status: New
Name | 310_Materjal
4 x TV-21 | Alumiinium
TV-21 | Alumiiinium

# IfcDoor: Vertical Sliding Garage Door 23, TV-04
In: Esimene korrus
Type - OperationType: ROLLINGUP; ParameterTakesPrecedence: no; Sizeable: no
Type - Door Lining Properties - LiningDepth: 100 mm; LiningThickness: 50 mm; ThresholdDepth: 75 mm; ThresholdThickness: 12 mm; LiningOffset: -510 mm; ThresholdOffset: -470 mm
Type - Door Panel Properties - Panel 1 - PanelDepth: 40 mm; PanelOperation: ROLLINGUP; PanelWidth: 1; PanelPosition: MIDDLE
OverallHeight: 2800 mm; OverallWidth: 3000 mm; Classification: 1.10 IfcDoorStyle (uks) (RKAS BIM + ARCHICAD Classification)
AR_Uks - 340_Soojusläbivus: 0; 001_Nimetus: tõstvärav; 300_Tüüp: TV-04; 305_Ava_mõõt: 3 000x2 800; 310_Materjal: Alumiinium; 315_Avanemine: tõstvärav; 320_Klaas: ilma klaasita; 325_Helipidavus: 24dB; 330_Tulekindlus: nõudeid ei esitata; 335_Välispiire: yes; 345_Päikesekiirgus_tegur: nõudeid ei esitata; 350_Klaaspakett: ilma klaasita; 355_Pindala: 8.4 m2; 360_Ratastooliga: no; 365_Isesulguv: yes; 370_Evakuatsiooniväljapääs: yes; 375_Viimistlus_seest: MUDELIS: Plastic - Laminate; Glass - Clear Fast; MÄRKUS:; 376_Viimistlus_väljast: MUDELIS: Plastic - Laminate; Glass - Clear Fast; MÄRKUS:; 380_Lukustus: elektriline; 900_Tootja: Undefined; 905_Mudel: Undefined; 910_Tooteinfo: Undefined; 915_Kasutus-ja_hooldusjuhend: Undefined
Pset_DoorCommon - Reference: TV-04; ThermalTransmittance: 0; IsExternal: yes
AC_Pset_RenovationAndPhasing - Renovation Status: New

# IfcDoor: Vertical Sliding Garage Door 23 (12)
In: Esimene korrus
Type - OperationType: ROLLINGUP; ParameterTakesPrecedence: no; Sizeable: no
Type - Door Lining Properties - LiningDepth: 100 mm; LiningThickness: 50 mm; ThresholdDepth: 75 mm; ThresholdThickness: 12 mm; LiningOffset: 650 mm; ThresholdOffset: 590 mm
Type - Door Panel Properties - Panel 1 - PanelDepth: 40 mm; PanelOperation: ROLLINGUP; PanelWidth: 1; PanelPosition: MIDDLE
Classification: 1.10 IfcDoorStyle (uks) (RKAS BIM + ARCHICAD Classification)
Pset_DoorCommon - ThermalTransmittance: 0; IsExternal: yes
AR_Uks - 001_Nimetus: tõstvärav; 310_Materjal: Alumiinium; 315_Avanemine: tõstvärav; 320_Klaas: 3xakrüülklaas; 325_Helipidavus: 24dB; 330_Tulekindlus: nõudeid ei esitata; 335_Välispiire: yes; 340_Soojusläbivus: 2.3; 345_Päikesekiirgus_tegur: nõudeid ei esitata; 350_Klaaspakett: nõudeid ei esitata; 360_Ratastooliga: no; 365_Isesulguv: yes; 370_Evakuatsiooniväljapääs: yes; 380_Lukustus: elektriline; 900_Tootja: Undefined; 905_Mudel: Undefined; 910_Tooteinfo: Undefined; 915_Kasutus-ja_hooldusjuhend: Undefined
AC_Pset_RenovationAndPhasing - Renovation Status: New
Name | OverallHeight (mm) | OverallWidth (mm) | Reference = 300_Tüüp | 305_Ava_mõõt | 355_Pindala (m2) | 375_Viimistlus_seest = 376_Viimistlus_väljast
4 x TV-07 | 4400 | 4000 | TV-07 | 4 000x4 400 | 17.6 | MUDELIS: Paint - Anthracite; Glass - Clear Fast; MÄRKUS:
TV-01 | 2800 | 3500 | TV-01 | 3500x2800 | 9.8 | MUDELIS: Metal - Stainless Steel; Glass-Clear; MÄRKUS:
4 x TV-02 | 4400 | 4000 | TV-02 | 4 000x4 400 | 17.6 | MUDELIS: Paint - Anthracite; Glass - Clear Fast; MÄRKUS:
TV-05 | 4400 | 4000 | TV-05 | 4 000x4 400 | 17.6 | MUDELIS: Paint - Anthracite; Glass - Clear Fast; MÄRKUS:
2 x TV-03 | 4400 | 3500 | TV-03 | 3 500x4 400 | 15.4 | MUDELIS: Paint - Anthracite; Glass - Clear Fast; MÄRKUS:

# IfcFurnishingElement: Puit - Põrand 25 (6)
In: Teine korrus
Classification: 1.11 IfcFurnitureType (mööbel) (RKAS BIM + ARCHICAD Classification); Material: Puit - Põrand
AC_Pset_RenovationAndPhasing - Renovation Status: New

# IfcFurnishingElement: SKR-05_Vineer 25 (12)
In: Teine korrus
Classification: 1.11 IfcFurnitureType (mööbel) (RKAS BIM + ARCHICAD Classification); Material: SKR-05_Vineer
AR_Sein - 340_Soojusläbivus: 0
AC_Pset_RenovationAndPhasing - Renovation Status: New

# IfcMember: IfcMember (10)
Type - ElementType: Stair Structure; PredefinedType: USERDEFINED
Classification: Stair Structure (RKAS BIM + ARCHICAD Classification)
AC_Pset_RenovationAndPhasing - Renovation Status: New
Name | In | Material
TREPP 04 | Vundament | KON-04_Betoon - Konstuktsioon
4 x TT KONSTRUKTSIOON - 002 | Esimene korrus | KON-04_Betoon - Konstuktsioon
2 x TT KONSTRUKTSIOON - 002 | Esimene korrus | ET-06_Teras - Konstruktsioon
TREPP 04 | Teine korrus | KON-04_Betoon - Konstuktsioon
2 x TT KONSTRUKTSIOON - 002 | Teine korrus | ET-06_Teras - Konstruktsioon

# IfcPlate: Teras 60 (2)
In: Teine korrus
Classification: 1.15 IfcPlateType (plaat) (RKAS BIM + ARCHICAD Classification); Material: Teras
Pset_PlateCommon - Reference: Teras; LoadBearing: yes; IsExternal: no
AR_001-002 - 001_Nimetus: Seisuplatvorm; 002_Tüüp: Teras
AC_Pset_RenovationAndPhasing - Renovation Status: New

# IfcRailing: Railing Type (46)
Classification: 1.16 IfcRailingType (piire) (RKAS BIM + ARCHICAD Classification)
AC_Pset_RenovationAndPhasing - Renovation Status: New
Name | In | IsExternal
3 x PIIRE 2 | Esimene korrus | no
3 x PIIRE 2 | Teine korrus | yes
2 x PIIRE 11 | Teine korrus | no
5 x PIIRE 2 | Teine korrus | no
TREPIPIIR 1 | Teine korrus | no
TREPIPIIRE 4 | Teine korrus | no
TREPIPIIRE 5 | Teine korrus | no
TREPIPIIRE 3 | Teine korrus | no
TREPIPIIRE 2 | Teine korrus | no
TREPIPIIRE 6 | Teine korrus | no
TREPIPIIRE 7 | Teine korrus | no
2 x PIIRE 5 | Teine korrus | no
2 x PIIRE 12 | Teine korrus | no
2 x PIIRE 13 | Teine korrus | no
15 x PIIRE 2 | Katusekorrus | yes
4 x PIIRE 2 | Katusekorrus | no
RÕDUPIIRE 11 | Katusekorrus | yes

# IfcSlab: KL-01_Katuslagi paneel 220 680 (4)
Type - PredefinedType: ROOF
Classification: 1.19 IfcSlabType.ROOF (katus) (RKAS BIM + ARCHICAD Classification)
Pset_SlabCommon - Reference: KL-01; LoadBearing: yes; IsExternal: yes
AR_Katus - 001_Nimetus: Katuslagi; 205_Tüüp: KL-01; 325_Helipidavus: nõudeid ei esitata; 330_Tulekindlus: R60
AR_Vahelagi - 001_Nimetus: Katuslagi; 205_Tüüp: KL-01; 325_Helipidavus: nõudeid ei esitata; 330_Tulekindlus: R60
AC_Pset_RenovationAndPhasing - Renovation Status: New
Name | In | AR_Katus, 340_Soojusläbivus = AR_Vahelagi, 340_Soojusläbivus | 520_Pindala (m2)
KL-01 | Teine korrus | 0 | 43.0273
KL-01 | Katusekorrus | 0.07 | 233.564
KL-01 | Katusekorrus | 0.07 | 270.131
KL-01 | Katusekorrus | 0.07 | 86.4436

# IfcSlab: KL-02_Katuslagi paneel 400 860 (3)
Type - PredefinedType: ROOF
Classification: 1.19 IfcSlabType.ROOF (katus) (RKAS BIM + ARCHICAD Classification)
Pset_SlabCommon - Reference: KL-02; LoadBearing: yes; IsExternal: yes
AR_Katus - 001_Nimetus: Katuslagi; 205_Tüüp: KL-02; 325_Helipidavus: nõudeid ei esitata; 330_Tulekindlus: R60
AR_Vahelagi - 001_Nimetus: Katuslagi; 205_Tüüp: KL-02; 325_Helipidavus: nõudeid ei esitata; 330_Tulekindlus: R60
AC_Pset_RenovationAndPhasing - Renovation Status: New
Name | In | AR_Katus, 340_Soojusläbivus = AR_Vahelagi, 340_Soojusläbivus | 520_Pindala (m2)
KL-04 | Teine korrus | 0 | 24.7371
KL-02 | Katusekorrus | 0.07 | 279.611
KL-02 | Katusekorrus | 0.07 | 425.851

# IfcSlab: KL-03_Katuslagi varikatus 470, KL-03
In: Katusekorrus
Classification: 1.20 IfcSlabType (vahelagi) (RKAS BIM + ARCHICAD Classification)
AR_Katus - 520_Pindala: 0 m2; 001_Nimetus: Varikatus; 205_Tüüp: KL-03; 325_Helipidavus: nõudeid ei esitata; 330_Tulekindlus: nõudeid ei esitata
Pset_SlabCommon - Reference: KL-03; LoadBearing: yes; IsExternal: yes
AR_Vahelagi - 001_Nimetus: Varikatus; 205_Tüüp: KL-03; 325_Helipidavus: nõudeid ei esitata; 330_Tulekindlus: nõudeid ei esitata; 335_Välispiire: yes; 500_Kandev: TRUE; 505_Paksus: 470 mm; 510_Bruto_pindala: 90.7248 m2; 515_Neto_pindala: 90.7248 m2
AC_Pset_RenovationAndPhasing - Renovation Status: New

# IfcSlab: KL-04_Katuslagi paneel 265 copy 725 (2)
In: Katusekorrus
Type - PredefinedType: ROOF
Classification: 1.19 IfcSlabType.ROOF (katus) (RKAS BIM + ARCHICAD Classification)
Pset_SlabCommon - Reference: KL-04; LoadBearing: yes; IsExternal: yes
AR_Katus - 001_Nimetus: Katuslagi; 205_Tüüp: KL-04; 325_Helipidavus: nõudeid ei esitata; 330_Tulekindlus: R60
AR_Vahelagi - 001_Nimetus: Katuslagi; 205_Tüüp: KL-04; 325_Helipidavus: nõudeid ei esitata; 330_Tulekindlus: R60
AC_Pset_RenovationAndPhasing - Renovation Status: New
Name | 520_Pindala (m2)
KL-04 | 99.9408 | AR_Katus - 340_Soojusläbivus: 0; AR_Vahelagi - 340_Soojusläbivus: 0
KL-04 | 140.63

# IfcSlab: KL-05_Katuslagi paneel 220 õhuhaare 780, KL-05
In: Katusekorrus
Type - PredefinedType: ROOF
Classification: 1.19 IfcSlabType.ROOF (katus) (RKAS BIM + ARCHICAD Classification)
Pset_SlabCommon - Reference: KL-05; LoadBearing: yes; IsExternal: yes
AR_Katus - 001_Nimetus: Katuslagi; 205_Tüüp: KL-05; 325_Helipidavus: nõudeid ei esitata; 330_Tulekindlus: R60; 340_Soojusläbivus: 0.07; 520_Pindala: 7.17984 m2
AR_Vahelagi - 001_Nimetus: Katuslagi; 205_Tüüp: KL-05; 325_Helipidavus: nõudeid ei esitata; 330_Tulekindlus: R60; 340_Soojusläbivus: 0.07
AC_Pset_RenovationAndPhasing - Renovation Status: New

# IfcSlab: KL-06_Katuslagi vooliku torn 470, KL-06
In: Korrus +9.900
Type - PredefinedType: ROOF
Classification: 1.19 IfcSlabType.ROOF (katus) (RKAS BIM + ARCHICAD Classification)
Pset_SlabCommon - Reference: KL-06; LoadBearing: yes; IsExternal: yes
AR_Katus - 001_Nimetus: Katuslagi; 205_Tüüp: KL-06; 325_Helipidavus: nõudeid ei esitata; 330_Tulekindlus: R60; 340_Soojusläbivus: 0.07; 520_Pindala: 11.2881 m2
AR_Vahelagi - 001_Nimetus: Katuslagi; 205_Tüüp: KL-06; 325_Helipidavus: nõudeid ei esitata; 330_Tulekindlus: R60; 340_Soojusläbivus: 0.07
AC_Pset_RenovationAndPhasing - Renovation Status: New

# IfcSlab: KL-07_Katuslagi paneel 220 + kalle 300, KL-07
In: Teine korrus
Type - PredefinedType: ROOF
Classification: 1.19 IfcSlabType.ROOF (katus) (RKAS BIM + ARCHICAD Classification)
Pset_SlabCommon - Reference: KL-07; LoadBearing: yes; IsExternal: yes
AR_Katus - 001_Nimetus: Katuslagi; 205_Tüüp: KL-07; 325_Helipidavus: nõudeid ei esitata; 330_Tulekindlus: R60; 340_Soojusläbivus: 0; 520_Pindala: 18.045 m2
AR_Vahelagi - 001_Nimetus: Katuslagi; 205_Tüüp: KL-07; 325_Helipidavus: nõudeid ei esitata; 330_Tulekindlus: R60; 340_Soojusläbivus: 0
AC_Pset_RenovationAndPhasing - Renovation Status: Existing

# IfcSlab: KL-20_Katuslagi harjutustorn 275, KL-20
In: Korrus +9.900
Type - PredefinedType: ROOF
Classification: 1.19 IfcSlabType.ROOF (katus) (RKAS BIM + ARCHICAD Classification)
Pset_SlabCommon - Reference: KL-20; LoadBearing: yes; IsExternal: yes
AR_Katus - 205_Tüüp: KL-20; 325_Helipidavus: nõudeid ei esitata; 330_Tulekindlus: nõudeid ei esitata; 520_Pindala: 23.0497 m2
AR_Vahelagi - 205_Tüüp: KL-20; 325_Helipidavus: nõudeid ei esitata; 330_Tulekindlus: nõudeid ei esitata
AC_Pset_RenovationAndPhasing - Renovation Status: New

# IfcSlab: KL-21_torn liigutatav katus 105, KATUS
In: Katusekorrus
Type - PredefinedType: ROOF
Classification: 1.19 IfcSlabType.ROOF (katus) (RKAS BIM + ARCHICAD Classification)
AR_Katus - 340_Soojusläbivus: 0; 205_Tüüp: KL-21; 325_Helipidavus: nõudeid ei esitata; 330_Tulekindlus: nõudeid ei esitata; 520_Pindala: 15.083 m2
Pset_SlabCommon - Reference: KL-21; LoadBearing: yes; IsExternal: yes
AR_Vahelagi - 205_Tüüp: KL-21; 325_Helipidavus: nõudeid ei esitata; 330_Tulekindlus: nõudeid ei esitata
AC_Pset_RenovationAndPhasing - Renovation Status: New

# IfcSlab: KL-31_Katuslagi konteinerite garaaz 110, KL-31
In: Katusekorrus
Type - PredefinedType: ROOF
Classification: 1.19 IfcSlabType.ROOF (katus) (RKAS BIM + ARCHICAD Classification)
Pset_SlabCommon - Reference: KL-31; LoadBearing: yes; IsExternal: yes
AR_Katus - 205_Tüüp: KL-31; 325_Helipidavus: nõudeid ei esitata; 330_Tulekindlus: nõudeid ei esitata; 520_Pindala: 268.681 m2
AR_Vahelagi - 205_Tüüp: KL-31; 325_Helipidavus: nõudeid ei esitata; 330_Tulekindlus: nõudeid ei esitata
AC_Pset_RenovationAndPhasing - Renovation Status: New

# IfcSlab: KL-41_Katuslagi PPA varjualune 110, KL-41
In: Katusekorrus
Type - PredefinedType: ROOF
Classification: 1.19 IfcSlabType.ROOF (katus) (RKAS BIM + ARCHICAD Classification)
Pset_SlabCommon - Reference: KL-41; LoadBearing: yes; IsExternal: yes
AR_Katus - 205_Tüüp: KL-41; 325_Helipidavus: nõudeid ei esitata; 330_Tulekindlus: nõudeid ei esitata; 520_Pindala: 111.273 m2
AR_Vahelagi - 205_Tüüp: KL-41; 325_Helipidavus: nõudeid ei esitata; 330_Tulekindlus: nõudeid ei esitata
AC_Pset_RenovationAndPhasing - Renovation Status: New

# IfcSlab: KL-61_Katuslagi lõhkeainehoidla 300, KL-61
In: Teine korrus
Type - PredefinedType: ROOF
Classification: 1.19 IfcSlabType.ROOF (katus) (RKAS BIM + ARCHICAD Classification); Material: KON-04_Betoon - Konstuktsioon 300 mm
AR_Katus - 340_Soojusläbivus: 0; 205_Tüüp: KL-61; 325_Helipidavus: nõudeid ei esitata; 330_Tulekindlus: nõudeid ei esitata; 520_Pindala: 16.8 m2
Pset_SlabCommon - Reference: KL-61; LoadBearing: yes; IsExternal: yes
AR_Vahelagi - 205_Tüüp: KL-61; 325_Helipidavus: nõudeid ei esitata; 330_Tulekindlus: nõudeid ei esitata
AC_Pset_RenovationAndPhasing - Renovation Status: New

# IfcSlab: PP-01_Põrand pinnasel - garaaz 700 (2)
In: Esimene korrus
Classification: 1.20 IfcSlabType (vahelagi) (RKAS BIM + ARCHICAD Classification)
AR_Katus - 520_Pindala: 0 m2; 001_Nimetus: Põrandpinnasel; 205_Tüüp: PP-01; 325_Helipidavus: Nõudeid ei esitata; 330_Tulekindlus: nõudeid ei esitata; 340_Soojusläbivus: 0.1
Pset_SlabCommon - Reference: PP-01; LoadBearing: yes; IsExternal: yes
AR_Vahelagi - 001_Nimetus: Põrandpinnasel; 205_Tüüp: PP-01; 325_Helipidavus: Nõudeid ei esitata; 330_Tulekindlus: nõudeid ei esitata; 335_Välispiire: yes; 340_Soojusläbivus: 0.1; 500_Kandev: TRUE; 505_Paksus: 700 mm
AC_Pset_RenovationAndPhasing - Renovation Status: New
Name | 510_Bruto_pindala (m2) | 515_Neto_pindala (m2)
PP-01 | 271.234 | 268.716
PP-01 | 500.849 | 483.149

# IfcSlab: PP-02_Põrand pinnasel 650 (3)
In: Esimene korrus
Classification: 1.20 IfcSlabType (vahelagi) (RKAS BIM + ARCHICAD Classification)
AR_Katus - 520_Pindala: 0 m2; 001_Nimetus: Põrandpinnasel; 205_Tüüp: PP-02; 325_Helipidavus: Nõudeid ei esitata; 330_Tulekindlus: nõudeid ei esitata; 340_Soojusläbivus: 0.1
Pset_SlabCommon - Reference: PP-02; LoadBearing: yes; IsExternal: yes
AR_Vahelagi - 001_Nimetus: Põrandpinnasel; 205_Tüüp: PP-02; 325_Helipidavus: Nõudeid ei esitata; 330_Tulekindlus: nõudeid ei esitata; 335_Välispiire: yes; 340_Soojusläbivus: 0.1; 500_Kandev: TRUE; 505_Paksus: 650 mm
AC_Pset_RenovationAndPhasing - Renovation Status: New
Name | 510_Bruto_pindala (m2) | 515_Neto_pindala (m2)
PP-02 | 378.737 | 377.997
PP-02 | 318.749 | 318.577
PP-02 | 95.049 | 93.9765

# IfcSlab: PP-03_remondikanali põrand 700, PP-03
In: Vundament
Classification: 1.20 IfcSlabType (vahelagi) (RKAS BIM + ARCHICAD Classification)
Pset_SlabCommon - Reference: PP-03; LoadBearing: yes; IsExternal: yes
AR_Katus - 001_Nimetus: Põrandpinnasel; 205_Tüüp: PP-03; 325_Helipidavus: nõudeid ei esitata; 330_Tulekindlus: nõudeid ei esitata
AR_Vahelagi - 001_Nimetus: Põrandpinnasel; 205_Tüüp: PP-03; 325_Helipidavus: nõudeid ei esitata; 330_Tulekindlus: nõudeid ei esitata; 335_Välispiire: yes; 500_Kandev: TRUE; 505_Paksus: 700 mm; 510_Bruto_pindala: 16.125 m2; 515_Neto_pindala: 12.8125 m2
AC_Pset_RenovationAndPhasing - Renovation Status: New

# IfcSlab: PP-04_Põrand pinnasel 650, PP-04
In: Esimene korrus
Classification: 1.20 IfcSlabType (vahelagi) (RKAS BIM + ARCHICAD Classification)
AR_Katus - 520_Pindala: 0 m2; 001_Nimetus: Põrandpinnasel; 205_Tüüp: PP-04; 325_Helipidavus: Nõudeid ei esitata; 330_Tulekindlus: nõudeid ei esitata
Pset_SlabCommon - Reference: PP-04; LoadBearing: yes; IsExternal: yes
AR_Vahelagi - 001_Nimetus: Põrandpinnasel; 205_Tüüp: PP-04; 325_Helipidavus: Nõudeid ei esitata; 330_Tulekindlus: nõudeid ei esitata; 335_Välispiire: yes; 500_Kandev: TRUE; 505_Paksus: 650 mm; 510_Bruto_pindala: 16.7998 m2; 515_Neto_pindala: 16.3998 m2
AC_Pset_RenovationAndPhasing - Renovation Status: New

# IfcSlab: PP-05_Põrand pinnasel õhuhaare 997, PP-05
In: Esimene korrus
Classification: 1.20 IfcSlabType (vahelagi) (RKAS BIM + ARCHICAD Classification)
AR_Katus - 520_Pindala: 0 m2; 001_Nimetus: Põrandpinnasel; 205_Tüüp: PP-05; 325_Helipidavus: Nõudeid ei esitata; 330_Tulekindlus: nõudeid ei esitata; 340_Soojusläbivus: 0.1
Pset_SlabCommon - Reference: PP-05; LoadBearing: yes; IsExternal: yes
AR_Vahelagi - 001_Nimetus: Põrandpinnasel; 205_Tüüp: PP-05; 325_Helipidavus: Nõudeid ei esitata; 330_Tulekindlus: nõudeid ei esitata; 335_Välispiire: yes; 340_Soojusläbivus: 0.1; 500_Kandev: TRUE; 505_Paksus: 997 mm; 510_Bruto_pindala: 1.25261 m2; 515_Neto_pindala: 1.25261 m2
AC_Pset_RenovationAndPhasing - Renovation Status: New

# IfcSlab: PP-06_sissepääsu esine terrass 600 (2)
In: Esimene korrus
Classification: 1.20 IfcSlabType (vahelagi) (RKAS BIM + ARCHICAD Classification)
AR_Katus - 520_Pindala: 0 m2; 001_Nimetus: Põrandpinnasel; 205_Tüüp: PP-06; 325_Helipidavus: Nõudeid ei esitata; 330_Tulekindlus: nõudeid ei esitata
Pset_SlabCommon - Reference: PP-06; LoadBearing: yes; IsExternal: yes
AR_Vahelagi - 001_Nimetus: Põrandpinnasel; 205_Tüüp: PP-06; 325_Helipidavus: Nõudeid ei esitata; 330_Tulekindlus: nõudeid ei esitata; 335_Välispiire: yes; 500_Kandev: TRUE; 505_Paksus: 600 mm
AC_Pset_RenovationAndPhasing - Renovation Status: New
Name | 510_Bruto_pindala (m2) | 515_Neto_pindala (m2)
PP-06 | 28.8275 | 28.8275
PP-06 | 7.301 | 6.6962

# IfcSlab: PP-20_Põrand pinnasel harjutustorn 580, PP-20
In: Esimene korrus
Classification: 1.20 IfcSlabType (vahelagi) (RKAS BIM + ARCHICAD Classification)
AR_Katus - 520_Pindala: 0 m2; 001_Nimetus: Põrandpinnasel; 205_Tüüp: PP-20; 325_Helipidavus: nõudeid ei esitata; 330_Tulekindlus: nõudeid ei esitata
Pset_SlabCommon - Reference: PP-20; LoadBearing: yes; IsExternal: yes
AR_Vahelagi - 001_Nimetus: Põrandpinnasel; 205_Tüüp: PP-20; 325_Helipidavus: nõudeid ei esitata; 330_Tulekindlus: nõudeid ei esitata; 335_Välispiire: yes; 500_Kandev: TRUE; 505_Paksus: 580 mm; 510_Bruto_pindala: 26.2751 m2; 515_Neto_pindala: 24.0253 m2
AC_Pset_RenovationAndPhasing - Renovation Status: New

# IfcSlab: PP-21_Põrand pinnasel harjutustorn copy 630, PP-21
In: Vundament
Type - PredefinedType: ROOF
Classification: 1.19 IfcSlabType.ROOF (katus) (RKAS BIM + ARCHICAD Classification)
Pset_SlabCommon - Reference: PP-21; LoadBearing: yes; IsExternal: yes
AR_Katus - 001_Nimetus: pinnadspõrand; 205_Tüüp: PP-21; 325_Helipidavus: nõudeid ei esitata; 330_Tulekindlus: nõudeid ei esitata; 340_Soojusläbivus: 0; 520_Pindala: 2.24979 m2
AR_Vahelagi - 001_Nimetus: pinnadspõrand; 205_Tüüp: PP-21; 325_Helipidavus: nõudeid ei esitata; 330_Tulekindlus: nõudeid ei esitata; 340_Soojusläbivus: 0
AC_Pset_RenovationAndPhasing - Renovation Status: New

# IfcSlab: PP-30_Garaazi põrand pinnasel 500 (2)
In: Esimene korrus
Classification: 1.20 IfcSlabType (vahelagi) (RKAS BIM + ARCHICAD Classification)
AR_Katus - 520_Pindala: 0 m2; 205_Tüüp: PP-30; 325_Helipidavus: nõudeid ei esitata; 330_Tulekindlus: nõudeid ei esitata
Pset_SlabCommon - Reference: PP-30; LoadBearing: yes; IsExternal: yes
AR_Vahelagi - 205_Tüüp: PP-30; 325_Helipidavus: nõudeid ei esitata; 330_Tulekindlus: nõudeid ei esitata; 335_Välispiire: yes; 500_Kandev: TRUE; 505_Paksus: 500 mm
AC_Pset_RenovationAndPhasing - Renovation Status: New
Name | 510_Bruto_pindala (m2) = 515_Neto_pindala (m2)
PP-31 | 245.298
PP-41 | 97.1257 | AR_Katus - 001_Nimetus: Põrandpinnasel; AR_Vahelagi - 001_Nimetus: Põrandpinnasel

# IfcSlab: PP-60_Põrand pinnasel lõhkeainehoidla 750, PP-60
In: Esimene korrus
Classification: 1.20 IfcSlabType (vahelagi) (RKAS BIM + ARCHICAD Classification)
AR_Katus - 520_Pindala: 0 m2; 001_Nimetus: Põrandpinnasel; 205_Tüüp: PP-60; 325_Helipidavus: nõudeid ei esitata; 330_Tulekindlus: nõudeid ei esitata
Pset_SlabCommon - Reference: PP-60; LoadBearing: yes; IsExternal: no
AR_Vahelagi - 001_Nimetus: Põrandpinnasel; 205_Tüüp: PP-60; 325_Helipidavus: nõudeid ei esitata; 330_Tulekindlus: nõudeid ei esitata; 335_Välispiire: no; 500_Kandev: TRUE; 505_Paksus: 750 mm; 510_Bruto_pindala: 16.8 m2; 515_Neto_pindala: 16.8 m2
AC_Pset_RenovationAndPhasing - Renovation Status: New

# IfcSlab: VL-01_Vahelagi 340, VL-01
In: Teine korrus
Classification: 1.20 IfcSlabType (vahelagi) (RKAS BIM + ARCHICAD Classification)
AR_Katus - 520_Pindala: 0 m2; 001_Nimetus: Vahelagi; 205_Tüüp: VL-01; 325_Helipidavus: R'w=52 dB; 330_Tulekindlus: EI60; 340_Soojusläbivus: 0
Pset_SlabCommon - Reference: VL-01; LoadBearing: yes; IsExternal: no
AR_Vahelagi - 001_Nimetus: Vahelagi; 205_Tüüp: VL-01; 325_Helipidavus: R'w=52 dB; 330_Tulekindlus: EI60; 335_Välispiire: no; 340_Soojusläbivus: 0; 500_Kandev: TRUE; 505_Paksus: 340 mm; 510_Bruto_pindala: 318.896 m2; 515_Neto_pindala: 318.896 m2
AC_Pset_RenovationAndPhasing - Renovation Status: New

# IfcSlab: VL-03_Vahelagi 540 (2)
In: Teine korrus
Classification: 1.20 IfcSlabType (vahelagi) (RKAS BIM + ARCHICAD Classification)
Pset_SlabCommon - Reference: VL-03; LoadBearing: no
AR_Katus - 205_Tüüp: VL-03; 325_Helipidavus: Undefined; 330_Tulekindlus: Undefined
AR_Vahelagi - 205_Tüüp: VL-03; 325_Helipidavus: Undefined; 330_Tulekindlus: Undefined; 335_Välispiire: no; 500_Kandev: FALSE; 505_Paksus: 540 mm
AC_Pset_RenovationAndPhasing - Renovation Status: New
Name | 510_Bruto_pindala (m2) = 515_Neto_pindala (m2)
VL-03 | 17.0671
VL-03 | 4.76539

# IfcSlab: VL-04_Vahelagi 265 paneel 385, VL-04
In: Teine korrus
Type - PredefinedType: ROOF
Classification: 1.19 IfcSlabType.ROOF (katus) (RKAS BIM + ARCHICAD Classification)
Pset_SlabCommon - Reference: VL-04; LoadBearing: yes; IsExternal: yes
AR_Katus - 001_Nimetus: Katuslagi; 205_Tüüp: VL-04; 325_Helipidavus: nõudeid ei esitata; 330_Tulekindlus: R60; 340_Soojusläbivus: 0; 520_Pindala: 83.5485 m2
AR_Vahelagi - 001_Nimetus: Katuslagi; 205_Tüüp: VL-04; 325_Helipidavus: nõudeid ei esitata; 330_Tulekindlus: R60; 340_Soojusläbivus: 0
AC_Pset_RenovationAndPhasing - Renovation Status: New

# IfcSlab: VL-05_Vahelagi 400 paneel 520 (7)
In: Teine korrus
Classification: 1.20 IfcSlabType (vahelagi) (RKAS BIM + ARCHICAD Classification)
AR_Katus - 520_Pindala: 0 m2; 001_Nimetus: Vahelagi; 205_Tüüp: VL-05; 325_Helipidavus: R'w=52 dB; 330_Tulekindlus: EI60; 340_Soojusläbivus: 0
Pset_SlabCommon - Reference: VL-05; LoadBearing: yes; IsExternal: no
AR_Vahelagi - 001_Nimetus: Vahelagi; 205_Tüüp: VL-05; 325_Helipidavus: R'w=52 dB; 330_Tulekindlus: EI60; 335_Välispiire: no; 340_Soojusläbivus: 0; 500_Kandev: TRUE; 505_Paksus: 520 mm
AC_Pset_RenovationAndPhasing - Renovation Status: New
Name | 510_Bruto_pindala (m2) | 515_Neto_pindala (m2)
VL-05 | 14.0343 | 14.0007
VL-05 | 122.822 | 122.346
VL-05 | 28.7993 | 28.7993
VL-05 | 57.5991 | 57.5991
VL-05 | 28.7994 | 28.5369
VL-05 | 86.3991 | 86.3991
VL-05 | 23.6839 | 23.4214

# IfcSlab: VL-06_Vahelagi 265 õhuhaare 632, VL-06
In: Teine korrus
Type - PredefinedType: ROOF
Classification: 1.19 IfcSlabType.ROOF (katus) (RKAS BIM + ARCHICAD Classification)
Pset_SlabCommon - Reference: VL-06; LoadBearing: yes; IsExternal: yes
AR_Katus - 001_Nimetus: Katuslagi; 205_Tüüp: VL-06; 325_Helipidavus: nõudeid ei esitata; 330_Tulekindlus: R60; 340_Soojusläbivus: 0; 520_Pindala: 7.17984 m2
AR_Vahelagi - 001_Nimetus: Katuslagi; 205_Tüüp: VL-06; 325_Helipidavus: nõudeid ei esitata; 330_Tulekindlus: R60; 340_Soojusläbivus: 0
AC_Pset_RenovationAndPhasing - Renovation Status: New

# IfcSlab: VL-07_Vahelagi büroo õhuhaare 540, VL-07
In: Teine korrus
Classification: 1.20 IfcSlabType (vahelagi) (RKAS BIM + ARCHICAD Classification)
AR_Katus - 520_Pindala: 0 m2; 001_Nimetus: Vahelagi; 205_Tüüp: VL-07; 325_Helipidavus: R'w=52 dB; 330_Tulekindlus: EI60; 340_Soojusläbivus: 0
Pset_SlabCommon - Reference: VL-07; LoadBearing: yes; IsExternal: no
AR_Vahelagi - 001_Nimetus: Vahelagi; 205_Tüüp: VL-07; 325_Helipidavus: R'w=52 dB; 330_Tulekindlus: EI60; 335_Välispiire: no; 340_Soojusläbivus: 0; 500_Kandev: TRUE; 505_Paksus: 540 mm; 510_Bruto_pindala: 1.4142 m2; 515_Neto_pindala: 1.4142 m2
AC_Pset_RenovationAndPhasing - Renovation Status: New

# IfcSlab: VL-20_Vahelagi harjutustorn 180, VAHELAGI
In: Teine korrus
Classification: 1.20 IfcSlabType (vahelagi) (RKAS BIM + ARCHICAD Classification)
AR_Katus - 520_Pindala: 0 m2; 340_Soojusläbivus: 0; 001_Nimetus: Vahelagi; 205_Tüüp: VL-20; 325_Helipidavus: nõudeid ei esitata; 330_Tulekindlus: nõudeid ei esitata
Pset_SlabCommon - Reference: VL-20; LoadBearing: yes; IsExternal: no
AR_Vahelagi - 001_Nimetus: Vahelagi; 205_Tüüp: VL-20; 325_Helipidavus: nõudeid ei esitata; 330_Tulekindlus: nõudeid ei esitata; 335_Välispiire: no; 500_Kandev: TRUE; 505_Paksus: 180 mm; 510_Bruto_pindala: 19.8842 m2; 515_Neto_pindala: 18.5055 m2
AC_Pset_RenovationAndPhasing - Renovation Status: New

# IfcSlab: VL-21_Vahelagi 200 (3)
Classification: 1.20 IfcSlabType (vahelagi) (RKAS BIM + ARCHICAD Classification)
AR_Katus - 520_Pindala: 0 m2; 340_Soojusläbivus: 0; 001_Nimetus: Rõdu; 205_Tüüp: VL-21; 325_Helipidavus: nõudeid ei esitata; 330_Tulekindlus: nõudeid ei esitata
AR_Vahelagi - 340_Soojusläbivus: 0; 001_Nimetus: Rõdu; 205_Tüüp: VL-21; 325_Helipidavus: nõudeid ei esitata; 330_Tulekindlus: nõudeid ei esitata; 335_Välispiire: yes; 500_Kandev: TRUE; 505_Paksus: 200 mm
Pset_SlabCommon - Reference: VL-21; LoadBearing: yes; IsExternal: yes
AC_Pset_RenovationAndPhasing - Renovation Status: New
Name | In | 510_Bruto_pindala (m2) = 515_Neto_pindala (m2)
VL-20 | Teine korrus | 6.29207
VL-20 | Katusekorrus | 0.4
VL-21 | Katusekorrus | 2.20879

# IfcSlab: VL-21_Vahelagi harjutustorn 170, VAHELAGI
In: Katusekorrus
Classification: 1.20 IfcSlabType (vahelagi) (RKAS BIM + ARCHICAD Classification)
AR_Katus - 520_Pindala: 0 m2; 340_Soojusläbivus: 0; 001_Nimetus: Vahelagi; 205_Tüüp: VL-21; 325_Helipidavus: nõudeid ei esitata; 330_Tulekindlus: nõudeid ei esitata
Pset_SlabCommon - Reference: VL-21; LoadBearing: yes; IsExternal: no
AR_Vahelagi - 001_Nimetus: Vahelagi; 205_Tüüp: VL-21; 325_Helipidavus: nõudeid ei esitata; 330_Tulekindlus: nõudeid ei esitata; 335_Välispiire: no; 500_Kandev: TRUE; 505_Paksus: 170 mm; 510_Bruto_pindala: 17.6348 m2; 515_Neto_pindala: 16.4247 m2
AC_Pset_RenovationAndPhasing - Renovation Status: New

# IfcSlab: VL-22_Vahelagi harjutustorn trepimade 230 (2)
Classification: 1.20 IfcSlabType (vahelagi) (RKAS BIM + ARCHICAD Classification)
AR_Katus - 520_Pindala: 0 m2; 001_Nimetus: Vahelagi; 205_Tüüp: VL-22; 325_Helipidavus: nõudeid ei esitata; 330_Tulekindlus: nõudeid ei esitata
Pset_SlabCommon - Reference: VL-22; LoadBearing: yes; IsExternal: no
AR_Vahelagi - 001_Nimetus: Vahelagi; 205_Tüüp: VL-22; 325_Helipidavus: nõudeid ei esitata; 330_Tulekindlus: nõudeid ei esitata; 335_Välispiire: no; 500_Kandev: TRUE; 505_Paksus: 230 mm; 510_Bruto_pindala: 2.53985 m2
AC_Pset_RenovationAndPhasing - Renovation Status: New
Name | In | 515_Neto_pindala (m2)
VAHELAGI | Esimene korrus | 2.51735
VAHELAGI | Teine korrus | 2.51734

# IfcStair (13)
Classification: 1.22 IfcStair (trepp) (RKAS BIM + ARCHICAD Classification)
Pset_StairCommon - IsExternal: no
AC_Pset_RenovationAndPhasing - Renovation Status: New
Name | In | NumberOfRiser | NumberOfTreads | RiserHeight (mm) | RequiredHeadroom (mm)
TREPP 1 | Vundament | 9 | 8 | 200 | 2200
4 x TREPP 1 | Esimene korrus | 11 | 11 | 172.727 | 2200
2 x TREPP 2 | Esimene korrus | 9 | 8 | 183.333 | 2200
2 x VL-14 | Teine korrus | Material: ET-02_Raudbetoon - Toode; Pset_StairCommon - Reference: ET-02; AR_001-002 - 002_Tüüp: ET-02
TREPP 5 | Teine korrus | 4 | 3 | 180 | 2200
VL-07 | Teine korrus | Material: KON-04_Betoon - Konstuktsioon
2 x TREPP 2 | Teine korrus | 9 | 8 | 183.333 | 2200

# IfcWall: SS-01_kergsein 150mm 150, SS-01
In: Teine korrus
Classification: 1.24 IfcWallType (sein) (RKAS BIM + ARCHICAD Classification)
AR_Sein - 340_Soojusläbivus: 0; 001_Nimetus: Sisesein; 205_Tüüp: SS-01; 325_Helipidavus: R'w= 55 dB; 330_Tulekindlus: EI60; 335_Välispiire: no; 376_Viimistlus_väljast: välis pind: Stucco - White Fine; sisepind: Stucco - White Fine; 505_Paksus: 150 mm; 605_Neto_pindala: 23.0229 m2; 600_Bruto_pindala: 25.394 m2; 500_Kandev: FALSE; 376_Viimistlus_väljast (MUDELIS): SKR-02_Kipsplaat; SKR-02_Kipsplaat; SOJ-03_Soojustus - Mineraal Pehme; SKR-02_Kipsplaat; SKR-02_Kipsplaat
Pset_WallCommon - Reference: SS-01; LoadBearing: no; IsExternal: no
AC_Pset_RenovationAndPhasing - Renovation Status: New

# IfcWall: SS-05_Sisesein - relvaruum 205 (5)
In: Teine korrus
Classification: 1.24 IfcWallType (sein) (RKAS BIM + ARCHICAD Classification)
AR_Sein - 340_Soojusläbivus: 0; 001_Nimetus: Sisesein; 205_Tüüp: SS-05; 325_Helipidavus: R'w= 53 dB; 330_Tulekindlus: EI60; 335_Välispiire: no; 376_Viimistlus_väljast: välis pind: Concrete - 10; sisepind: Metal - Nickel; 505_Paksus: 205 mm; 500_Kandev: TRUE; 376_Viimistlus_väljast (MUDELIS): KON-05_Betoon Plokk - Konstuktsioon; ET-05_Teras
Pset_WallCommon - Reference: SS-05; LoadBearing: yes; IsExternal: no
AC_Pset_RenovationAndPhasing - Renovation Status: New
Name | 605_Neto_pindala (m2) | 600_Bruto_pindala (m2)
SS-05 | 10.725 | 11.4043
SS-05 | 11.1173 | 11.7888
SS-05 | 11.1173 | 11.1173
SS-05 | 8.54353 | 9.03511
SS-05 | 4.93825 | 7.5075

# IfcWall: SS-07_Sisesein - leiliruum 205 (5)
In: Teine korrus
Classification: 1.24 IfcWallType (sein) (RKAS BIM + ARCHICAD Classification)
AR_Sein - 340_Soojusläbivus: 0; 001_Nimetus: Sisesein; 205_Tüüp: SS-07; 335_Välispiire: no; 376_Viimistlus_väljast: välis pind: Concrete - 10; sisepind: Wood - Pine Grained Horizontal; 505_Paksus: 205 mm; 500_Kandev: FALSE; 376_Viimistlus_väljast (MUDELIS): KON-05_Betoon Plokk - Konstuktsioon; SOJ-02_Soojustus - Fiiber Kõva; Õhkvahe - Raam; ET-01_Puit - Konstruktsioon
Pset_WallCommon - Reference: SS-07; LoadBearing: no; IsExternal: no
AC_Pset_RenovationAndPhasing - Renovation Status: New
Name | 325_Helipidavus | 330_Tulekindlus | 605_Neto_pindala (m2) | 600_Bruto_pindala (m2)
SS-07 | R'w= 52 dB | EI60 | 9.30287 | 9.30287
SS-07 | R'w= 52 dB | nõudeid ei esitata | 8.95915 | 8.95915
SS-07 | R'w= 49 dB | nõudeid ei esitata | 8.1988 | 9.3029
SS-07 | R'w= 52 dB | nõudeid ei esitata | 7.399 | 9.8826
SS-07 | R'w=52 dB | nõudeid ei esitata | 7.32643 | 9.30323

# IfcWall: SS-08_Sisesein - leiliruum trepi kõrval 302, SS-08
In: Teine korrus
Classification: 1.24 IfcWallType (sein) (RKAS BIM + ARCHICAD Classification)
AR_Sein - 340_Soojusläbivus: 0; 001_Nimetus: Sisesein; 205_Tüüp: SS-08; 325_Helipidavus: R'w= 53 dB; 330_Tulekindlus: EI60; 335_Välispiire: no; 376_Viimistlus_väljast: välis pind: Concrete - 10; sisepind: Wood - Pine Grained Horizontal; 505_Paksus: 302 mm; 605_Neto_pindala: 8.56098 m2; 600_Bruto_pindala: 10.7692 m2; 500_Kandev: TRUE; 376_Viimistlus_väljast (MUDELIS): KON-05_Betoon Plokk - Konstuktsioon; Insulation - Mineral Soft+tala 50x150mm; SOJ-04_Soojustus - Mineraal Kõva; Õhkvahe - Raam; ET-01_Puit - Konstruktsioon
Pset_WallCommon - Reference: SS-08; LoadBearing: yes; IsExternal: no
AC_Pset_RenovationAndPhasing - Renovation Status: New

# IfcWall: SS-11 vent õhuvõtt 220, SS-11
In: Esimene korrus
Classification: 1.24 IfcWallType (sein) (RKAS BIM + ARCHICAD Classification)
Pset_WallCommon - Reference: SS-11 vent õhuvõtt; LoadBearing: no; IsExternal: no
AR_Sein - 001_Nimetus: Sisesein; 205_Tüüp: SS-11 vent õhuvõtt; 325_Helipidavus: R'w= 52 dB; 330_Tulekindlus: EI60; 335_Välispiire: no; 340_Soojusläbivus: 0.27; 376_Viimistlus_väljast: välis pind: Concrete - 10; sisepind: Insulation - Fiberglass; 505_Paksus: 220 mm; 605_Neto_pindala: 2.7166 m2; 600_Bruto_pindala: 4.4812 m2; 500_Kandev: FALSE; 376_Viimistlus_väljast (MUDELIS): KON-05_Betoon Plokk - Konstuktsioon; SOJ-02_Soojustus - Fiiber Kõva
AC_Pset_RenovationAndPhasing - Renovation Status: New

# IfcWall: SS-12 vent õhuvõtt garaaz 270 (2)
In: Teine korrus
Classification: 1.24 IfcWallType (sein) (RKAS BIM + ARCHICAD Classification)
AR_Sein - 340_Soojusläbivus: 0; 001_Nimetus: Sisesein; 205_Tüüp: SS-12 vent õhuvõtt garaaz; 330_Tulekindlus: EI60; 335_Välispiire: no; 376_Viimistlus_väljast: välis pind: Concrete - 10; sisepind: Insulation - Fiberglass; 505_Paksus: 270 mm; 605_Neto_pindala: 3.54678 m2; 600_Bruto_pindala: 5.64674 m2; 500_Kandev: TRUE; 376_Viimistlus_väljast (MUDELIS): KON-05_Betoon Plokk - Konstuktsioon; SOJ-02_Soojustus - Fiiber Kõva
Pset_WallCommon - Reference: SS-12 vent õhuvõtt garaaz; LoadBearing: yes; IsExternal: no
AC_Pset_RenovationAndPhasing - Renovation Status: New
Name | 325_Helipidavus
SS-12 | R'w= 58 dB
SS-12 | R'w= 52 dB

# IfcWall: SS-13_kergsein 75 ümber el-kilbi 75 (11)
In: Teine korrus
Classification: 1.24 IfcWallType (sein) (RKAS BIM + ARCHICAD Classification)
AR_Sein - 340_Soojusläbivus: 0; 001_Nimetus: Sisesein; 205_Tüüp: SS-13; 325_Helipidavus: R'w= 52 dB; 330_Tulekindlus: nõudeid ei esitata; 335_Välispiire: no; 376_Viimistlus_väljast: välis pind: Stucco - White Fine; sisepind: Paint - Titanium White; 505_Paksus: 75 mm; 500_Kandev: FALSE; 376_Viimistlus_väljast (MUDELIS): SKR-02_Kipsplaat; SKR-02_Kipsplaat; Õhkvahe - Raam
Pset_WallCommon - Reference: SS-13; LoadBearing: no; IsExternal: no
AC_Pset_RenovationAndPhasing - Renovation Status: Existing
Name | 605_Neto_pindala (m2) | 600_Bruto_pindala (m2)
SS-13 | 1.33813 | 3.25224
SS-13 | 1.25491 | 3.1675
SS-13 | 1.0656 | 1.7738
SS-13 | 2.66898 | 3.2218
SS-21 | 3.93525 | 4.98102
SS-13 | 1.10253 | 1.86479
SS-13 | 1.10565 | 1.6408
SS-13 | 1.02843 | 1.6046
2 x SS-13 | 1.20563 | 1.73447
SS-13 | 1.25492 | 1.3213

# IfcWall: SS-14_Sisesein - 190+võrre+puit 257 (2)
In: Teine korrus
Classification: 1.24 IfcWallType (sein) (RKAS BIM + ARCHICAD Classification)
AR_Sein - 340_Soojusläbivus: 0; 001_Nimetus: Sisesein; 205_Tüüp: SS-14; 325_Helipidavus: R'w= 53 dB; 330_Tulekindlus: EI60; 335_Välispiire: no; 376_Viimistlus_väljast: välis pind: Concrete - 10; sisepind: Wood - Pine Grained Horizontal; 505_Paksus: 257 mm; 500_Kandev: TRUE; 376_Viimistlus_väljast (MUDELIS): KON-05_Betoon Plokk - Konstuktsioon; ET-03_Raud; Õhkvahe; Puit - Konstruktsioon
Pset_WallCommon - Reference: SS-14; LoadBearing: yes; IsExternal: no
AC_Pset_RenovationAndPhasing - Renovation Status: New
Name | 605_Neto_pindala (m2) | 600_Bruto_pindala (m2)
SS-05 | 6.58873 | 7.201
SS-05 | 2.62047 | 2.983

# IfcWall: SS-15_Sisesein 190 + puit 32 ühel pool 242, SS-03
In: Teine korrus
Classification: 1.24 IfcWallType (sein) (RKAS BIM + ARCHICAD Classification)
AR_Sein - 340_Soojusläbivus: 0; 001_Nimetus: Sisesein; 205_Tüüp: SS-15; 325_Helipidavus: R'w= 56 dB; 330_Tulekindlus: nõudeid ei esitata; 335_Välispiire: no; 376_Viimistlus_väljast: välis pind: Concrete - 10; sisepind: Wood - Pine Grained Horizontal; 505_Paksus: 242 mm; 605_Neto_pindala: 2.80638 m2; 600_Bruto_pindala: 3.54078 m2; 500_Kandev: TRUE; 376_Viimistlus_väljast (MUDELIS): KON-05_Betoon Plokk - Konstuktsioon; Õhkvahe; ET-01_Puit - Konstruktsioon
Pset_WallCommon - Reference: SS-15; LoadBearing: yes; IsExternal: no
AC_Pset_RenovationAndPhasing - Renovation Status: New

# IfcWall: SS-16_Sisesein 190 + puit 32 kahel pool 294, SS-03
In: Teine korrus
Classification: 1.24 IfcWallType (sein) (RKAS BIM + ARCHICAD Classification)
AR_Sein - 340_Soojusläbivus: 0; 001_Nimetus: Sisesein; 205_Tüüp: SS-16; 325_Helipidavus: R'w= 56 dB; 330_Tulekindlus: nõudeid ei esitata; 335_Välispiire: no; 376_Viimistlus_väljast: välis pind: Wood - Pine Grained Horizontal; sisepind: Wood - Pine Grained Horizontal; 505_Paksus: 294 mm; 605_Neto_pindala: 2.61754 m2; 600_Bruto_pindala: 2.80759 m2; 500_Kandev: TRUE; 376_Viimistlus_väljast (MUDELIS): ET-01_Puit - Konstruktsioon; Õhkvahe; KON-05_Betoon Plokk - Konstuktsioon; Õhkvahe; ET-01_Puit - Konstruktsioon
Pset_WallCommon - Reference: SS-16; LoadBearing: yes; IsExternal: no
AC_Pset_RenovationAndPhasing - Renovation Status: New

# IfcWall: SS-31_kergsein 150mm pääste garaaz 180, SS-31
In: Esimene korrus
Classification: 1.24 IfcWallType (sein) (RKAS BIM + ARCHICAD Classification)
Pset_WallCommon - Reference: SS-31; LoadBearing: no; IsExternal: no
AR_Sein - 001_Nimetus: Sisesein; 205_Tüüp: SS-31; 325_Helipidavus: nõudeid ei esitata; 330_Tulekindlus: nõudeid ei esitata; 335_Välispiire: no; 340_Soojusläbivus: 0; 376_Viimistlus_väljast: välis pind: Wood - Mahogany Vertical; sisepind: Wood - Mahogany Vertical; 505_Paksus: 180 mm; 605_Neto_pindala: 56.3585 m2; 600_Bruto_pindala: 56.4899 m2; 500_Kandev: FALSE; 376_Viimistlus_väljast (MUDELIS): Vineer; Õhkvahe; Vineer
AC_Pset_RenovationAndPhasing - Renovation Status: Existing

# IfcWall: VS-01_välissein 510 (34)
Classification: 1.24 IfcWallType (sein) (RKAS BIM + ARCHICAD Classification)
Pset_WallCommon - Reference: VS-01; IsExternal: yes
AR_Sein - 205_Tüüp: VS-01; 325_Helipidavus: R'w=58dB; 335_Välispiire: yes; 340_Soojusläbivus: 0.09; 376_Viimistlus_väljast: välis pind: Paint - Anthracite; sisepind: Concrete - 04; 505_Paksus: 510 mm; 376_Viimistlus_väljast (MUDELIS): KON-04_Betoon - Konstuktsioon; SOJ-06_Soojustus - Plastik Kõva; KON-04_Betoon - Konstuktsioon
AC_Pset_RenovationAndPhasing - Renovation Status: New
Name | In | LoadBearing | 001_Nimetus | 330_Tulekindlus | 605_Neto_pindala (m2) | 600_Bruto_pindala (m2) | 500_Kandev
VS-01 | Esimene korrus | yes | välissein | nõudeid ei esitata | 74.5361 | 74.8881 | TRUE
VS-01 | Esimene korrus | yes | välissein | nõudeid ei esitata | 40.8303 | 51.1103 | TRUE
VS-01 | Esimene korrus | yes | välissein | EI60 | 13.3 | 15.238 | TRUE
VS-01 | Esimene korrus | yes | välissein | nõudeid ei esitata | 17.4791 | 21.7385 | TRUE
VS-01 | Esimene korrus | yes | välissein | nõudeid ei esitata | 16.5296 | 16.5296 | TRUE
VS-01 | Esimene korrus | yes | välissein | nõudeid ei esitata | 46.018 | 46.018 | TRUE
VS-01 | Esimene korrus | no |  | nõudeid ei esitata | 15.8102 | 16.3204 | FALSE
VS-01 | Esimene korrus | no |  | nõudeid ei esitata | 1.59074 | 1.59074 | FALSE
VS-01 | Esimene korrus | yes | välissein | nõudeid ei esitata | 31.996 | 31.996 | TRUE
VS-01 | Esimene korrus | yes | välissein | nõudeid ei esitata | 132.49 | 164.39 | TRUE
VS-01 | Esimene korrus | yes | välissein | nõudeid ei esitata | 32.8681 | 39.9761 | TRUE
VS-01 | Esimene korrus | no |  | nõudeid ei esitata | 4.9 | 4.9 | FALSE
VS-01 | Esimene korrus | yes | välissein | nõudeid ei esitata | 26.9081 | 36.7081 | TRUE
VS-01 | Esimene korrus | yes | välissein | nõudeid ei esitata | 4.94001 | 4.94001 | TRUE
VS-01 | Esimene korrus | yes | välissein | nõudeid ei esitata | 49.9413 | 59.8781 | TRUE
VS-01 | Teine korrus | yes | välissein | nõudeid ei esitata | 59.551 | 59.551 | TRUE
VS-01 | Teine korrus | yes | välissein | nõudeid ei esitata | 54.2081 | 54.4641 | TRUE
VS-01 | Teine korrus | yes | välissein | nõudeid ei esitata | 79.6618 | 102.062 | TRUE
VS-01 | Teine korrus | yes | välissein | nõudeid ei esitata | 47.9223 | 49.0209 | TRUE
VS-01 | Teine korrus | yes | välissein | nõudeid ei esitata | 14.3097 | 20.9377 | TRUE
VS-01 | Teine korrus | yes | välissein | nõudeid ei esitata | 108.576 | 146.376 | TRUE
VS-01 | Teine korrus | yes | välissein | nõudeid ei esitata | 49.1641 | 64.638 | TRUE
VS-01 | Teine korrus | yes | välissein | nõudeid ei esitata | 37.9681 | 39.9761 | TRUE
VS-01 | Teine korrus | yes | välissein | nõudeid ei esitata | 39.018 | 45.4939 | TRUE
VS-01 | Teine korrus | yes | välissein | nõudeid ei esitata | 0 | 0.722 | TRUE
VS-01 | Teine korrus | yes | välissein | nõudeid ei esitata | 42.6741 | 42.9781 | TRUE
VS-01 | Teine korrus | yes | välissein | nõudeid ei esitata | 99.5227 | 99.5227 | TRUE
VS-01 | Teine korrus | yes | välissein | nõudeid ei esitata | 1.86356 | 1.86356 | TRUE
VS-01 | Teine korrus | yes | välissein | nõudeid ei esitata | 4.52202 | 4.52202 | TRUE
VS-01 | Teine korrus | yes | välissein | EI60 | 15.2 | 17.138 | TRUE
2 x VS-01 | Katusekorrus | yes |  | nõudeid ei esitata | 14.3916 | 14.5524 | TRUE
2 x VS-01 | Katusekorrus | yes |  | nõudeid ei esitata | 13.8172 | 14.5507 | TRUE

# IfcWall: VS-02_välissein - soklipaneel 460 (12)
In: Vundament
Classification: 1.24 IfcWallType (sein) (RKAS BIM + ARCHICAD Classification)
Pset_WallCommon - Reference: VS-02; LoadBearing: yes; IsExternal: yes
AR_Sein - 001_Nimetus: välissein; 205_Tüüp: VS-02; 330_Tulekindlus: nõudeid ei esitata; 335_Välispiire: yes; 340_Soojusläbivus: 0.1; 376_Viimistlus_väljast: välis pind: Concrete - 04; sisepind: Concrete - 04; 505_Paksus: 460 mm; 500_Kandev: TRUE; 376_Viimistlus_väljast (MUDELIS): KON-04_Betoon - Konstuktsioon; SOJ-06_Soojustus - Plastik Kõva; KON-04_Betoon - Konstuktsioon
AC_Pset_RenovationAndPhasing - Renovation Status: New
Name | 325_Helipidavus | 605_Neto_pindala (m2) | 600_Bruto_pindala (m2)
VS-02 | nõuded ei esitata | 110.209 | 110.209
VS-02 | nõuded ei esitata | 26.944 | 27.072
VS-02 | nõuded ei esitata | 26.2765 | 27.0125
VS-02 | nõuded ei esitata | 16.672 | 16.672
VS-02 | R'w=58dB | 93.1849 | 93.7929
VS-02 | nõuded ei esitata | 5.60001 | 6.33601
VS-02 | nõuded ei esitata | 7.87188 | 8.73588
VS-02 | nõuded ei esitata | 35.0674 | 35.1954
VS-02 | nõuded ei esitata | 2.592 | 3.456
VS-02 | nõuded ei esitata | 19.008 | 19.136
VS-02 | nõuded ei esitata | 2.4 | 3.136
VS-02 | nõuded ei esitata | 7.264 | 8.736

# IfcWall: VS-03_välissein paneel300 + fassaadikassett 620 (2)
In: Esimene korrus
Classification: 1.24 IfcWallType (sein) (RKAS BIM + ARCHICAD Classification)
Pset_WallCommon - Reference: VS-03; LoadBearing: yes; IsExternal: yes
AR_Sein - 001_Nimetus: välissein; 205_Tüüp: VS-03; 325_Helipidavus: R'w= 58dB; 335_Välispiire: yes; 340_Soojusläbivus: 0.1; 376_Viimistlus_väljast: välis pind: Paint - Anthracite; sisepind: Stucco - White Rough; 505_Paksus: 620 mm; 500_Kandev: TRUE; 376_Viimistlus_väljast (MUDELIS): GENEERILINE - VÄLINE VOODER; Õhkvahe - Raam; SOJ-06_Soojustus - Plastik Kõva; KON-04_Betoon - Konstuktsioon
AC_Pset_RenovationAndPhasing - Renovation Status: New
Name | 330_Tulekindlus | 605_Neto_pindala (m2) | 600_Bruto_pindala (m2)
VS-03 | nõudeid ei esitata | 30.2161 | 58.5875
VS-03 | EI60 | 3.73681 | 7.64661

# IfcWall: VS-04_välissein paneel200 + fassaadikassett 520 (3)
In: Esimene korrus
Classification: 1.24 IfcWallType (sein) (RKAS BIM + ARCHICAD Classification)
AR_Sein - 340_Soojusläbivus: 0; 001_Nimetus: välissein; 205_Tüüp: VS-04; 325_Helipidavus: R'w= 58dB; 335_Välispiire: yes; 505_Paksus: 520 mm; 500_Kandev: TRUE; 376_Viimistlus_väljast (MUDELIS): GENEERILINE - VÄLINE VOODER; Õhkvahe - Raam; SOJ-06_Soojustus - Plastik Kõva; KON-04_Betoon - Konstuktsioon
Pset_WallCommon - Reference: VS-04; LoadBearing: yes; IsExternal: yes
AC_Pset_RenovationAndPhasing - Renovation Status: New
Name | 330_Tulekindlus | 376_Viimistlus_väljast | 605_Neto_pindala (m2) | 600_Bruto_pindala (m2)
VS-04 | nõudeid ei esitata | välis pind: Paint - Anthracite; sisepind: Concrete - 04 | 6.6859 | 18.7705
VS-04 | EI60 | välis pind: Paint - Anthracite; sisepind: Stucco - White Rough | 3.3271 | 6.9546
VS-04 | EI60 | välis pind: Paint - Anthracite; sisepind: Concrete - 04 | 4.7509 | 6.7816

# IfcWall: VS-06_välissein varikatuse külg 290 (2)
In: Esimene korrus
Classification: 1.24 IfcWallType (sein) (RKAS BIM + ARCHICAD Classification)
AR_Sein - 340_Soojusläbivus: 0; 001_Nimetus: vä'lissein; 205_Tüüp: VS-06; 325_Helipidavus: nõuded ei esitata; 330_Tulekindlus: nõudeid ei esitata; 335_Välispiire: yes; 376_Viimistlus_väljast: välis pind: Stucco - White Rough; sisepind: Stucco - White Rough; 505_Paksus: 290 mm; 500_Kandev: TRUE; 376_Viimistlus_väljast (MUDELIS): ET-06_Teras - Konstruktsioon; Õhkvahe; Õhkvahe - Raam; Õhkvahe; ET-06_Teras - Konstruktsioon
Pset_WallCommon - Reference: VS-06; LoadBearing: yes; IsExternal: yes
AC_Pset_RenovationAndPhasing - Renovation Status: New
Name | 605_Neto_pindala (m2) = 600_Bruto_pindala (m2)
VS-06 | 8.41415
VS-06 | 8.399

# IfcWall: VS-10_välissein leiliruum 605 (2)
In: Teine korrus
Classification: 1.24 IfcWallType (sein) (RKAS BIM + ARCHICAD Classification)
Pset_WallCommon - Reference: VS-10; LoadBearing: yes; IsExternal: yes
AR_Sein - 001_Nimetus: välissein; 205_Tüüp: VS-10; 325_Helipidavus: R'w=58dB; 335_Välispiire: yes; 340_Soojusläbivus: 0.09; 376_Viimistlus_väljast: välis pind: Paint - Anthracite; sisepind: Wood - Pine Grained Horizontal; 505_Paksus: 605 mm; 500_Kandev: TRUE; 376_Viimistlus_väljast (MUDELIS): KON-04_Betoon - Konstuktsioon; SOJ-06_Soojustus - Plastik Kõva; KON-04_Betoon - Konstuktsioon; SOJ-02_Soojustus - Fiiber Kõva; Õhkvahe; ET-01_Puit - Konstruktsioon
AC_Pset_RenovationAndPhasing - Renovation Status: New
Name | 330_Tulekindlus | 605_Neto_pindala (m2) | 600_Bruto_pindala (m2)
VS-10 | nõudeid ei esitata | 8.326 | 8.816
VS-10 | EI60 | 9.61204 | 10.1416

# IfcWall: VS-13_välissein õhuvõtt 590 (2)
Classification: 1.24 IfcWallType (sein) (RKAS BIM + ARCHICAD Classification)
Pset_WallCommon - Reference: VS-13; LoadBearing: yes; IsExternal: yes
AR_Sein - 205_Tüüp: VS-13; 325_Helipidavus: R'w=58dB; 330_Tulekindlus: nõudeid ei esitata; 335_Välispiire: yes; 340_Soojusläbivus: 0.09; 376_Viimistlus_väljast: välis pind: Paint - Anthracite; sisepind: Insulation - Fiberglass; 505_Paksus: 590 mm; 500_Kandev: TRUE; 376_Viimistlus_väljast (MUDELIS): KON-04_Betoon - Konstuktsioon; SOJ-06_Soojustus - Plastik Kõva; KON-04_Betoon - Konstuktsioon; SOJ-02_Soojustus - Fiiber Kõva
AC_Pset_RenovationAndPhasing - Renovation Status: New
Name | In | 605_Neto_pindala (m2) | 600_Bruto_pindala (m2)
VS-13 | Esimene korrus | 6.57951 | 7.97951
VS-13 | Teine korrus | 26.3225 | 30.3225

# IfcWall: VS-14_välissein gar uste vahel 510 (2)
In: Esimene korrus
Classification: 1.24 IfcWallType (sein) (RKAS BIM + ARCHICAD Classification)
Pset_WallCommon - Reference: VS-14; LoadBearing: yes; IsExternal: yes
AR_Sein - 205_Tüüp: VS-14; 325_Helipidavus: R'w=58dB; 330_Tulekindlus: nõudeid ei esitata; 335_Välispiire: yes; 340_Soojusläbivus: 0.09; 376_Viimistlus_väljast: välis pind: Paint - Anthracite; sisepind: Concrete - 04; 505_Paksus: 510 mm; 500_Kandev: TRUE; 376_Viimistlus_väljast (MUDELIS): KON-04_Betoon - Konstuktsioon; SOJ-06_Soojustus - Plastik Kõva; KON-04_Betoon - Konstuktsioon
AC_Pset_RenovationAndPhasing - Renovation Status: New
Name | 605_Neto_pindala (m2) | 600_Bruto_pindala (m2)
VS-14 | 11.4826 | 81.8826
VS-14 | 18.0437 | 136.844

# IfcWall: VS-20_Välissein jarjutustorn 225 (7)
Classification: 1.24 IfcWallType (sein) (RKAS BIM + ARCHICAD Classification)
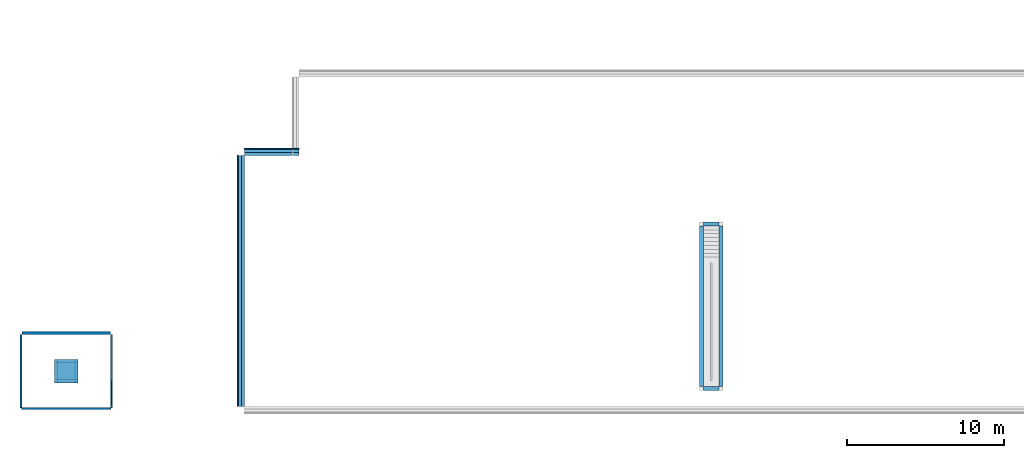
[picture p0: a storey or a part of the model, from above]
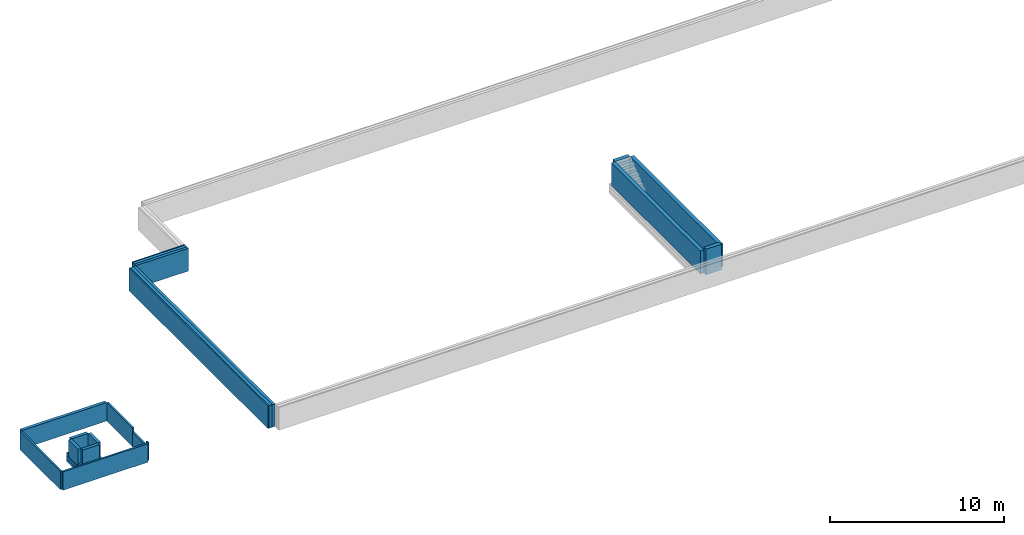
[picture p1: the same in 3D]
Properties of the parts of a building model (IFC2X3), part 4 of 4

# IfcWall: VS-20_Välissein jarjutustorn 225 (7)
AR_Sein - 205_Tüüp: VS-20; 325_Helipidavus: nõuded ei esitata; 330_Tulekindlus: nõudeid ei esitata; 335_Välispiire: yes; 376_Viimistlus_väljast: välis pind: Paint - Anthracite; sisepind: Paint - Titanium White; 505_Paksus: 225 mm; 500_Kandev: TRUE; 376_Viimistlus_väljast (MUDELIS): SKR-04_Puitplaat; SKR-01_Õhkvahe - Raam; SKR-01_Õhkvahe - Raam; SKR-05_Vineer; Õhkvahe - Raam
Pset_WallCommon - Reference: VS-20; LoadBearing: yes; IsExternal: yes
AC_Pset_RenovationAndPhasing - Renovation Status: New
Name | In | 605_Neto_pindala (m2) | 600_Bruto_pindala (m2)
VS-20 | Esimene korrus | 15.0762 | 15.0762 | AR_Sein - 340_Soojusläbivus: 0
Välissein | Esimene korrus | 18.1675 | 18.3025 | AR_Sein - 340_Soojusläbivus: 0
VS-20 | Esimene korrus | 11.9187 | 15.0762 | AR_Sein - 340_Soojusläbivus: 0
VS-20 | Teine korrus | 16.8202 | 16.8202
VS-20 | Teine korrus | 20.2661 | 20.4167
VS-20 | Teine korrus | 12.6596 | 16.8202
VS-20 | Katusekorrus | 1.595 | 3.63

# IfcWall: VS-25_Välissein jarjutustorn parapett 390 (7)
Classification: 1.24 IfcWallType (sein) (RKAS BIM + ARCHICAD Classification)
Pset_WallCommon - Reference: VS-25; LoadBearing: yes; IsExternal: yes
AR_Sein - 205_Tüüp: VS-25; 325_Helipidavus: nõuded ei esitata; 330_Tulekindlus: nõudeid ei esitata; 335_Välispiire: yes; 376_Viimistlus_väljast: välis pind: Paint - Anthracite; sisepind: Wood - Pine Grained Horizontal; 505_Paksus: 390 mm; 500_Kandev: TRUE; 376_Viimistlus_väljast (MUDELIS): SKR-04_Puitplaat; SKR-01_Õhkvahe - Raam; SKR-01_Õhkvahe - Raam; SKR-05_Vineer; Õhkvahe - Raam; Õhkvahe - Raam; SKR-04_Puitplaat
AC_Pset_RenovationAndPhasing - Renovation Status: New
Name | In | 605_Neto_pindala (m2) | 600_Bruto_pindala (m2)
Välissein | Katusekorrus | 2.24364 | 2.52781
Välissein | Katusekorrus | 2.90231 | 3.0683
Välissein | Katusekorrus | 2.33164 | 2.52781
2 x VS-20 | Korrus +9.900 | 6.1 | 6.1
2 x VS-20 | Korrus +9.900 | 5.01046 | 5.10046

# IfcWall: VS-31_Välissein Pääste garaaz 275 (4)
In: Esimene korrus
Classification: 1.24 IfcWallType (sein) (RKAS BIM + ARCHICAD Classification)
AR_Sein - 340_Soojusläbivus: 0; 001_Nimetus: välissein; 205_Tüüp: VS-31; 325_Helipidavus: nõuded ei esitata; 330_Tulekindlus: nõudeid ei esitata; 335_Välispiire: yes; 505_Paksus: 275 mm; 500_Kandev: TRUE; 376_Viimistlus_väljast (MUDELIS): GENEERILINE - VÄLINE VOODER; Õhkvahe; Õhkvahe; Vineer; Õhkvahe
Pset_WallCommon - Reference: VS-31; LoadBearing: yes; IsExternal: yes
AC_Pset_RenovationAndPhasing - Renovation Status: New
Name | 376_Viimistlus_väljast | 605_Neto_pindala (m2) | 600_Bruto_pindala (m2)
VS-31 | välis pind: Metal - Steel; sisepind: Paint - Anthracite | 82.02 | 150.27
VS-31 | välis pind: Paint - Anthracite; sisepind: Metal - Steel | 124.665 | 124.665
2 x Välissein | välis pind: Metal - Steel; sisepind: Paint - Anthracite | 81.6023 | 82.1863

# IfcWall: VS-41_Välissein PPA varjualune 225 (5)
In: Esimene korrus
Classification: 1.24 IfcWallType (sein) (RKAS BIM + ARCHICAD Classification)
AR_Sein - 340_Soojusläbivus: 0; 001_Nimetus: välissein; 205_Tüüp: VS-41; 325_Helipidavus: nõuded ei esitata; 330_Tulekindlus: nõudeid ei esitata; 335_Välispiire: yes; 505_Paksus: 225 mm; 500_Kandev: TRUE; 376_Viimistlus_väljast (MUDELIS): GENEERILINE - VÄLINE VOODER; Õhkvahe; Õhkvahe; Vineer; Õhkvahe
Pset_WallCommon - Reference: VS-41; LoadBearing: yes; IsExternal: yes
AC_Pset_RenovationAndPhasing - Renovation Status: New
Name | 376_Viimistlus_väljast | 605_Neto_pindala (m2) | 600_Bruto_pindala (m2)
VS-41 | välis pind: Metal - Steel; sisepind: Paint - Anthracite | 25.6912 | 66.5526
VS-41 | välis pind: Paint - Anthracite; sisepind: Metal - Steel | 55.501 | 55.501
2 x VS-41 | välis pind: Metal - Steel; sisepind: Paint - Anthracite | 16.7021 | 16.9774
VS-41 | välis pind: Metal - Steel; sisepind: Paint - Anthracite | 16.6859 | 16.9774

# IfcWallStandardCase: ET-05_Teras 50 (6)
In: Teine korrus
Classification: 1.24 IfcWallType (sein) (RKAS BIM + ARCHICAD Classification); Material: ET-05_Teras 50 mm
AR_Sein - 340_Soojusläbivus: 0; 001_Nimetus: Sisesein; 205_Tüüp: ET-05; 325_Helipidavus: R'w= 52 dB; 330_Tulekindlus: nõudeid ei esitata; 335_Välispiire: no; 376_Viimistlus_väljast: välis pind: Paint-02; sisepind: Paint-02; 505_Paksus: 50 mm; 500_Kandev: FALSE; 376_Viimistlus_väljast (MUDELIS): ET-05_Teras
Pset_WallCommon - Reference: ET-05; LoadBearing: no; IsExternal: no
AC_Pset_RenovationAndPhasing - Renovation Status: Existing
Name | 605_Neto_pindala (m2) = 600_Bruto_pindala (m2)
SS-17 | 0.00829117
2 x SS-17 | 0.0035719
2 x SS-17 | 0.00324593
SS-17 | 0.00753453

# IfcWallStandardCase: SS-02_Sisesein 140 140 (101)
Classification: 1.24 IfcWallType (sein) (RKAS BIM + ARCHICAD Classification); Material: KON-05_Betoon Plokk - Konstuktsioon 140 mm
Pset_WallCommon - Reference: SS-02; IsExternal: no
AR_Sein - 001_Nimetus: Sisesein; 205_Tüüp: SS-02; 335_Välispiire: no; 340_Soojusläbivus: 0; 376_Viimistlus_väljast: välis pind: Concrete - 10; sisepind: Concrete - 10; 505_Paksus: 140 mm; 376_Viimistlus_väljast (MUDELIS): KON-05_Betoon Plokk - Konstuktsioon
AC_Pset_RenovationAndPhasing - Renovation Status: New
Name | In | LoadBearing | 325_Helipidavus | 330_Tulekindlus | 605_Neto_pindala (m2) | 600_Bruto_pindala (m2) | 500_Kandev
SS-02 | Esimene korrus | no | R'w= 49 dB | EI120 | 16.2518 | 18.9379 | FALSE
SS-02 | Esimene korrus | no | R'w= 49 dB | nõudeid ei esitata | 13.4395 | 19.7434 | FALSE
SS-02 | Esimene korrus | no | R'w= 49 dB | nõudeid ei esitata | 15.3295 | 19.7434 | FALSE
2 x SS-02 | Esimene korrus | no | R'w= 49 dB | nõudeid ei esitata | 8.996 | 10.3108 | FALSE
SS-02 | Esimene korrus | no | R'w= 49 dB | EI60 | 12.11 | 13.8746 | FALSE
SS-02 | Esimene korrus | no | R'w= 49 dB | EI60 | 8.85761 | 12.1965 | FALSE
3 x SS-02 | Esimene korrus | no | R'w= 49 dB | nõudeid ei esitata | 14.7396 | 17.3519 | FALSE
SS-02 | Esimene korrus | no | R'w= 49 dB | EI120 | 15.6565 | 23.5493 | FALSE
SS-02 | Esimene korrus | no | R'w= 49 dB | EI120 | 20.6965 | 23.0089 | FALSE
SS-02 | Esimene korrus | no | R'w= 49 dB | nõudeid ei esitata | 18.846 | 24.9812 | FALSE
SS-02 | Esimene korrus | no | R'w= 49 dB | EI120 | 15.1536 | 16.0884 | FALSE
5 x SS-02 | Esimene korrus | no | R'w= 49 dB | EI120 | 26.2398 | 28.6998 | FALSE
SS-02 | Esimene korrus | no | R'w= 49 dB | nõudeid ei esitata | 13.0012 | 16.1376 | FALSE
SS-02 | Esimene korrus | no | R'w= 49 dB | EI120 | 14.8912 | 15.6784 | FALSE
SS-02 | Esimene korrus | no | R'w= 49 dB | EI120 | 4.92007 | 6.00247 | FALSE
SS-02 | Esimene korrus | no | R'w= 49 dB | nõudeid ei esitata | 4.22857 | 6.85515 | FALSE
SS-02 | Esimene korrus | no | R'w= 49 dB | EI120 | 16.9309 | 18.5809 | FALSE
SS-02 | Esimene korrus | no | R'w= 49 dB | nõudeid ei esitata | 10.8894 | 13.0214 | FALSE
SS-02 | Esimene korrus | no | R'w= 49 dB | EI120 | 5.70717 | 6.34677 | FALSE
SS-02 | Esimene korrus | no | R'w= 49 dB | nõudeid ei esitata | 4.92 | 6.1664 | FALSE
SS-02 | Esimene korrus | no | R'w= 49 dB | EI120 | 11.7424 | 12.218 | FALSE
SS-02 | Esimene korrus | no | R'w= 49 dB | nõudeid ei esitata | 13.2112 | 16.1376 | FALSE
SS-02 | Esimene korrus | no | R'w= 49 dB | EI120 | 4.92 | 6.1664 | FALSE
SS-02 | Esimene korrus | no | R'w= 49 dB | EI60 | 11.5324 | 14.9472 | FALSE
SS-02 | Esimene korrus | no | R'w= 49 dB | nõudeid ei esitata | 5.98584 | 6.98578 | FALSE
SS-02 | Esimene korrus | no | R'w= 49 dB | EI60 | 12.4564 | 12.9408 | FALSE
SS-02 | Esimene korrus | no | R'w= 49 dB | EI60 | 4.8373 | 9.08252 | FALSE
SS-02 | Esimene korrus | no | R'w= 49 dB | EI60 | 1.706 | 5.2938 | FALSE
SS-02 | Esimene korrus | no | R'w= 49 dB | nõudeid ei esitata | 8.53921 | 10.8519 | FALSE
SS-02 | Esimene korrus | no | R'w= 49 dB | EI120 | 10.0632 | 11.6458 | FALSE
SS-02 | Esimene korrus | no | R'w= 49 dB | EI60 | 14.7396 | 17.3346 | FALSE
SS-02 | Esimene korrus | no | R'w= 49 dB | EI60 | 14.7396 | 17.3519 | FALSE
SS-02 | Esimene korrus | no | R'w= 49 dB | nõudeid ei esitata | 11.6256 | 13.8919 | FALSE
SS-02 | Esimene korrus | no | R'w= 49 dB | nõudeid ei esitata | 12.11 | 13.8746 | FALSE
SS-02 | Esimene korrus | no | R'w= 49 dB | nõudeid ei esitata | 8.99675 | 11.2458 | FALSE
SS-02 | Esimene korrus | no | R'w= 49 dB | EI120 | 14.8912 | 16.4656 | FALSE
SS-02 | Esimene korrus | no | R'w= 49 dB | nõudeid ei esitata | 6.38601 | 25.3272 | FALSE
SS-02 | Esimene korrus | no | R'w= 49 dB | nõudeid ei esitata | 3.09001 | 7.15081 | FALSE
SS-02 | Esimene korrus | no | R'w= 49 dB | nõudeid ei esitata | 11.9248 | 17.2296 | FALSE
SS-04 | Esimene korrus | no | R'w= 49 dB | EI60 | 4.48365 | 5.13532 | FALSE
SS-02 | Esimene korrus | no | R'w= 49 dB | EI60 | 4.77788 | 8.78841 | FALSE
SS-02 | Esimene korrus | no | R'w= 49 dB | EI60 | 12.0403 | 12.8707 | FALSE
SS-02 | Esimene korrus | no | R'w= 49 dB | nõudeid ei esitata | 5.636 | 10.6568 | FALSE
SS-02 | Teine korrus | no | R'w=52 dB | nõudeid ei esitata | 15.58 | 20.815 | FALSE
SS-02 | Teine korrus | no | R'w=52 dB | nõudeid ei esitata | 12.8869 | 14.7331 | FALSE
SS-02 | Teine korrus | no | R'w=52 dB | nõudeid ei esitata | 23.0229 | 25.394 | FALSE
SS-02 | Teine korrus | no | R'w=52 dB | EI60 | 22.7925 | 26.2624 | FALSE
2 x SS-02 | Teine korrus | no | R'w=52 dB | nõudeid ei esitata | 12.2262 | 14.5679 | FALSE
SS-02 | Teine korrus | no | R'w=52 dB | nõudeid ei esitata | 4.03278 | 5.45843 | FALSE
SS-02 | Teine korrus | no | R'w=52 dB | EI60 | 4.32589 | 4.8327 | FALSE
SS-02 | Teine korrus | no | R'w=52 dB | nõudeid ei esitata | 3.9496 | 5.35737 | FALSE
SS-02 | Teine korrus | no | R'w=52 dB | EI60 | 3.70842 | 4.74012 | FALSE
SS-02 | Teine korrus | no | R'w=52 dB | nõudeid ei esitata | 12.415 | 19.0548 | FALSE
4 x SS-02 | Teine korrus | no | R'w=52 dB | nõudeid ei esitata | 15.587 | 17.9286 | FALSE
2 x SS-02 | Teine korrus | no | R'w=52 dB | nõudeid ei esitata | 12.1632 | 14.5341 | FALSE
3 x SS-02 | Teine korrus | no | R'w=52 dB | nõudeid ei esitata | 15.4212 | 18.1541 | FALSE
3 x SS-02 | Teine korrus | no | R'w=52 dB | nõudeid ei esitata | 5.3625 | 6.38138 | FALSE
SS-02 | Teine korrus | no | R'w=52 dB | nõudeid ei esitata | 11.8323 | 14.1916 | FALSE
SS-02 | Teine korrus | no | R'w=52 dB | nõudeid ei esitata | 27.6799 | 39.9266 | FALSE
SS-02 | Teine korrus | no | R'w=52 dB | EI60 | 2.8236 | 2.8236 | FALSE
SS-02 | Teine korrus | no | R'w=52 dB | nõudeid ei esitata | 9.82289 | 14.2822 | FALSE
SS-02 | Teine korrus | no | R'w=52 dB | nõudeid ei esitata | 14.4431 | 16.2663 | FALSE
SS-02 | Teine korrus | no | R'w=52 dB | nõudeid ei esitata | 5.55831 | 6.45735 | FALSE
2 x SS-02 | Teine korrus | no | R'w=52 dB | EI60 | 15.4212 | 18.1541 | FALSE
SS-02 | Teine korrus | no | R'w=52 dB | nõudeid ei esitata | 4.48821 | 9.19481 | FALSE
SS-02 | Teine korrus | no | R'w=52 dB | EI60 | 1.7014 | 2.22607 | FALSE
SS-02 | Teine korrus | no | R'w=52 dB | EI60 | 1.7014 | 2.896 | FALSE
SS-02 | Teine korrus | no | R'w=52 dB | EI60 | 5.54045 | 6.11699 | FALSE
SS-02 | Teine korrus | no | R'w=52 dB | nõudeid ei esitata | 15.4212 | 17.2674 | FALSE
SS-02 | Teine korrus | no | R'w=52 dB | EI60 | 4.79049 | 5.092 | FALSE
SS-02 | Teine korrus | no | R'w=52 dB | nõudeid ei esitata | 42.615 | 59.8882 | FALSE
SS-02 | Teine korrus | no | R'w=52 dB | EI60 | 13.7198 | 14.9868 | FALSE
SS-02 | Teine korrus | no | R'w=52 dB | nõudeid ei esitata | 11.4639 | 15.3488 | FALSE
SS-02 | Teine korrus | no | R'w=52 dB | nõudeid ei esitata | 10.3598 | 14.9868 | FALSE
SS-02 | Teine korrus | no | R'w=52 dB | nõudeid ei esitata | 37.8997 | 50.254 | FALSE
SS-02 | Teine korrus | no | R'w=52 dB | EI60 | 4.84658 | 5.55226 | FALSE
SS-02 | Teine korrus | no | R'w=52 dB | EI60 | 4.83622 | 5.34302 | FALSE
SS-02 | Teine korrus | no | R'w=52 dB | nõudeid ei esitata | 4.755 | 7.38987 | FALSE
SS-02 | Teine korrus | yes | R'w=52 dB | EI60 | 10.4618 | 11.1496 | TRUE
SS-02 | Teine korrus | no | R'w=52 dB | EI60 | 50.6574 | 56.3274 | FALSE
SS-02 | Teine korrus | no | R'w=52 dB | nõudeid ei esitata | 19.2429 | 25.394 | FALSE
SS-02 | Teine korrus | no | R'w=52 dB | nõudeid ei esitata | 10.86 | 11.8736 | FALSE
SS-02 | Teine korrus | no | R'w=52 dB | nõudeid ei esitata | 3.26239 | 6.43269 | FALSE
SS-02 | Teine korrus | no | R'w=52 dB | nõudeid ei esitata | 44.2849 | 47.4347 | FALSE

# IfcWallStandardCase: SS-03_Sisesein 190 190 (30)
Classification: 1.24 IfcWallType (sein) (RKAS BIM + ARCHICAD Classification); Material: KON-05_Betoon Plokk - Konstuktsioon 190 mm
Pset_WallCommon - Reference: SS-03; IsExternal: no
AR_Sein - 001_Nimetus: Sisesein; 205_Tüüp: SS-03; 335_Välispiire: no; 340_Soojusläbivus: 0; 376_Viimistlus_väljast: välis pind: Concrete - 10; sisepind: Concrete - 10; 505_Paksus: 190 mm; 376_Viimistlus_väljast (MUDELIS): KON-05_Betoon Plokk - Konstuktsioon
AC_Pset_RenovationAndPhasing - Renovation Status: New
Name | In | LoadBearing | 325_Helipidavus | 330_Tulekindlus | 605_Neto_pindala (m2) | 600_Bruto_pindala (m2) | 500_Kandev
SS-03 | Esimene korrus | yes | R'w=53 dB | EI120 | 26.2927 | 34.7707 | TRUE
SS-03 | Esimene korrus | yes | R'w=53 dB | EI120 | 14.4276 | 16.9653 | TRUE
SS-03 | Esimene korrus | yes | R'w=53 dB | EI120 | 27.5987 | 38.5317 | TRUE
SS-02 | Esimene korrus | yes | R'w=53 dB | EI120 | 12.1203 | 12.1203 | TRUE
SS-03 | Esimene korrus | yes | R'w=53 dB | EI120 | 46.7717 | 51.3545 | TRUE
SS-03 | Esimene korrus | yes | R'w=53 dB | EI120 | 27.6942 | 32.4734 | TRUE
SS-03 | Esimene korrus | yes | R'w=53 dB | nõudeid ei esitata | 3.128 | 7.43271 | TRUE
SS-03 | Esimene korrus | yes | R'w=53 dB | EI120 | 26.7245 | 31.7855 | TRUE
SS-03 | Esimene korrus | yes | R'w=53 dB | EI60 | 9.34202 | 10.6741 | TRUE
SS-03 | Esimene korrus | yes | R'w=53 dB | EI60 | 19.5796 | 24.2712 | TRUE
SS-03 | Esimene korrus | yes | R'w=53 dB | EI60 | 4.15202 | 6.60862 | TRUE
SS-03 | Esimene korrus | yes | R'w=53 dB | nõudeid ei esitata | 45.9681 | 51.3545 | TRUE
SS-02 | Esimene korrus | yes | R'w=53 dB | EI120 | 12.1203 | 12.8423 | TRUE
SS-03 | Esimene korrus | yes | R'w=53 dB | EI120 | 11.4 | 12.844 | TRUE
SS-03 | Esimene korrus | yes | R'w=53 dB | EI120 | 38.8861 | 45.8825 | TRUE
SS-03 | Esimene korrus | yes | R'w=53 dB | EI60 | 61.6818 | 76.5698 | TRUE
SS-02 | Teine korrus | yes | R'w=52 dB | EI60 | 4.46875 | 5.472 | TRUE
SS-03 | Teine korrus | yes | R'w= 58 dB | EI60 | 38.8494 | 43.1648 | TRUE
SS-03 | Teine korrus | yes | R'w= 58 dB | EI60 | 38.4765 | 40.5268 | TRUE
SS-03 | Teine korrus | yes | R'w= 58 dB | EI60 | 21.6975 | 24.2175 | TRUE
SS-03 | Teine korrus | yes | R'w= 58 dB | EI60 | 9.77402 | 12.67 | TRUE
SS-03 | Teine korrus | yes | R'w= 58 dB | EI60 | 38.7929 | 48.3162 | TRUE
SS-03 | Teine korrus | yes | R'w= 58 dB | EI60 | 43.7469 | 45.9988 | TRUE
SS-03 | Teine korrus | yes | R'w= 58 dB | nõudeid ei esitata | 43.8945 | 51.356 | TRUE
SS-03 | Teine korrus | no | R'w= 56 dB | EI60 | 2.78688 | 7.06488 | FALSE
SS-03 | Teine korrus | yes | R'w= 56 dB | nõudeid ei esitata | 5.92065 | 8.5469 | TRUE
SS-03 | Teine korrus | yes | R'w= 58 dB | nõudeid ei esitata | 4.79049 | 5.09198 | TRUE
SS-03 | Teine korrus | yes | R'w= 58 dB | EI60 | 14.4619 | 14.9868 | TRUE
SS-03 | Teine korrus | yes | R'w=52 dB | EI120 | 12.122 | 12.844 | TRUE
SS-03 | Teine korrus | yes | R'w=52 dB | EI120 | 11.3983 | 12.8423 | TRUE

# IfcWallStandardCase: SS-04_Sisesein 240 240 (15)
Classification: 1.24 IfcWallType (sein) (RKAS BIM + ARCHICAD Classification); Material: KON-05_Betoon Plokk - Konstuktsioon 240 mm
Pset_WallCommon - Reference: SS-04; IsExternal: no
AR_Sein - 001_Nimetus: Sisesein; 205_Tüüp: SS-04; 335_Välispiire: no; 376_Viimistlus_väljast: välis pind: Concrete - 10; sisepind: Concrete - 10; 505_Paksus: 240 mm; 376_Viimistlus_väljast (MUDELIS): KON-05_Betoon Plokk - Konstuktsioon
AC_Pset_RenovationAndPhasing - Renovation Status: New
Name | In | LoadBearing | 325_Helipidavus | 330_Tulekindlus | 340_Soojusläbivus | 605_Neto_pindala (m2) | 600_Bruto_pindala (m2) | 500_Kandev
SS-04 | Esimene korrus | yes | R'w= 55 dB | EI120 | 0 | 10.4378 | 17.9778 | TRUE
SS-04 | Esimene korrus | yes | R'w= 55 dB | nõudeid ei esitata | 0 | 12.8016 | 14.5662 | TRUE
SS-04 | Esimene korrus | yes | R'w= 55 dB | EI60 | 0 | 22.836 | 24.9812 | TRUE
SS-04 | Esimene korrus | no | nõuded ei esitata | nõudeid ei esitata |  | 4.80786 | 4.91186 | FALSE
SS-04 | Esimene korrus | yes | R'w= 55 dB | EI60 | 0 | 10.7781 | 12.8781 | TRUE
SS-04 | Esimene korrus | yes | R'w= 55 dB | nõudeid ei esitata | 0 | 27.1101 | 34.6701 | TRUE
SS-04 | Esimene korrus | yes | R'w= 55 dB | EI60 | 0 | 10.9788 | 13.0788 | TRUE
SS-04 | Esimene korrus | yes | R'w= 55 dB | EI120 | 0 | 23.3565 | 30.9165 | TRUE
SS-04 | Esimene korrus | yes | R'w= 55 dB | nõudeid ei esitata | 0 | 14.8936 | 19.3036 | TRUE
SS-04 | Esimene korrus | yes | R'w= 55 dB | nõudeid ei esitata | 0 | 9.712 | 13.072 | TRUE
SS-04 | Esimene korrus | yes | R'w= 55 dB | EI120 | 0 | 8.82029 | 11.3403 | TRUE
SS-04 | Teine korrus | yes | R'w= 55 dB | EI60 | 0 | 92.5913 | 120.087 | TRUE
SS-04 | Teine korrus | yes | R'w= 55 dB | nõudeid ei esitata | 0 | 20.5615 | 26.4157 | TRUE
SS-04 | Teine korrus | yes | R'w= 55 dB | nõudeid ei esitata | 0 | 40.8304 | 53.4304 | TRUE
SS-04 | Teine korrus | yes | R'w= 55 dB | EI60 | 0 | 3.4028 | 3.4028 | TRUE

# IfcWallStandardCase: SS-06_Sisesein - 90 blokk 90 (2)
In: Teine korrus
Classification: 1.24 IfcWallType (sein) (RKAS BIM + ARCHICAD Classification); Material: KON-05_Betoon Plokk - Konstuktsioon 90 mm
AR_Sein - 340_Soojusläbivus: 0; 001_Nimetus: Sisesein; 205_Tüüp: SS-06; 330_Tulekindlus: nõudeid ei esitata; 335_Välispiire: no; 376_Viimistlus_väljast: välis pind: Concrete - 10; sisepind: Concrete - 10; 505_Paksus: 90 mm; 500_Kandev: FALSE; 376_Viimistlus_väljast (MUDELIS): KON-05_Betoon Plokk - Konstuktsioon
Pset_WallCommon - Reference: SS-06; LoadBearing: no; IsExternal: no
AC_Pset_RenovationAndPhasing - Renovation Status: New
Name | 325_Helipidavus | 605_Neto_pindala (m2) | 600_Bruto_pindala (m2)
SS-06 | R'w= 45 dB | 5.32675 | 6.194
SS-06 | R'w= 47 dB | 1.43 | 2.3688

# IfcWallStandardCase: SS-09 remondikanali sein 250 (4)
In: Vundament
Classification: 1.24 IfcWallType (sein) (RKAS BIM + ARCHICAD Classification); Material: KON-04_Betoon - Konstuktsioon 250 mm
Pset_WallCommon - Reference: SS-09 remondikanali sein; LoadBearing: yes
AR_Sein - 205_Tüüp: SS-09 remondikanali sein; 325_Helipidavus: nõuded ei esitata; 330_Tulekindlus: nõudeid ei esitata; 376_Viimistlus_väljast: välis pind: Concrete - 04; sisepind: Concrete - 04; 505_Paksus: 250 mm; 500_Kandev: TRUE; 376_Viimistlus_väljast (MUDELIS): KON-04_Betoon - Konstuktsioon
AC_Pset_RenovationAndPhasing - Renovation Status: New
Name | IsExternal = 335_Välispiire | 605_Neto_pindala (m2) | 600_Bruto_pindala (m2)
Välissein | yes | 2.19942 | 2.59931
SS-09 | no | 17.195 | 17.195 | AR_Sein - 001_Nimetus: Sisesein; 340_Soojusläbivus: 0
Välissein | yes | 1.59954 | 2.39931
Välissein | yes | 16.8543 | 17.2542

# IfcWallStandardCase: SS-10_Sisesein SW-paneel 80 80 (3)
Classification: 1.24 IfcWallType (sein) (RKAS BIM + ARCHICAD Classification); Material: SOJ-02_Soojustus - Fiiber Kõva 80 mm
Pset_WallCommon - Reference: SS-10; LoadBearing: no; IsExternal: no
AR_Sein - 001_Nimetus: Sisesein; 205_Tüüp: SS-10; 330_Tulekindlus: nõudeid ei esitata; 335_Välispiire: no; 376_Viimistlus_väljast: välis pind: Insulation - Fiberglass; sisepind: Insulation - Fiberglass; 505_Paksus: 80 mm; 500_Kandev: FALSE; 376_Viimistlus_väljast (MUDELIS): SOJ-02_Soojustus - Fiiber Kõva
AC_Pset_RenovationAndPhasing - Renovation Status: New
Name | In | 325_Helipidavus | 605_Neto_pindala (m2) | 600_Bruto_pindala (m2)
SS-10 | Esimene korrus | R'w= 52 dB | 5.37506 | 8.02676
SS-10 | Esimene korrus | R'w= 52 dB | 2.41899 | 4.4639
SS-10 | Teine korrus | nõudeid ei esitata | 26.9962 | 28.8862 | AR_Sein - 340_Soojusläbivus: 0

# IfcWallStandardCase: VS-05_välissein - fassaadilamell 50, VS-05
In: Esimene korrus
Classification: 1.24 IfcWallType (sein) (RKAS BIM + ARCHICAD Classification); Material: Õhkvahe - Raam 50 mm
AR_Sein - 340_Soojusläbivus: 0; 001_Nimetus: välissein; 205_Tüüp: VS-05; 325_Helipidavus: nõuded ei esitata; 330_Tulekindlus: nõudeid ei esitata; 335_Välispiire: yes; 376_Viimistlus_väljast: välis pind: Glass-Clear; sisepind: Glass-Clear; 505_Paksus: 50 mm; 605_Neto_pindala: 11.55 m2; 600_Bruto_pindala: 14 m2; 500_Kandev: FALSE; 376_Viimistlus_väljast (MUDELIS): Õhkvahe - Raam
Pset_WallCommon - Reference: VS-05; LoadBearing: no; IsExternal: yes
AC_Pset_RenovationAndPhasing - Renovation Status: New

# IfcWallStandardCase: VS-07_paneelvälissein külm 200 (2)
In: Esimene korrus
Classification: 1.24 IfcWallType (sein) (RKAS BIM + ARCHICAD Classification); Material: KON-04_Betoon - Konstuktsioon 200 mm
AR_Sein - 205_Tüüp: VS-07; 325_Helipidavus: nõuded ei esitata; 330_Tulekindlus: nõudeid ei esitata; 376_Viimistlus_väljast: välis pind: Paint - Anthracite; sisepind: Paint - Anthracite; 505_Paksus: 200 mm; 500_Kandev: TRUE; 376_Viimistlus_väljast (MUDELIS): KON-04_Betoon - Konstuktsioon
Pset_WallCommon - Reference: VS-07; LoadBearing: yes
AC_Pset_RenovationAndPhasing - Renovation Status: New
Name | 335_Välispiire = IsExternal | 605_Neto_pindala (m2) | 600_Bruto_pindala (m2)
VS-07 | yes | 13.3 | 13.3 | AR_Sein - 340_Soojusläbivus: 0
SS-04 | no | 4.79993 | 4.99993 | AR_Sein - 001_Nimetus: Sisesein

# IfcWallStandardCase: VS-08_välissein parapett 100 (14)
Classification: 1.24 IfcWallType (sein) (RKAS BIM + ARCHICAD Classification); Material: KON-04_Betoon - Konstuktsioon 100 mm
AR_Sein - 205_Tüüp: VS-08; 325_Helipidavus: nõuded ei esitata; 330_Tulekindlus: nõudeid ei esitata; 335_Välispiire: yes; 376_Viimistlus_väljast: välis pind: Paint - Anthracite; sisepind: Concrete - 04; 505_Paksus: 100 mm; 500_Kandev: TRUE; 376_Viimistlus_väljast (MUDELIS): KON-04_Betoon - Konstuktsioon
Pset_WallCommon - Reference: VS-08; LoadBearing: yes; IsExternal: yes
AC_Pset_RenovationAndPhasing - Renovation Status: New
Name | In | 605_Neto_pindala (m2) | 600_Bruto_pindala (m2)
VS-08 | Teine korrus | 20.278 | 20.278 | AR_Sein - 340_Soojusläbivus: 0; 001_Nimetus: välissein
VS-08 | Teine korrus | 5.87933 | 5.99932 | AR_Sein - 340_Soojusläbivus: 0; 001_Nimetus: välissein
VS-08 | Katusekorrus | 84.8167 | 84.8167
VS-08 | Katusekorrus | 20.304 | 20.424
VS-08 | Katusekorrus | 12.624 | 12.624
VS-08 | Katusekorrus | 52.0326 | 52.0326
VS-08 | Katusekorrus | 20.2803 | 20.4003
VS-08 | Katusekorrus | 5.87991 | 6.11991
VS-08 | Katusekorrus | 45.9839 | 46.2239
VS-08 | Katusekorrus | 19.68 | 19.92
VS-08 | Korrus +9.900 | 2.97776 | 3.13366
2 x VS-08 | Korrus +9.900 | 3.1333 | 3.1333
VS-08 | Korrus +9.900 | 0.955 | 1.005

# IfcWallStandardCase: VS-09 sein aedikute vahel 140, VS-09
In: Esimene korrus
Classification: 1.24 IfcWallType (sein) (RKAS BIM + ARCHICAD Classification); Material: KON-04_Betoon - Konstuktsioon 140 mm
AR_Sein - 340_Soojusläbivus: 0; 001_Nimetus: välissein; 205_Tüüp: VS-09 sein aedikute vahel; 325_Helipidavus: nõuded ei esitata; 330_Tulekindlus: nõudeid ei esitata; 335_Välispiire: yes; 376_Viimistlus_väljast: välis pind: Glass-Clear; sisepind: Glass-Clear; 505_Paksus: 140 mm; 605_Neto_pindala: 6.5784 m2; 600_Bruto_pindala: 8.0204 m2; 500_Kandev: FALSE; 376_Viimistlus_väljast (MUDELIS): KON-04_Betoon - Konstuktsioon
Pset_WallCommon - Reference: VS-09 sein aedikute vahel; LoadBearing: no; IsExternal: yes
AC_Pset_RenovationAndPhasing - Renovation Status: New

# IfcWallStandardCase: VS-12_välissein - met-võrk koera aia ees 50 (2)
In: Esimene korrus
Classification: 1.24 IfcWallType (sein) (RKAS BIM + ARCHICAD Classification); Material: Õhkvahe - Raam 50 mm
AR_Sein - 340_Soojusläbivus: 0; 205_Tüüp: VS-12; 325_Helipidavus: nõuded ei esitata; 330_Tulekindlus: nõudeid ei esitata; 335_Välispiire: yes; 376_Viimistlus_väljast: välis pind: Glass-Clear; sisepind: Glass-Clear; 505_Paksus: 50 mm; 500_Kandev: FALSE; 376_Viimistlus_väljast (MUDELIS): Õhkvahe - Raam
Pset_WallCommon - Reference: VS-12; LoadBearing: no; IsExternal: yes
AC_Pset_RenovationAndPhasing - Renovation Status: New
Name | 605_Neto_pindala (m2) | 600_Bruto_pindala (m2)
VS-12 | 4.63413 | 6.91613
VS-12 | 4.63332 | 6.52332

# IfcWallStandardCase: VS-21_Välissein jarjutustorn 150mm 150 (3)
Classification: 1.24 IfcWallType (sein) (RKAS BIM + ARCHICAD Classification); Material: Betoon 150 mm
AR_Sein - 205_Tüüp: VS-21; 325_Helipidavus: nõuded ei esitata; 330_Tulekindlus: nõudeid ei esitata; 335_Välispiire: yes; 376_Viimistlus_väljast: välis pind: Paint - Anthracite; sisepind: Concrete - 04; 505_Paksus: 150 mm; 500_Kandev: TRUE; 376_Viimistlus_väljast (MUDELIS): Betoon
Pset_WallCommon - Reference: VS-21; LoadBearing: yes; IsExternal: yes
AC_Pset_RenovationAndPhasing - Renovation Status: New
Name | In | 340_Soojusläbivus | 605_Neto_pindala (m2) | 600_Bruto_pindala (m2)
VS-22 | Esimene korrus | 0 | 16.9525 | 18.3025
VS-21 | Teine korrus | 0 | 16.8755 | 20.4167 | AR_Sein - 001_Nimetus: välissein
VS-21 | Teine korrus |  | 2.67596 | 2.84195

# IfcWallStandardCase: VS-22_välissein harjutustorn sokkel 200mm 200 (5)
In: Vundament
Classification: 1.24 IfcWallType (sein) (RKAS BIM + ARCHICAD Classification); Material: Betoon 200 mm
AR_Sein - 340_Soojusläbivus: 0; 205_Tüüp: VS-22; 325_Helipidavus: nõuded ei esitata; 330_Tulekindlus: nõudeid ei esitata; 335_Välispiire: yes; 376_Viimistlus_väljast: välis pind: Paint - Anthracite; sisepind: Concrete - 04; 505_Paksus: 200 mm; 500_Kandev: TRUE; 376_Viimistlus_väljast (MUDELIS): Betoon
Pset_WallCommon - Reference: VS-22; LoadBearing: yes; IsExternal: yes
AC_Pset_RenovationAndPhasing - Renovation Status: New
Name | 605_Neto_pindala (m2) | 600_Bruto_pindala (m2)
VS-22 | 7.65418 | 7.65418
2 x VS-22 | 1.5 | 1.79995
VS-22 | 1.09966 | 1.79942
VS-22 | 1.10005 | 1.79988

# IfcWallStandardCase: VS-23_välissein harjutustorn sokkel 120mm 120 (5)
In: Vundament
Classification: 1.24 IfcWallType (sein) (RKAS BIM + ARCHICAD Classification); Material: Betoon 120 mm
AR_Sein - 340_Soojusläbivus: 0; 205_Tüüp: VS-23; 325_Helipidavus: nõuded ei esitata; 330_Tulekindlus: nõudeid ei esitata; 335_Välispiire: yes; 376_Viimistlus_väljast: välis pind: Paint - Anthracite; sisepind: Concrete - 04; 505_Paksus: 120 mm; 500_Kandev: TRUE; 376_Viimistlus_väljast (MUDELIS): Betoon
Pset_WallCommon - Reference: VS-23; LoadBearing: yes; IsExternal: yes
AC_Pset_RenovationAndPhasing - Renovation Status: New
Name | 605_Neto_pindala (m2) | 600_Bruto_pindala (m2)
VS-22 | 3.83542 | 4.0954
VS-22 | 0.350941 | 0.351047
VS-23 | 7.49824 | 7.65418
VS-22 | 6.04556 | 6.46158
VS-22 | 1.55004 | 1.55004

# IfcWallStandardCase: VS-32_garaazi sokkel 120 (7)
In: Esimene korrus
Classification: 1.24 IfcWallType (sein) (RKAS BIM + ARCHICAD Classification); Material: KON-04_Betoon - Konstuktsioon 120 mm
AR_Sein - 340_Soojusläbivus: 0; 205_Tüüp: VS-32; 325_Helipidavus: nõuded ei esitata; 330_Tulekindlus: nõudeid ei esitata; 335_Välispiire: yes; 376_Viimistlus_väljast: välis pind: Paint - Glossy White; sisepind: Paint - Glossy White; 505_Paksus: 120 mm; 500_Kandev: TRUE; 376_Viimistlus_väljast (MUDELIS): KON-04_Betoon - Konstuktsioon
Pset_WallCommon - Reference: VS-32; LoadBearing: yes; IsExternal: yes
AC_Pset_RenovationAndPhasing - Renovation Status: New
Name | 605_Neto_pindala (m2) | 600_Bruto_pindala (m2)
VS-42 | 5.9877 | 5.9877
VS-32 | 10.1475 | 10.2069
VS-42 | 5.9283 | 5.9877
VS-42 | 0.852 | 6.186
VS-42 | 0.632025 | 1.97505
VS-42 | 0.104869 | 0.163285
VS-42 | 0.15033 | 0.198174

# IfcWallStandardCase: VS-42_välissein PPA varjualune met-võrk 50, VS-42
In: Esimene korrus
Classification: 1.24 IfcWallType (sein) (RKAS BIM + ARCHICAD Classification); Material: Õhkvahe - Raam 50 mm
Pset_WallCommon - Reference: VS-42; LoadBearing: no; IsExternal: no
AR_Sein - 001_Nimetus: Sisesein; 205_Tüüp: VS-42; 325_Helipidavus: nõideid ei esitata; 330_Tulekindlus: nõudeid ei esitata; 335_Välispiire: no; 340_Soojusläbivus: 0; 376_Viimistlus_väljast: välis pind: Paint - Titanium White; sisepind: Paint - Titanium White; 505_Paksus: 50 mm; 605_Neto_pindala: 17.0387 m2; 600_Bruto_pindala: 17.802 m2; 500_Kandev: FALSE; 376_Viimistlus_väljast (MUDELIS): Õhkvahe - Raam
AC_Pset_RenovationAndPhasing - Renovation Status: New

# IfcWallStandardCase: VS-43_välissein 190 PPA sokkel 190 (4)
In: Esimene korrus
Classification: 1.24 IfcWallType (sein) (RKAS BIM + ARCHICAD Classification); Material: KON-05_Betoon Plokk - Konstuktsioon 190 mm
AR_Sein - 340_Soojusläbivus: 0; 205_Tüüp: VS-43; 325_Helipidavus: nõuded ei esitata; 330_Tulekindlus: nõudeid ei esitata; 335_Välispiire: yes; 376_Viimistlus_väljast: välis pind: Paint - Glossy White; sisepind: Paint - Glossy White; 505_Paksus: 190 mm; 500_Kandev: TRUE; 376_Viimistlus_väljast (MUDELIS): KON-05_Betoon Plokk - Konstuktsioon
Pset_WallCommon - Reference: VS-43; LoadBearing: yes; IsExternal: yes
AC_Pset_RenovationAndPhasing - Renovation Status: New
Name | 605_Neto_pindala (m2) | 600_Bruto_pindala (m2)
VS-43 | 2.49233 | 2.55172
VS-42 | 5.85023 | 9.69705
VS-42 | 1.4535 | 2.55172
VS-42 | 1.4535 | 2.54677

# IfcWallStandardCase: VS-60_Välissein lõhkeainehoidla 300 (4)
In: Esimene korrus
Classification: 1.24 IfcWallType (sein) (RKAS BIM + ARCHICAD Classification); Material: KON-04_Betoon - Konstuktsioon 300 mm
AR_Sein - 340_Soojusläbivus: 0; 205_Tüüp: VS-60; 325_Helipidavus: nõuded ei esitata; 330_Tulekindlus: nõudeid ei esitata; 335_Välispiire: yes; 376_Viimistlus_väljast: välis pind: Concrete - 04; sisepind: Concrete - 04; 505_Paksus: 300 mm; 500_Kandev: TRUE; 376_Viimistlus_väljast (MUDELIS): KON-04_Betoon - Konstuktsioon
Pset_WallCommon - Reference: VS-60; LoadBearing: yes; IsExternal: yes
AC_Pset_RenovationAndPhasing - Renovation Status: New
Name | 605_Neto_pindala (m2) | 600_Bruto_pindala (m2)
VS-60 | 11.2425 | 11.2425
VS-60 | 5.42033 | 6.02261
VS-60 | 10.6403 | 11.2425
VS-60 | 2.21506 | 6.01962

# IfcWallStandardCase: Õhkvahe 200, SS-16
In: Esimene korrus
Classification: 1.24 IfcWallType (sein) (RKAS BIM + ARCHICAD Classification); Material: Õhkvahe 200 mm
Pset_WallCommon - Reference: Õhkvahe; LoadBearing: no; IsExternal: no
AR_Sein - 001_Nimetus: Sisesein; 205_Tüüp: Õhkvahe; 325_Helipidavus: R'w= 52 dB; 330_Tulekindlus: nõudeid ei esitata; 335_Välispiire: no; 376_Viimistlus_väljast: välis pind: Metal - Steel; sisepind: Metal - Steel; 505_Paksus: 200 mm; 605_Neto_pindala: 0.0609018 m2; 600_Bruto_pindala: 0.0609018 m2; 500_Kandev: FALSE; 376_Viimistlus_väljast (MUDELIS): Õhkvahe
AC_Pset_RenovationAndPhasing - Renovation Status: Existing

# IfcWindow: Glass Block Wall 23 (2)
In: Teine korrus
Type - OperationType: USERDEFINED; ParameterTakesPrecedence: no; Sizeable: no
OverallHeight: 1000 mm; OverallWidth: 2000 mm; Classification: 1.25 IfcWindowStyle (aken) (RKAS BIM + ARCHICAD Classification)
Pset_WindowCommon - Reference: VR-02; ThermalTransmittance: 0; GlazingAreaFraction: 1.7745; IsExternal: yes
AR_Aken - 001_Nimetus: ventilatsioonirest; 300_Tüüp: VR-02; 305_Ava_mõõt: 2 000x1 000; 310_Materjal: Alumiinium; 315_Avanemine: mitteavatav; 320_Klaas: ilma klaasita; 325_Helipidavus: R´w ≥35 dB; 330_Tulekindlus: nõudeid ei esitata; 335_Välispiire: yes; 340_Soojusläbivus: 0.8; 345_Päikesekiirgus_tegur: nõudeid ei esitata; 350_Klaaspakett: ilma klaasita; 355_Pindala: 2 m2; 376_Viimistlus_väljast: MUDELIS: Wood - Pine Grained Horizontal; Wood - Pine Grained Horizontal; MÄRKUS:; 900_Tootja: Undefined; 905_Mudel: Undefined; 910_Tooteinfo: Undefined; 915_Kasutus-ja_hooldusjuhend: Undefined
AC_Pset_RenovationAndPhasing - Renovation Status: New

# IfcWindow: Glass Block Wall 23, VR-01
In: Esimene korrus
Type - OperationType: USERDEFINED; ParameterTakesPrecedence: no; Sizeable: no
Type - Window Panel Properties - Panel 1 - OperationType: TILTANDTURNRIGHTHAND; PanelPosition: MIDDLE; FrameDepth: 50 mm; FrameThickness: 50 mm
OverallHeight: 2000 mm; OverallWidth: 700 mm; Classification: 1.25 IfcWindowStyle (aken) (RKAS BIM + ARCHICAD Classification)
Pset_WindowCommon - Reference: VR-01; ThermalTransmittance: 0; GlazingAreaFraction: 0.91; IsExternal: yes
AR_Aken - 001_Nimetus: ventilatsioonirest; 300_Tüüp: VR-01; 305_Ava_mõõt: 700x2 000; 310_Materjal: Alumiinium; 315_Avanemine: mitteavatav; 320_Klaas: ilma klaasita; 325_Helipidavus: nõudeid ei mesitata; 330_Tulekindlus: nõudeid ei esitata; 335_Välispiire: yes; 340_Soojusläbivus: 0; 345_Päikesekiirgus_tegur: nõudeid ei esitata; 350_Klaaspakett: ilma klaasita; 355_Pindala: 2 m2; 376_Viimistlus_väljast: MUDELIS: Wood - Pine Grained Horizontal; Wood - Pine Grained Horizontal; MÄRKUS:; 900_Tootja: Undefined; 905_Mudel: Undefined; 910_Tooteinfo: Undefined; 915_Kasutus-ja_hooldusjuhend: Undefined
AC_Pset_RenovationAndPhasing - Renovation Status: New

# IfcWindow: Skylight Dome Rect 23 (19)
In: Katusekorrus
Type - ParameterTakesPrecedence: no; Sizeable: no
Classification: 1.25 IfcWindowStyle (aken) (RKAS BIM + ARCHICAD Classification)
AR_Aken - 340_Soojusläbivus: 0; 355_Pindala: 0 m2; 305_Ava_mõõt: 1 200x1 363; 320_Klaas: polükarbonaat; 325_Helipidavus: nõudeid ei esitata; 330_Tulekindlus: nõudeid ei esitata; 335_Välispiire: yes; 345_Päikesekiirgus_tegur: nõudeid ei esitata; 350_Klaaspakett: polükarbonaat; 900_Tootja: Undefined; 905_Mudel: Undefined; 910_Tooteinfo: Undefined; 915_Kasutus-ja_hooldusjuhend: Undefined
Pset_WindowCommon - ThermalTransmittance: 0; IsExternal: yes
AC_Pset_RenovationAndPhasing - Renovation Status: New
Name | 300_Tüüp = Reference | 310_Materjal | 315_Avanemine | 001_Nimetus
SUITSULUUK SL-01 | SUITSULUUK SL-01 | Puit konstruktsioon | avanev
2 x KATUSAKEN KA-01 | KATUSAKEN KA-01 |  | avatav | katuseaken
12 x SUITSULUUK SL-01 | SUITSULUUK SL-01 | Puit konstruktsioon | avatav | suitsuluuk
4 x SUITSULUUK SL-01 | SUITSULUUK SL-01 | Puit konstruktsioon | avatav

# IfcWindow: Triple Window 23 (2)
In: Esimene korrus
Type - OperationType: TRIPLE_PANEL_VERTICAL; ParameterTakesPrecedence: no; Sizeable: no
Type - Window Lining Properties - LiningDepth: 50 mm; LiningThickness: 50 mm; MullionThickness: 50 mm; FirstMullionOffset: 0.4; SecondMullionOffset: 0.6
Type - Window Panel Properties - Panel 1 - OperationType: FIXEDCASEMENT; PanelPosition: LEFT
Type - Window Panel Properties - Panel 2 - OperationType: TILTANDTURNLEFTHAND; PanelPosition: MIDDLE; FrameDepth: 50 mm; FrameThickness: 50 mm
Type - Window Panel Properties - Panel 3 - OperationType: FIXEDCASEMENT; PanelPosition: RIGHT
OverallHeight: 2400 mm; OverallWidth: 3500 mm; Classification: 1.25 IfcWindowStyle (aken) (RKAS BIM + ARCHICAD Classification)
Pset_WindowCommon - Reference: A-03; ThermalTransmittance: 0; GlazingAreaFraction: 7.19247; IsExternal: yes
AR_Aken - 001_Nimetus: Välisaken; 300_Tüüp: A-03; 305_Ava_mõõt: 3 500x2 400; 310_Materjal: Alumiinium; 315_Avanemine: kald-põõrdavatav osaliselt ; ARCHICAD tüüp: Tilt-Turn; 320_Klaas: 3xklaaspakett; 325_Helipidavus: R´w ≥35 dB; 330_Tulekindlus: nõudeid ei esitata; 335_Välispiire: yes; 340_Soojusläbivus: 0.8; 345_Päikesekiirgus_tegur: 0,4; 350_Klaaspakett: 3xklaaspakett; 355_Pindala: 8.4 m2; 375_Viimistlus_seest: MUDELIS: Metal - Stainless Steel; Metal - Stainless Steel; MÄRKUS:; 376_Viimistlus_väljast: MUDELIS: Metal - Stainless Steel; Metal - Stainless Steel; MÄRKUS:; 900_Tootja: Undefined; 905_Mudel: Undefined; 910_Tooteinfo: Undefined; 915_Kasutus-ja_hooldusjuhend: Undefined
AC_Pset_RenovationAndPhasing - Renovation Status: New

# IfcWindow: Window 23 (16)
Type - OperationType: SINGLE_PANEL; ParameterTakesPrecedence: no; Sizeable: no
Type - Window Lining Properties - LiningDepth: 50 mm; LiningThickness: 50 mm
Type - Window Panel Properties - Panel 1 - OperationType: FIXEDCASEMENT; PanelPosition: MIDDLE; FrameDepth: 50 mm; FrameThickness: 50 mm
Classification: 1.25 IfcWindowStyle (aken) (RKAS BIM + ARCHICAD Classification)
Pset_WindowCommon - ThermalTransmittance: 0
AR_Aken - 310_Materjal: Alumiinium; 340_Soojusläbivus: 0.8; 345_Päikesekiirgus_tegur: nõudeid ei esitata; 375_Viimistlus_seest: MUDELIS: Paint - Glossy White; Paint - Glossy White; MÄRKUS:; 376_Viimistlus_väljast: MUDELIS: Paint - Glossy White; Paint - Glossy White; MÄRKUS:; 900_Tootja: Undefined; 905_Mudel: Undefined; 910_Tooteinfo: Undefined; 915_Kasutus-ja_hooldusjuhend: Undefined
AC_Pset_RenovationAndPhasing - Renovation Status: New
Name | In | OverallHeight (mm) | OverallWidth (mm) | Reference = 300_Tüüp | GlazingAreaFraction | IsExternal = 335_Välispiire | 001_Nimetus | 305_Ava_mõõt | 315_Avanemine | 320_Klaas = 350_Klaaspakett | 325_Helipidavus | 330_Tulekindlus | 355_Pindala (m2)
2 x TA-02 | Esimene korrus | 2000 | 1400 | TA-02 | 2.3125 | no | tuletõkke siseaken | 1 400x2 000 | mitteavanev ; ARCHICAD tüüp: Fixed Sash | tuletõkkeklaas | 30dB | EI30 | 2.8
6 x TA-01 | Teine korrus | 2000 | 700 | TA-01 | 1.0175 | no | tuletõkke siseaken | 700x2 000 | mitteavanev ; ARCHICAD tüüp: Fixed Sash | tuletõkkeklaas | 30dB | EI30 | 1.4
6 x TA-02 | Teine korrus | 2000 | 1400 | TA-02 | 2.3125 | no | tuletõkke siseaken | 1 400x2 000 | mitteavanev ; ARCHICAD tüüp: Fixed Sash | tuletõkkeklaas | 30dB | EI30 | 2.8
2 x A-04 | Teine korrus | 700 | 700 | A-04 | 0.3025 | yes | Välisaken | 700x700 | kaldpöördavatav ; ARCHICAD tüüp: Fixed Sash | 3xklaaspakett | R´w ≥35 dB | nõudeid ei esitata | 0.49

# IfcWindow: Window 23 (19)
Type - OperationType: SINGLE_PANEL; ParameterTakesPrecedence: no; Sizeable: no
Type - Window Lining Properties - LiningDepth: 50 mm; LiningThickness: 50 mm
Type - Window Panel Properties - Panel 1 - OperationType: SIDEHUNGLEFTHAND; PanelPosition: MIDDLE; FrameDepth: 50 mm; FrameThickness: 50 mm
Classification: 1.25 IfcWindowStyle (aken) (RKAS BIM + ARCHICAD Classification)
Pset_WindowCommon - ThermalTransmittance: 0
AR_Aken - 310_Materjal: Alumiinium; 340_Soojusläbivus: 0.8; 900_Tootja: Undefined; 905_Mudel: Undefined; 910_Tooteinfo: Undefined; 915_Kasutus-ja_hooldusjuhend: Undefined
AC_Pset_RenovationAndPhasing - Renovation Status: New
Name | In | OverallHeight (mm) | OverallWidth (mm) | Reference = 300_Tüüp | GlazingAreaFraction | IsExternal = 335_Välispiire | 001_Nimetus | 305_Ava_mõõt | 315_Avanemine | 320_Klaas = 350_Klaaspakett | 325_Helipidavus | 330_Tulekindlus | 345_Päikesekiirgus_tegur | 355_Pindala (m2) | 375_Viimistlus_seest = 376_Viimistlus_väljast
2 x A-05 | Esimene korrus | 700 | 900 | A-05 | 0.4125 | no | tuletõkke siseaken | 900x700 | mitteavanev - Vasak ; ARCHICAD tüüp: Side Hung | tuletõkkeklaas | 30dB | EI30 | nõudeid ei esitata | 0.63 | MUDELIS: Wood - Pine Grained Horizontal; Wood - Pine Grained Horizontal; MÄRKUS:
3 x A-01 | Esimene korrus | 2000 | 700 | A-01 | 1.0175 | yes | Välisaken | 700x2 000 | avatav - Vasak ; ARCHICAD tüüp: Side Hung | 3xklaaspakett | R´w ≥35 dB | nõudeid ei esitata | nõudeid ei esitata | 1.4 | MUDELIS: Paint - Glossy White; Paint - Glossy White; MÄRKUS:
A-01 | Esimene korrus | 2000 | 700 | A-01 | 1.0175 | yes | Välisaken | 700x2 000 | kaldpöördavanev - Vasak ; ARCHICAD tüüp: Side Hung | 3xklaaspakett | R´w ≥35 dB | nõudeid ei esitata | nõudeid ei esitata | 1.4 | MUDELIS: Paint - Glossy White; Paint - Glossy White; MÄRKUS:
2 x A-01 | Esimene korrus | 2000 | 700 | A-01 | 1.0175 | yes | Välisaken | 700x2 000 | kaldpöördavanev - Vasak ; ARCHICAD tüüp: Side Hung | 3xklaaspakett | R´w ≥35 dB | nõudeid ei esitata | nõudeid eiesitata | 1.4 | MUDELIS: Paint - Glossy White; Paint - Glossy White; MÄRKUS:
11 x A-01 | Teine korrus | 2000 | 700 | A-01 | 1.0175 | yes | Välisaken | 700x2 000 | kaldpöördavatav - Vasak ; ARCHICAD tüüp: Side Hung | 3xklaaspakett | R´w ≥35 dB | nõudeid ei esitata | nõudeid ei esitata | 1.4 | MUDELIS: Paint - Glossy White; Paint - Glossy White; MÄRKUS:

# IfcWindow: Window 23 (4)
Type - OperationType: SINGLE_PANEL; ParameterTakesPrecedence: no; Sizeable: no
Type - Window Lining Properties - LiningDepth: 50 mm; LiningThickness: 50 mm
Type - Window Panel Properties - Panel 1 - OperationType: SIDEHUNGRIGHTHAND; PanelPosition: MIDDLE; FrameDepth: 50 mm; FrameThickness: 50 mm
OverallHeight: 2000 mm; OverallWidth: 700 mm; Classification: 1.25 IfcWindowStyle (aken) (RKAS BIM + ARCHICAD Classification)
Pset_WindowCommon - Reference: A-01; ThermalTransmittance: 0; GlazingAreaFraction: 1.0175; IsExternal: yes
AR_Aken - 001_Nimetus: Välisaken; 300_Tüüp: A-01; 305_Ava_mõõt: 700x2 000; 310_Materjal: Alumiinium; 320_Klaas: 3xklaaspakett; 325_Helipidavus: R´w ≥35 dB; 330_Tulekindlus: nõudeid ei esitata; 335_Välispiire: yes; 340_Soojusläbivus: 0.8; 345_Päikesekiirgus_tegur: nõudeid ei esitata; 350_Klaaspakett: 3xklaaspakett; 355_Pindala: 1.4 m2; 375_Viimistlus_seest: MUDELIS: Paint - Glossy White; Paint - Glossy White; MÄRKUS:; 376_Viimistlus_väljast: MUDELIS: Paint - Glossy White; Paint - Glossy White; MÄRKUS:; 900_Tootja: Undefined; 905_Mudel: Undefined; 910_Tooteinfo: Undefined; 915_Kasutus-ja_hooldusjuhend: Undefined
AC_Pset_RenovationAndPhasing - Renovation Status: New
Name | In | 315_Avanemine
A-01 | Esimene korrus | avatav - Parem ; ARCHICAD tüüp: Side Hung
3 x A-01 | Teine korrus | kaldpöördavatav - Parem ; ARCHICAD tüüp: Side Hung

# IfcWindow: Window 23 (26)
Type - OperationType: SINGLE_PANEL; ParameterTakesPrecedence: no; Sizeable: no
Type - Window Lining Properties - LiningDepth: 50 mm; LiningThickness: 50 mm
Type - Window Panel Properties - Panel 1 - OperationType: TILTANDTURNLEFTHAND; PanelPosition: MIDDLE; FrameDepth: 50 mm; FrameThickness: 50 mm
Classification: 1.25 IfcWindowStyle (aken) (RKAS BIM + ARCHICAD Classification)
Pset_WindowCommon - ThermalTransmittance: 0; IsExternal: yes
AR_Aken - 001_Nimetus: Välisaken; 310_Materjal: Alumiinium; 330_Tulekindlus: nõudeid ei esitata; 335_Välispiire: yes; 345_Päikesekiirgus_tegur: nõudeid ei esitata; 900_Tootja: Undefined; 905_Mudel: Undefined; 910_Tooteinfo: Undefined; 915_Kasutus-ja_hooldusjuhend: Undefined
AC_Pset_RenovationAndPhasing - Renovation Status: New
Name | In | OverallHeight (mm) | OverallWidth (mm) | Reference = 300_Tüüp | GlazingAreaFraction | 305_Ava_mõõt | 315_Avanemine | 320_Klaas | 325_Helipidavus | 340_Soojusläbivus | 350_Klaaspakett | 355_Pindala (m2) | 375_Viimistlus_seest = 376_Viimistlus_väljast
5 x A-02 | Esimene korrus | 2000 | 1400 | A-02 | 2.3125 | 1 400x2 000 | avatav - Vasak ; ARCHICAD tüüp: Tilt-Turn | 3xklaaspakett | R´w ≥35 dB | 0.8 | 3xklaaspakett | 2.8 | MUDELIS: Paint - Glossy White; Paint - Glossy White; MÄRKUS:
A-02 | Esimene korrus | 2000 | 1400 | A-02 | 2.3125 | 1 400x2 000 | kaldpöördavanev - Vasak ; ARCHICAD tüüp: Tilt-Turn | 3xklaaspakett | R´w ≥35 dB | 0.8 | 3xklaaspakett | 2.8 | MUDELIS: Paint - Glossy White; Paint - Glossy White; MÄRKUS:
18 x A-02 | Teine korrus | 2000 | 1400 | A-02 | 2.3125 | 1 400x2 000 | kaldpöördavatav - Vasak ; ARCHICAD tüüp: Tilt-Turn | 3xklaaspakett | R´w ≥35 dB | 0.8 | 3xklaaspakett | 2.8 | MUDELIS: Paint - Glossy White; Paint - Glossy White; MÄRKUS:
A-02 | Teine korrus | 2000 | 1400 | A-02 | 2.3125 | 1 400x2 000 | kaldpöördavatav - Vasak ; ARCHICAD tüüp: Tilt-Turn Mirrored | 3xklaaspakett | R´w ≥35 dB | 0.8 | 3xklaaspakett | 2.8 | MUDELIS: Paint - Glossy White; Paint - Glossy White; MÄRKUS:
A-21 | Teine korrus | 1300 | 1550 | A-21 | 1.61 | 1 550x1 300 | osaliselt pöördavatav - Vasak ; ARCHICAD tüüp: Tilt-Turn | 1xklaas | nõudeid ei esitata | 0 | nõudeid ei esitata | 2.015 | MUDELIS: Wood - Pine Grained Horizontal; Wood - Pine Grained Horizontal; MÄRKUS:

# IfcWindow: Window 23 (8)
Type - OperationType: SINGLE_PANEL; ParameterTakesPrecedence: no; Sizeable: no
Type - Window Lining Properties - LiningDepth: 50 mm; LiningThickness: 50 mm
Type - Window Panel Properties - Panel 1 - OperationType: TILTANDTURNRIGHTHAND; PanelPosition: MIDDLE; FrameDepth: 50 mm; FrameThickness: 50 mm
OverallHeight: 2000 mm; Classification: 1.25 IfcWindowStyle (aken) (RKAS BIM + ARCHICAD Classification)
Pset_WindowCommon - ThermalTransmittance: 0; IsExternal: yes
AR_Aken - 001_Nimetus: Välisaken; 310_Materjal: Alumiinium; 320_Klaas: 3xklaaspakett; 325_Helipidavus: R´w ≥35 dB; 330_Tulekindlus: nõudeid ei esitata; 335_Välispiire: yes; 340_Soojusläbivus: 0.8; 345_Päikesekiirgus_tegur: nõudeid ei esitata; 350_Klaaspakett: 3xklaaspakett; 375_Viimistlus_seest: MUDELIS: Paint - Glossy White; Paint - Glossy White; MÄRKUS:; 376_Viimistlus_väljast: MUDELIS: Paint - Glossy White; Paint - Glossy White; MÄRKUS:; 900_Tootja: Undefined; 905_Mudel: Undefined; 910_Tooteinfo: Undefined; 915_Kasutus-ja_hooldusjuhend: Undefined
AC_Pset_RenovationAndPhasing - Renovation Status: New
Name | In | OverallWidth (mm) | Reference = 300_Tüüp | GlazingAreaFraction | 305_Ava_mõõt | 315_Avanemine | 355_Pindala (m2)
3 x A-02 | Esimene korrus | 1400 | A-02 | 2.3125 | 1 400x2 000 | avatav - Parem ; ARCHICAD tüüp: Tilt-Turn | 2.8
4 x A-02 | Teine korrus | 1400 | A-02 | 2.3125 | 1 400x2 000 | kaldpöördavatav - Parem ; ARCHICAD tüüp: Tilt-Turn Mirrored | 2.8
A-01 | Teine korrus | 700 | A-01 | 1.0175 | 700x2 000 | kaldpöördavatav - Parem ; ARCHICAD tüüp: Tilt-Turn | 1.4

# IfcZone (3)
Name | 080_Tähis | 090_Pindala (m2) | 085_Tuletõkkesektsioon
TTS-2 | TTS-1 | 143.6 | EI60 | Classification: 1.0.4 IfcZone (tsoon) (RKAS BIM + ARCHICAD Classification 23 + v 2.0)
TTS-3 | TTS-2 | 30.8 | EI60
TTS-1 |  | 0
